VERSION 5.7 ;
BUSBITCHARS "[]" ;
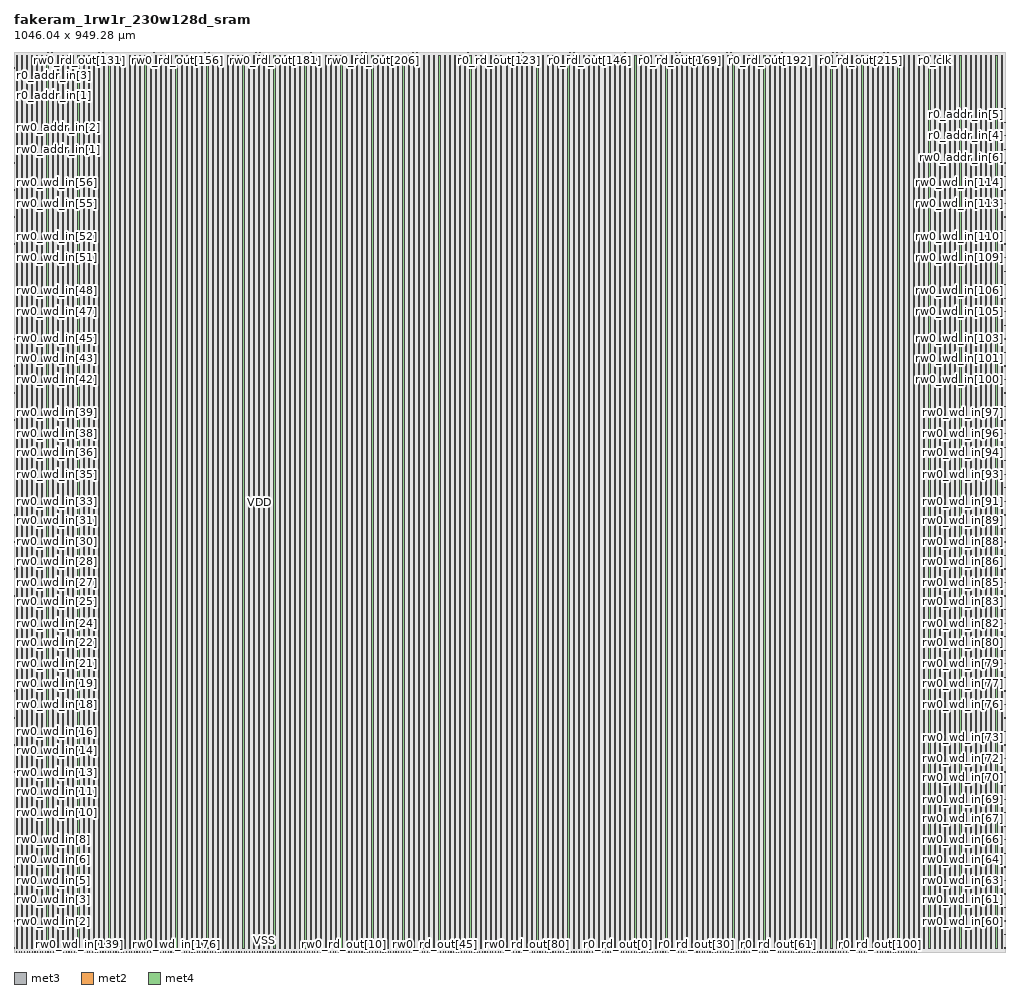
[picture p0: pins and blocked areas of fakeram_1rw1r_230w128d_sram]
MACRO fakeram_1rw1r_230w128d_sram
  FOREIGN fakeram_1rw1r_230w128d_sram 0 0 ;
  SYMMETRY X Y R90 ;
  SIZE 1046.040 BY 949.280 ;
  CLASS BLOCK ;
  PIN rw0_wd_in[0]
    DIRECTION INPUT ;
    USE SIGNAL ;
    SHAPE ABUTMENT ;
    PORT
      LAYER met3 ;
      RECT 0.000 3.930 0.900 4.230 ;
    END
  END rw0_wd_in[0]
  PIN rw0_wd_in[1]
    DIRECTION INPUT ;
    USE SIGNAL ;
    SHAPE ABUTMENT ;
    PORT
      LAYER met3 ;
      RECT 0.000 18.210 0.900 18.510 ;
    END
  END rw0_wd_in[1]
  PIN rw0_wd_in[2]
    DIRECTION INPUT ;
    USE SIGNAL ;
    SHAPE ABUTMENT ;
    PORT
      LAYER met3 ;
      RECT 0.000 32.490 0.900 32.790 ;
    END
  END rw0_wd_in[2]
  PIN rw0_wd_in[3]
    DIRECTION INPUT ;
    USE SIGNAL ;
    SHAPE ABUTMENT ;
    PORT
      LAYER met3 ;
      RECT 0.000 46.770 0.900 47.070 ;
    END
  END rw0_wd_in[3]
  PIN rw0_wd_in[4]
    DIRECTION INPUT ;
    USE SIGNAL ;
    SHAPE ABUTMENT ;
    PORT
      LAYER met3 ;
      RECT 0.000 61.050 0.900 61.350 ;
    END
  END rw0_wd_in[4]
  PIN rw0_wd_in[5]
    DIRECTION INPUT ;
    USE SIGNAL ;
    SHAPE ABUTMENT ;
    PORT
      LAYER met3 ;
      RECT 0.000 75.330 0.900 75.630 ;
    END
  END rw0_wd_in[5]
  PIN rw0_wd_in[6]
    DIRECTION INPUT ;
    USE SIGNAL ;
    SHAPE ABUTMENT ;
    PORT
      LAYER met3 ;
      RECT 0.000 89.610 0.900 89.910 ;
    END
  END rw0_wd_in[6]
  PIN rw0_wd_in[7]
    DIRECTION INPUT ;
    USE SIGNAL ;
    SHAPE ABUTMENT ;
    PORT
      LAYER met3 ;
      RECT 0.000 103.890 0.900 104.190 ;
    END
  END rw0_wd_in[7]
  PIN rw0_wd_in[8]
    DIRECTION INPUT ;
    USE SIGNAL ;
    SHAPE ABUTMENT ;
    PORT
      LAYER met3 ;
      RECT 0.000 118.170 0.900 118.470 ;
    END
  END rw0_wd_in[8]
  PIN rw0_wd_in[9]
    DIRECTION INPUT ;
    USE SIGNAL ;
    SHAPE ABUTMENT ;
    PORT
      LAYER met3 ;
      RECT 0.000 132.450 0.900 132.750 ;
    END
  END rw0_wd_in[9]
  PIN rw0_wd_in[10]
    DIRECTION INPUT ;
    USE SIGNAL ;
    SHAPE ABUTMENT ;
    PORT
      LAYER met3 ;
      RECT 0.000 146.730 0.900 147.030 ;
    END
  END rw0_wd_in[10]
  PIN rw0_wd_in[11]
    DIRECTION INPUT ;
    USE SIGNAL ;
    SHAPE ABUTMENT ;
    PORT
      LAYER met3 ;
      RECT 0.000 161.010 0.900 161.310 ;
    END
  END rw0_wd_in[11]
  PIN rw0_wd_in[12]
    DIRECTION INPUT ;
    USE SIGNAL ;
    SHAPE ABUTMENT ;
    PORT
      LAYER met3 ;
      RECT 0.000 175.290 0.900 175.590 ;
    END
  END rw0_wd_in[12]
  PIN rw0_wd_in[13]
    DIRECTION INPUT ;
    USE SIGNAL ;
    SHAPE ABUTMENT ;
    PORT
      LAYER met3 ;
      RECT 0.000 189.570 0.900 189.870 ;
    END
  END rw0_wd_in[13]
  PIN rw0_wd_in[14]
    DIRECTION INPUT ;
    USE SIGNAL ;
    SHAPE ABUTMENT ;
    PORT
      LAYER met3 ;
      RECT 0.000 203.850 0.900 204.150 ;
    END
  END rw0_wd_in[14]
  PIN rw0_wd_in[15]
    DIRECTION INPUT ;
    USE SIGNAL ;
    SHAPE ABUTMENT ;
    PORT
      LAYER met3 ;
      RECT 0.000 218.130 0.900 218.430 ;
    END
  END rw0_wd_in[15]
  PIN rw0_wd_in[16]
    DIRECTION INPUT ;
    USE SIGNAL ;
    SHAPE ABUTMENT ;
    PORT
      LAYER met3 ;
      RECT 0.000 232.410 0.900 232.710 ;
    END
  END rw0_wd_in[16]
  PIN rw0_wd_in[17]
    DIRECTION INPUT ;
    USE SIGNAL ;
    SHAPE ABUTMENT ;
    PORT
      LAYER met3 ;
      RECT 0.000 246.690 0.900 246.990 ;
    END
  END rw0_wd_in[17]
  PIN rw0_wd_in[18]
    DIRECTION INPUT ;
    USE SIGNAL ;
    SHAPE ABUTMENT ;
    PORT
      LAYER met3 ;
      RECT 0.000 260.970 0.900 261.270 ;
    END
  END rw0_wd_in[18]
  PIN rw0_wd_in[19]
    DIRECTION INPUT ;
    USE SIGNAL ;
    SHAPE ABUTMENT ;
    PORT
      LAYER met3 ;
      RECT 0.000 275.250 0.900 275.550 ;
    END
  END rw0_wd_in[19]
  PIN rw0_wd_in[20]
    DIRECTION INPUT ;
    USE SIGNAL ;
    SHAPE ABUTMENT ;
    PORT
      LAYER met3 ;
      RECT 0.000 289.530 0.900 289.830 ;
    END
  END rw0_wd_in[20]
  PIN rw0_wd_in[21]
    DIRECTION INPUT ;
    USE SIGNAL ;
    SHAPE ABUTMENT ;
    PORT
      LAYER met3 ;
      RECT 0.000 303.810 0.900 304.110 ;
    END
  END rw0_wd_in[21]
  PIN rw0_wd_in[22]
    DIRECTION INPUT ;
    USE SIGNAL ;
    SHAPE ABUTMENT ;
    PORT
      LAYER met3 ;
      RECT 0.000 318.090 0.900 318.390 ;
    END
  END rw0_wd_in[22]
  PIN rw0_wd_in[23]
    DIRECTION INPUT ;
    USE SIGNAL ;
    SHAPE ABUTMENT ;
    PORT
      LAYER met3 ;
      RECT 0.000 332.370 0.900 332.670 ;
    END
  END rw0_wd_in[23]
  PIN rw0_wd_in[24]
    DIRECTION INPUT ;
    USE SIGNAL ;
    SHAPE ABUTMENT ;
    PORT
      LAYER met3 ;
      RECT 0.000 346.650 0.900 346.950 ;
    END
  END rw0_wd_in[24]
  PIN rw0_wd_in[25]
    DIRECTION INPUT ;
    USE SIGNAL ;
    SHAPE ABUTMENT ;
    PORT
      LAYER met3 ;
      RECT 0.000 360.930 0.900 361.230 ;
    END
  END rw0_wd_in[25]
  PIN rw0_wd_in[26]
    DIRECTION INPUT ;
    USE SIGNAL ;
    SHAPE ABUTMENT ;
    PORT
      LAYER met3 ;
      RECT 0.000 375.210 0.900 375.510 ;
    END
  END rw0_wd_in[26]
  PIN rw0_wd_in[27]
    DIRECTION INPUT ;
    USE SIGNAL ;
    SHAPE ABUTMENT ;
    PORT
      LAYER met3 ;
      RECT 0.000 389.490 0.900 389.790 ;
    END
  END rw0_wd_in[27]
  PIN rw0_wd_in[28]
    DIRECTION INPUT ;
    USE SIGNAL ;
    SHAPE ABUTMENT ;
    PORT
      LAYER met3 ;
      RECT 0.000 403.770 0.900 404.070 ;
    END
  END rw0_wd_in[28]
  PIN rw0_wd_in[29]
    DIRECTION INPUT ;
    USE SIGNAL ;
    SHAPE ABUTMENT ;
    PORT
      LAYER met3 ;
      RECT 0.000 418.050 0.900 418.350 ;
    END
  END rw0_wd_in[29]
  PIN rw0_wd_in[30]
    DIRECTION INPUT ;
    USE SIGNAL ;
    SHAPE ABUTMENT ;
    PORT
      LAYER met3 ;
      RECT 0.000 432.330 0.900 432.630 ;
    END
  END rw0_wd_in[30]
  PIN rw0_wd_in[31]
    DIRECTION INPUT ;
    USE SIGNAL ;
    SHAPE ABUTMENT ;
    PORT
      LAYER met3 ;
      RECT 0.000 446.610 0.900 446.910 ;
    END
  END rw0_wd_in[31]
  PIN rw0_wd_in[32]
    DIRECTION INPUT ;
    USE SIGNAL ;
    SHAPE ABUTMENT ;
    PORT
      LAYER met3 ;
      RECT 0.000 460.890 0.900 461.190 ;
    END
  END rw0_wd_in[32]
  PIN rw0_wd_in[33]
    DIRECTION INPUT ;
    USE SIGNAL ;
    SHAPE ABUTMENT ;
    PORT
      LAYER met3 ;
      RECT 0.000 475.170 0.900 475.470 ;
    END
  END rw0_wd_in[33]
  PIN rw0_wd_in[34]
    DIRECTION INPUT ;
    USE SIGNAL ;
    SHAPE ABUTMENT ;
    PORT
      LAYER met3 ;
      RECT 0.000 489.450 0.900 489.750 ;
    END
  END rw0_wd_in[34]
  PIN rw0_wd_in[35]
    DIRECTION INPUT ;
    USE SIGNAL ;
    SHAPE ABUTMENT ;
    PORT
      LAYER met3 ;
      RECT 0.000 503.730 0.900 504.030 ;
    END
  END rw0_wd_in[35]
  PIN rw0_wd_in[36]
    DIRECTION INPUT ;
    USE SIGNAL ;
    SHAPE ABUTMENT ;
    PORT
      LAYER met3 ;
      RECT 0.000 518.010 0.900 518.310 ;
    END
  END rw0_wd_in[36]
  PIN rw0_wd_in[37]
    DIRECTION INPUT ;
    USE SIGNAL ;
    SHAPE ABUTMENT ;
    PORT
      LAYER met3 ;
      RECT 0.000 532.290 0.900 532.590 ;
    END
  END rw0_wd_in[37]
  PIN rw0_wd_in[38]
    DIRECTION INPUT ;
    USE SIGNAL ;
    SHAPE ABUTMENT ;
    PORT
      LAYER met3 ;
      RECT 0.000 546.570 0.900 546.870 ;
    END
  END rw0_wd_in[38]
  PIN rw0_wd_in[39]
    DIRECTION INPUT ;
    USE SIGNAL ;
    SHAPE ABUTMENT ;
    PORT
      LAYER met3 ;
      RECT 0.000 560.850 0.900 561.150 ;
    END
  END rw0_wd_in[39]
  PIN rw0_wd_in[40]
    DIRECTION INPUT ;
    USE SIGNAL ;
    SHAPE ABUTMENT ;
    PORT
      LAYER met3 ;
      RECT 0.000 575.130 0.900 575.430 ;
    END
  END rw0_wd_in[40]
  PIN rw0_wd_in[41]
    DIRECTION INPUT ;
    USE SIGNAL ;
    SHAPE ABUTMENT ;
    PORT
      LAYER met3 ;
      RECT 0.000 589.410 0.900 589.710 ;
    END
  END rw0_wd_in[41]
  PIN rw0_wd_in[42]
    DIRECTION INPUT ;
    USE SIGNAL ;
    SHAPE ABUTMENT ;
    PORT
      LAYER met3 ;
      RECT 0.000 603.690 0.900 603.990 ;
    END
  END rw0_wd_in[42]
  PIN rw0_wd_in[43]
    DIRECTION INPUT ;
    USE SIGNAL ;
    SHAPE ABUTMENT ;
    PORT
      LAYER met3 ;
      RECT 0.000 617.970 0.900 618.270 ;
    END
  END rw0_wd_in[43]
  PIN rw0_wd_in[44]
    DIRECTION INPUT ;
    USE SIGNAL ;
    SHAPE ABUTMENT ;
    PORT
      LAYER met3 ;
      RECT 0.000 632.250 0.900 632.550 ;
    END
  END rw0_wd_in[44]
  PIN rw0_wd_in[45]
    DIRECTION INPUT ;
    USE SIGNAL ;
    SHAPE ABUTMENT ;
    PORT
      LAYER met3 ;
      RECT 0.000 646.530 0.900 646.830 ;
    END
  END rw0_wd_in[45]
  PIN rw0_wd_in[46]
    DIRECTION INPUT ;
    USE SIGNAL ;
    SHAPE ABUTMENT ;
    PORT
      LAYER met3 ;
      RECT 0.000 660.810 0.900 661.110 ;
    END
  END rw0_wd_in[46]
  PIN rw0_wd_in[47]
    DIRECTION INPUT ;
    USE SIGNAL ;
    SHAPE ABUTMENT ;
    PORT
      LAYER met3 ;
      RECT 0.000 675.090 0.900 675.390 ;
    END
  END rw0_wd_in[47]
  PIN rw0_wd_in[48]
    DIRECTION INPUT ;
    USE SIGNAL ;
    SHAPE ABUTMENT ;
    PORT
      LAYER met3 ;
      RECT 0.000 689.370 0.900 689.670 ;
    END
  END rw0_wd_in[48]
  PIN rw0_wd_in[49]
    DIRECTION INPUT ;
    USE SIGNAL ;
    SHAPE ABUTMENT ;
    PORT
      LAYER met3 ;
      RECT 0.000 703.650 0.900 703.950 ;
    END
  END rw0_wd_in[49]
  PIN rw0_wd_in[50]
    DIRECTION INPUT ;
    USE SIGNAL ;
    SHAPE ABUTMENT ;
    PORT
      LAYER met3 ;
      RECT 0.000 717.930 0.900 718.230 ;
    END
  END rw0_wd_in[50]
  PIN rw0_wd_in[51]
    DIRECTION INPUT ;
    USE SIGNAL ;
    SHAPE ABUTMENT ;
    PORT
      LAYER met3 ;
      RECT 0.000 732.210 0.900 732.510 ;
    END
  END rw0_wd_in[51]
  PIN rw0_wd_in[52]
    DIRECTION INPUT ;
    USE SIGNAL ;
    SHAPE ABUTMENT ;
    PORT
      LAYER met3 ;
      RECT 0.000 746.490 0.900 746.790 ;
    END
  END rw0_wd_in[52]
  PIN rw0_wd_in[53]
    DIRECTION INPUT ;
    USE SIGNAL ;
    SHAPE ABUTMENT ;
    PORT
      LAYER met3 ;
      RECT 0.000 760.770 0.900 761.070 ;
    END
  END rw0_wd_in[53]
  PIN rw0_wd_in[54]
    DIRECTION INPUT ;
    USE SIGNAL ;
    SHAPE ABUTMENT ;
    PORT
      LAYER met3 ;
      RECT 0.000 775.050 0.900 775.350 ;
    END
  END rw0_wd_in[54]
  PIN rw0_wd_in[55]
    DIRECTION INPUT ;
    USE SIGNAL ;
    SHAPE ABUTMENT ;
    PORT
      LAYER met3 ;
      RECT 0.000 789.330 0.900 789.630 ;
    END
  END rw0_wd_in[55]
  PIN rw0_wd_in[56]
    DIRECTION INPUT ;
    USE SIGNAL ;
    SHAPE ABUTMENT ;
    PORT
      LAYER met3 ;
      RECT 0.000 803.610 0.900 803.910 ;
    END
  END rw0_wd_in[56]
  PIN rw0_wd_in[57]
    DIRECTION INPUT ;
    USE SIGNAL ;
    SHAPE ABUTMENT ;
    PORT
      LAYER met3 ;
      RECT 0.000 817.890 0.900 818.190 ;
    END
  END rw0_wd_in[57]
  PIN rw0_wd_in[58]
    DIRECTION INPUT ;
    USE SIGNAL ;
    SHAPE ABUTMENT ;
    PORT
      LAYER met3 ;
      RECT 1045.140 3.930 1046.040 4.230 ;
    END
  END rw0_wd_in[58]
  PIN rw0_wd_in[59]
    DIRECTION INPUT ;
    USE SIGNAL ;
    SHAPE ABUTMENT ;
    PORT
      LAYER met3 ;
      RECT 1045.140 18.210 1046.040 18.510 ;
    END
  END rw0_wd_in[59]
  PIN rw0_wd_in[60]
    DIRECTION INPUT ;
    USE SIGNAL ;
    SHAPE ABUTMENT ;
    PORT
      LAYER met3 ;
      RECT 1045.140 32.490 1046.040 32.790 ;
    END
  END rw0_wd_in[60]
  PIN rw0_wd_in[61]
    DIRECTION INPUT ;
    USE SIGNAL ;
    SHAPE ABUTMENT ;
    PORT
      LAYER met3 ;
      RECT 1045.140 46.770 1046.040 47.070 ;
    END
  END rw0_wd_in[61]
  PIN rw0_wd_in[62]
    DIRECTION INPUT ;
    USE SIGNAL ;
    SHAPE ABUTMENT ;
    PORT
      LAYER met3 ;
      RECT 1045.140 61.050 1046.040 61.350 ;
    END
  END rw0_wd_in[62]
  PIN rw0_wd_in[63]
    DIRECTION INPUT ;
    USE SIGNAL ;
    SHAPE ABUTMENT ;
    PORT
      LAYER met3 ;
      RECT 1045.140 75.330 1046.040 75.630 ;
    END
  END rw0_wd_in[63]
  PIN rw0_wd_in[64]
    DIRECTION INPUT ;
    USE SIGNAL ;
    SHAPE ABUTMENT ;
    PORT
      LAYER met3 ;
      RECT 1045.140 89.610 1046.040 89.910 ;
    END
  END rw0_wd_in[64]
  PIN rw0_wd_in[65]
    DIRECTION INPUT ;
    USE SIGNAL ;
    SHAPE ABUTMENT ;
    PORT
      LAYER met3 ;
      RECT 1045.140 103.890 1046.040 104.190 ;
    END
  END rw0_wd_in[65]
  PIN rw0_wd_in[66]
    DIRECTION INPUT ;
    USE SIGNAL ;
    SHAPE ABUTMENT ;
    PORT
      LAYER met3 ;
      RECT 1045.140 118.170 1046.040 118.470 ;
    END
  END rw0_wd_in[66]
  PIN rw0_wd_in[67]
    DIRECTION INPUT ;
    USE SIGNAL ;
    SHAPE ABUTMENT ;
    PORT
      LAYER met3 ;
      RECT 1045.140 132.450 1046.040 132.750 ;
    END
  END rw0_wd_in[67]
  PIN rw0_wd_in[68]
    DIRECTION INPUT ;
    USE SIGNAL ;
    SHAPE ABUTMENT ;
    PORT
      LAYER met3 ;
      RECT 1045.140 146.730 1046.040 147.030 ;
    END
  END rw0_wd_in[68]
  PIN rw0_wd_in[69]
    DIRECTION INPUT ;
    USE SIGNAL ;
    SHAPE ABUTMENT ;
    PORT
      LAYER met3 ;
      RECT 1045.140 161.010 1046.040 161.310 ;
    END
  END rw0_wd_in[69]
  PIN rw0_wd_in[70]
    DIRECTION INPUT ;
    USE SIGNAL ;
    SHAPE ABUTMENT ;
    PORT
      LAYER met3 ;
      RECT 1045.140 175.290 1046.040 175.590 ;
    END
  END rw0_wd_in[70]
  PIN rw0_wd_in[71]
    DIRECTION INPUT ;
    USE SIGNAL ;
    SHAPE ABUTMENT ;
    PORT
      LAYER met3 ;
      RECT 1045.140 189.570 1046.040 189.870 ;
    END
  END rw0_wd_in[71]
  PIN rw0_wd_in[72]
    DIRECTION INPUT ;
    USE SIGNAL ;
    SHAPE ABUTMENT ;
    PORT
      LAYER met3 ;
      RECT 1045.140 203.850 1046.040 204.150 ;
    END
  END rw0_wd_in[72]
  PIN rw0_wd_in[73]
    DIRECTION INPUT ;
    USE SIGNAL ;
    SHAPE ABUTMENT ;
    PORT
      LAYER met3 ;
      RECT 1045.140 218.130 1046.040 218.430 ;
    END
  END rw0_wd_in[73]
  PIN rw0_wd_in[74]
    DIRECTION INPUT ;
    USE SIGNAL ;
    SHAPE ABUTMENT ;
    PORT
      LAYER met3 ;
      RECT 1045.140 232.410 1046.040 232.710 ;
    END
  END rw0_wd_in[74]
  PIN rw0_wd_in[75]
    DIRECTION INPUT ;
    USE SIGNAL ;
    SHAPE ABUTMENT ;
    PORT
      LAYER met3 ;
      RECT 1045.140 246.690 1046.040 246.990 ;
    END
  END rw0_wd_in[75]
  PIN rw0_wd_in[76]
    DIRECTION INPUT ;
    USE SIGNAL ;
    SHAPE ABUTMENT ;
    PORT
      LAYER met3 ;
      RECT 1045.140 260.970 1046.040 261.270 ;
    END
  END rw0_wd_in[76]
  PIN rw0_wd_in[77]
    DIRECTION INPUT ;
    USE SIGNAL ;
    SHAPE ABUTMENT ;
    PORT
      LAYER met3 ;
      RECT 1045.140 275.250 1046.040 275.550 ;
    END
  END rw0_wd_in[77]
  PIN rw0_wd_in[78]
    DIRECTION INPUT ;
    USE SIGNAL ;
    SHAPE ABUTMENT ;
    PORT
      LAYER met3 ;
      RECT 1045.140 289.530 1046.040 289.830 ;
    END
  END rw0_wd_in[78]
  PIN rw0_wd_in[79]
    DIRECTION INPUT ;
    USE SIGNAL ;
    SHAPE ABUTMENT ;
    PORT
      LAYER met3 ;
      RECT 1045.140 303.810 1046.040 304.110 ;
    END
  END rw0_wd_in[79]
  PIN rw0_wd_in[80]
    DIRECTION INPUT ;
    USE SIGNAL ;
    SHAPE ABUTMENT ;
    PORT
      LAYER met3 ;
      RECT 1045.140 318.090 1046.040 318.390 ;
    END
  END rw0_wd_in[80]
  PIN rw0_wd_in[81]
    DIRECTION INPUT ;
    USE SIGNAL ;
    SHAPE ABUTMENT ;
    PORT
      LAYER met3 ;
      RECT 1045.140 332.370 1046.040 332.670 ;
    END
  END rw0_wd_in[81]
  PIN rw0_wd_in[82]
    DIRECTION INPUT ;
    USE SIGNAL ;
    SHAPE ABUTMENT ;
    PORT
      LAYER met3 ;
      RECT 1045.140 346.650 1046.040 346.950 ;
    END
  END rw0_wd_in[82]
  PIN rw0_wd_in[83]
    DIRECTION INPUT ;
    USE SIGNAL ;
    SHAPE ABUTMENT ;
    PORT
      LAYER met3 ;
      RECT 1045.140 360.930 1046.040 361.230 ;
    END
  END rw0_wd_in[83]
  PIN rw0_wd_in[84]
    DIRECTION INPUT ;
    USE SIGNAL ;
    SHAPE ABUTMENT ;
    PORT
      LAYER met3 ;
      RECT 1045.140 375.210 1046.040 375.510 ;
    END
  END rw0_wd_in[84]
  PIN rw0_wd_in[85]
    DIRECTION INPUT ;
    USE SIGNAL ;
    SHAPE ABUTMENT ;
    PORT
      LAYER met3 ;
      RECT 1045.140 389.490 1046.040 389.790 ;
    END
  END rw0_wd_in[85]
  PIN rw0_wd_in[86]
    DIRECTION INPUT ;
    USE SIGNAL ;
    SHAPE ABUTMENT ;
    PORT
      LAYER met3 ;
      RECT 1045.140 403.770 1046.040 404.070 ;
    END
  END rw0_wd_in[86]
  PIN rw0_wd_in[87]
    DIRECTION INPUT ;
    USE SIGNAL ;
    SHAPE ABUTMENT ;
    PORT
      LAYER met3 ;
      RECT 1045.140 418.050 1046.040 418.350 ;
    END
  END rw0_wd_in[87]
  PIN rw0_wd_in[88]
    DIRECTION INPUT ;
    USE SIGNAL ;
    SHAPE ABUTMENT ;
    PORT
      LAYER met3 ;
      RECT 1045.140 432.330 1046.040 432.630 ;
    END
  END rw0_wd_in[88]
  PIN rw0_wd_in[89]
    DIRECTION INPUT ;
    USE SIGNAL ;
    SHAPE ABUTMENT ;
    PORT
      LAYER met3 ;
      RECT 1045.140 446.610 1046.040 446.910 ;
    END
  END rw0_wd_in[89]
  PIN rw0_wd_in[90]
    DIRECTION INPUT ;
    USE SIGNAL ;
    SHAPE ABUTMENT ;
    PORT
      LAYER met3 ;
      RECT 1045.140 460.890 1046.040 461.190 ;
    END
  END rw0_wd_in[90]
  PIN rw0_wd_in[91]
    DIRECTION INPUT ;
    USE SIGNAL ;
    SHAPE ABUTMENT ;
    PORT
      LAYER met3 ;
      RECT 1045.140 475.170 1046.040 475.470 ;
    END
  END rw0_wd_in[91]
  PIN rw0_wd_in[92]
    DIRECTION INPUT ;
    USE SIGNAL ;
    SHAPE ABUTMENT ;
    PORT
      LAYER met3 ;
      RECT 1045.140 489.450 1046.040 489.750 ;
    END
  END rw0_wd_in[92]
  PIN rw0_wd_in[93]
    DIRECTION INPUT ;
    USE SIGNAL ;
    SHAPE ABUTMENT ;
    PORT
      LAYER met3 ;
      RECT 1045.140 503.730 1046.040 504.030 ;
    END
  END rw0_wd_in[93]
  PIN rw0_wd_in[94]
    DIRECTION INPUT ;
    USE SIGNAL ;
    SHAPE ABUTMENT ;
    PORT
      LAYER met3 ;
      RECT 1045.140 518.010 1046.040 518.310 ;
    END
  END rw0_wd_in[94]
  PIN rw0_wd_in[95]
    DIRECTION INPUT ;
    USE SIGNAL ;
    SHAPE ABUTMENT ;
    PORT
      LAYER met3 ;
      RECT 1045.140 532.290 1046.040 532.590 ;
    END
  END rw0_wd_in[95]
  PIN rw0_wd_in[96]
    DIRECTION INPUT ;
    USE SIGNAL ;
    SHAPE ABUTMENT ;
    PORT
      LAYER met3 ;
      RECT 1045.140 546.570 1046.040 546.870 ;
    END
  END rw0_wd_in[96]
  PIN rw0_wd_in[97]
    DIRECTION INPUT ;
    USE SIGNAL ;
    SHAPE ABUTMENT ;
    PORT
      LAYER met3 ;
      RECT 1045.140 560.850 1046.040 561.150 ;
    END
  END rw0_wd_in[97]
  PIN rw0_wd_in[98]
    DIRECTION INPUT ;
    USE SIGNAL ;
    SHAPE ABUTMENT ;
    PORT
      LAYER met3 ;
      RECT 1045.140 575.130 1046.040 575.430 ;
    END
  END rw0_wd_in[98]
  PIN rw0_wd_in[99]
    DIRECTION INPUT ;
    USE SIGNAL ;
    SHAPE ABUTMENT ;
    PORT
      LAYER met3 ;
      RECT 1045.140 589.410 1046.040 589.710 ;
    END
  END rw0_wd_in[99]
  PIN rw0_wd_in[100]
    DIRECTION INPUT ;
    USE SIGNAL ;
    SHAPE ABUTMENT ;
    PORT
      LAYER met3 ;
      RECT 1045.140 603.690 1046.040 603.990 ;
    END
  END rw0_wd_in[100]
  PIN rw0_wd_in[101]
    DIRECTION INPUT ;
    USE SIGNAL ;
    SHAPE ABUTMENT ;
    PORT
      LAYER met3 ;
      RECT 1045.140 617.970 1046.040 618.270 ;
    END
  END rw0_wd_in[101]
  PIN rw0_wd_in[102]
    DIRECTION INPUT ;
    USE SIGNAL ;
    SHAPE ABUTMENT ;
    PORT
      LAYER met3 ;
      RECT 1045.140 632.250 1046.040 632.550 ;
    END
  END rw0_wd_in[102]
  PIN rw0_wd_in[103]
    DIRECTION INPUT ;
    USE SIGNAL ;
    SHAPE ABUTMENT ;
    PORT
      LAYER met3 ;
      RECT 1045.140 646.530 1046.040 646.830 ;
    END
  END rw0_wd_in[103]
  PIN rw0_wd_in[104]
    DIRECTION INPUT ;
    USE SIGNAL ;
    SHAPE ABUTMENT ;
    PORT
      LAYER met3 ;
      RECT 1045.140 660.810 1046.040 661.110 ;
    END
  END rw0_wd_in[104]
  PIN rw0_wd_in[105]
    DIRECTION INPUT ;
    USE SIGNAL ;
    SHAPE ABUTMENT ;
    PORT
      LAYER met3 ;
      RECT 1045.140 675.090 1046.040 675.390 ;
    END
  END rw0_wd_in[105]
  PIN rw0_wd_in[106]
    DIRECTION INPUT ;
    USE SIGNAL ;
    SHAPE ABUTMENT ;
    PORT
      LAYER met3 ;
      RECT 1045.140 689.370 1046.040 689.670 ;
    END
  END rw0_wd_in[106]
  PIN rw0_wd_in[107]
    DIRECTION INPUT ;
    USE SIGNAL ;
    SHAPE ABUTMENT ;
    PORT
      LAYER met3 ;
      RECT 1045.140 703.650 1046.040 703.950 ;
    END
  END rw0_wd_in[107]
  PIN rw0_wd_in[108]
    DIRECTION INPUT ;
    USE SIGNAL ;
    SHAPE ABUTMENT ;
    PORT
      LAYER met3 ;
      RECT 1045.140 717.930 1046.040 718.230 ;
    END
  END rw0_wd_in[108]
  PIN rw0_wd_in[109]
    DIRECTION INPUT ;
    USE SIGNAL ;
    SHAPE ABUTMENT ;
    PORT
      LAYER met3 ;
      RECT 1045.140 732.210 1046.040 732.510 ;
    END
  END rw0_wd_in[109]
  PIN rw0_wd_in[110]
    DIRECTION INPUT ;
    USE SIGNAL ;
    SHAPE ABUTMENT ;
    PORT
      LAYER met3 ;
      RECT 1045.140 746.490 1046.040 746.790 ;
    END
  END rw0_wd_in[110]
  PIN rw0_wd_in[111]
    DIRECTION INPUT ;
    USE SIGNAL ;
    SHAPE ABUTMENT ;
    PORT
      LAYER met3 ;
      RECT 1045.140 760.770 1046.040 761.070 ;
    END
  END rw0_wd_in[111]
  PIN rw0_wd_in[112]
    DIRECTION INPUT ;
    USE SIGNAL ;
    SHAPE ABUTMENT ;
    PORT
      LAYER met3 ;
      RECT 1045.140 775.050 1046.040 775.350 ;
    END
  END rw0_wd_in[112]
  PIN rw0_wd_in[113]
    DIRECTION INPUT ;
    USE SIGNAL ;
    SHAPE ABUTMENT ;
    PORT
      LAYER met3 ;
      RECT 1045.140 789.330 1046.040 789.630 ;
    END
  END rw0_wd_in[113]
  PIN rw0_wd_in[114]
    DIRECTION INPUT ;
    USE SIGNAL ;
    SHAPE ABUTMENT ;
    PORT
      LAYER met3 ;
      RECT 1045.140 803.610 1046.040 803.910 ;
    END
  END rw0_wd_in[114]
  PIN rw0_wd_in[115]
    DIRECTION INPUT ;
    USE SIGNAL ;
    SHAPE ABUTMENT ;
    PORT
      LAYER met2 ;
      RECT 2.690 0.000 2.830 0.420 ;
    END
  END rw0_wd_in[115]
  PIN rw0_wd_in[116]
    DIRECTION INPUT ;
    USE SIGNAL ;
    SHAPE ABUTMENT ;
    PORT
      LAYER met2 ;
      RECT 5.450 0.000 5.590 0.420 ;
    END
  END rw0_wd_in[116]
  PIN rw0_wd_in[117]
    DIRECTION INPUT ;
    USE SIGNAL ;
    SHAPE ABUTMENT ;
    PORT
      LAYER met2 ;
      RECT 8.210 0.000 8.350 0.420 ;
    END
  END rw0_wd_in[117]
  PIN rw0_wd_in[118]
    DIRECTION INPUT ;
    USE SIGNAL ;
    SHAPE ABUTMENT ;
    PORT
      LAYER met2 ;
      RECT 10.970 0.000 11.110 0.420 ;
    END
  END rw0_wd_in[118]
  PIN rw0_wd_in[119]
    DIRECTION INPUT ;
    USE SIGNAL ;
    SHAPE ABUTMENT ;
    PORT
      LAYER met2 ;
      RECT 13.730 0.000 13.870 0.420 ;
    END
  END rw0_wd_in[119]
  PIN rw0_wd_in[120]
    DIRECTION INPUT ;
    USE SIGNAL ;
    SHAPE ABUTMENT ;
    PORT
      LAYER met2 ;
      RECT 16.490 0.000 16.630 0.420 ;
    END
  END rw0_wd_in[120]
  PIN rw0_wd_in[121]
    DIRECTION INPUT ;
    USE SIGNAL ;
    SHAPE ABUTMENT ;
    PORT
      LAYER met2 ;
      RECT 19.250 0.000 19.390 0.420 ;
    END
  END rw0_wd_in[121]
  PIN rw0_wd_in[122]
    DIRECTION INPUT ;
    USE SIGNAL ;
    SHAPE ABUTMENT ;
    PORT
      LAYER met2 ;
      RECT 22.010 0.000 22.150 0.420 ;
    END
  END rw0_wd_in[122]
  PIN rw0_wd_in[123]
    DIRECTION INPUT ;
    USE SIGNAL ;
    SHAPE ABUTMENT ;
    PORT
      LAYER met2 ;
      RECT 24.770 0.000 24.910 0.420 ;
    END
  END rw0_wd_in[123]
  PIN rw0_wd_in[124]
    DIRECTION INPUT ;
    USE SIGNAL ;
    SHAPE ABUTMENT ;
    PORT
      LAYER met2 ;
      RECT 27.530 0.000 27.670 0.420 ;
    END
  END rw0_wd_in[124]
  PIN rw0_wd_in[125]
    DIRECTION INPUT ;
    USE SIGNAL ;
    SHAPE ABUTMENT ;
    PORT
      LAYER met2 ;
      RECT 30.290 0.000 30.430 0.420 ;
    END
  END rw0_wd_in[125]
  PIN rw0_wd_in[126]
    DIRECTION INPUT ;
    USE SIGNAL ;
    SHAPE ABUTMENT ;
    PORT
      LAYER met2 ;
      RECT 33.050 0.000 33.190 0.420 ;
    END
  END rw0_wd_in[126]
  PIN rw0_wd_in[127]
    DIRECTION INPUT ;
    USE SIGNAL ;
    SHAPE ABUTMENT ;
    PORT
      LAYER met2 ;
      RECT 35.810 0.000 35.950 0.420 ;
    END
  END rw0_wd_in[127]
  PIN rw0_wd_in[128]
    DIRECTION INPUT ;
    USE SIGNAL ;
    SHAPE ABUTMENT ;
    PORT
      LAYER met2 ;
      RECT 38.570 0.000 38.710 0.420 ;
    END
  END rw0_wd_in[128]
  PIN rw0_wd_in[129]
    DIRECTION INPUT ;
    USE SIGNAL ;
    SHAPE ABUTMENT ;
    PORT
      LAYER met2 ;
      RECT 41.330 0.000 41.470 0.420 ;
    END
  END rw0_wd_in[129]
  PIN rw0_wd_in[130]
    DIRECTION INPUT ;
    USE SIGNAL ;
    SHAPE ABUTMENT ;
    PORT
      LAYER met2 ;
      RECT 44.090 0.000 44.230 0.420 ;
    END
  END rw0_wd_in[130]
  PIN rw0_wd_in[131]
    DIRECTION INPUT ;
    USE SIGNAL ;
    SHAPE ABUTMENT ;
    PORT
      LAYER met2 ;
      RECT 46.850 0.000 46.990 0.420 ;
    END
  END rw0_wd_in[131]
  PIN rw0_wd_in[132]
    DIRECTION INPUT ;
    USE SIGNAL ;
    SHAPE ABUTMENT ;
    PORT
      LAYER met2 ;
      RECT 49.610 0.000 49.750 0.420 ;
    END
  END rw0_wd_in[132]
  PIN rw0_wd_in[133]
    DIRECTION INPUT ;
    USE SIGNAL ;
    SHAPE ABUTMENT ;
    PORT
      LAYER met2 ;
      RECT 52.370 0.000 52.510 0.420 ;
    END
  END rw0_wd_in[133]
  PIN rw0_wd_in[134]
    DIRECTION INPUT ;
    USE SIGNAL ;
    SHAPE ABUTMENT ;
    PORT
      LAYER met2 ;
      RECT 55.130 0.000 55.270 0.420 ;
    END
  END rw0_wd_in[134]
  PIN rw0_wd_in[135]
    DIRECTION INPUT ;
    USE SIGNAL ;
    SHAPE ABUTMENT ;
    PORT
      LAYER met2 ;
      RECT 57.890 0.000 58.030 0.420 ;
    END
  END rw0_wd_in[135]
  PIN rw0_wd_in[136]
    DIRECTION INPUT ;
    USE SIGNAL ;
    SHAPE ABUTMENT ;
    PORT
      LAYER met2 ;
      RECT 60.650 0.000 60.790 0.420 ;
    END
  END rw0_wd_in[136]
  PIN rw0_wd_in[137]
    DIRECTION INPUT ;
    USE SIGNAL ;
    SHAPE ABUTMENT ;
    PORT
      LAYER met2 ;
      RECT 63.410 0.000 63.550 0.420 ;
    END
  END rw0_wd_in[137]
  PIN rw0_wd_in[138]
    DIRECTION INPUT ;
    USE SIGNAL ;
    SHAPE ABUTMENT ;
    PORT
      LAYER met2 ;
      RECT 66.170 0.000 66.310 0.420 ;
    END
  END rw0_wd_in[138]
  PIN rw0_wd_in[139]
    DIRECTION INPUT ;
    USE SIGNAL ;
    SHAPE ABUTMENT ;
    PORT
      LAYER met2 ;
      RECT 68.930 0.000 69.070 0.420 ;
    END
  END rw0_wd_in[139]
  PIN rw0_wd_in[140]
    DIRECTION INPUT ;
    USE SIGNAL ;
    SHAPE ABUTMENT ;
    PORT
      LAYER met2 ;
      RECT 71.690 0.000 71.830 0.420 ;
    END
  END rw0_wd_in[140]
  PIN rw0_wd_in[141]
    DIRECTION INPUT ;
    USE SIGNAL ;
    SHAPE ABUTMENT ;
    PORT
      LAYER met2 ;
      RECT 74.450 0.000 74.590 0.420 ;
    END
  END rw0_wd_in[141]
  PIN rw0_wd_in[142]
    DIRECTION INPUT ;
    USE SIGNAL ;
    SHAPE ABUTMENT ;
    PORT
      LAYER met2 ;
      RECT 77.210 0.000 77.350 0.420 ;
    END
  END rw0_wd_in[142]
  PIN rw0_wd_in[143]
    DIRECTION INPUT ;
    USE SIGNAL ;
    SHAPE ABUTMENT ;
    PORT
      LAYER met2 ;
      RECT 79.970 0.000 80.110 0.420 ;
    END
  END rw0_wd_in[143]
  PIN rw0_wd_in[144]
    DIRECTION INPUT ;
    USE SIGNAL ;
    SHAPE ABUTMENT ;
    PORT
      LAYER met2 ;
      RECT 82.730 0.000 82.870 0.420 ;
    END
  END rw0_wd_in[144]
  PIN rw0_wd_in[145]
    DIRECTION INPUT ;
    USE SIGNAL ;
    SHAPE ABUTMENT ;
    PORT
      LAYER met2 ;
      RECT 85.490 0.000 85.630 0.420 ;
    END
  END rw0_wd_in[145]
  PIN rw0_wd_in[146]
    DIRECTION INPUT ;
    USE SIGNAL ;
    SHAPE ABUTMENT ;
    PORT
      LAYER met2 ;
      RECT 88.250 0.000 88.390 0.420 ;
    END
  END rw0_wd_in[146]
  PIN rw0_wd_in[147]
    DIRECTION INPUT ;
    USE SIGNAL ;
    SHAPE ABUTMENT ;
    PORT
      LAYER met2 ;
      RECT 91.010 0.000 91.150 0.420 ;
    END
  END rw0_wd_in[147]
  PIN rw0_wd_in[148]
    DIRECTION INPUT ;
    USE SIGNAL ;
    SHAPE ABUTMENT ;
    PORT
      LAYER met2 ;
      RECT 93.770 0.000 93.910 0.420 ;
    END
  END rw0_wd_in[148]
  PIN rw0_wd_in[149]
    DIRECTION INPUT ;
    USE SIGNAL ;
    SHAPE ABUTMENT ;
    PORT
      LAYER met2 ;
      RECT 96.530 0.000 96.670 0.420 ;
    END
  END rw0_wd_in[149]
  PIN rw0_wd_in[150]
    DIRECTION INPUT ;
    USE SIGNAL ;
    SHAPE ABUTMENT ;
    PORT
      LAYER met2 ;
      RECT 99.290 0.000 99.430 0.420 ;
    END
  END rw0_wd_in[150]
  PIN rw0_wd_in[151]
    DIRECTION INPUT ;
    USE SIGNAL ;
    SHAPE ABUTMENT ;
    PORT
      LAYER met2 ;
      RECT 102.050 0.000 102.190 0.420 ;
    END
  END rw0_wd_in[151]
  PIN rw0_wd_in[152]
    DIRECTION INPUT ;
    USE SIGNAL ;
    SHAPE ABUTMENT ;
    PORT
      LAYER met2 ;
      RECT 104.810 0.000 104.950 0.420 ;
    END
  END rw0_wd_in[152]
  PIN rw0_wd_in[153]
    DIRECTION INPUT ;
    USE SIGNAL ;
    SHAPE ABUTMENT ;
    PORT
      LAYER met2 ;
      RECT 107.570 0.000 107.710 0.420 ;
    END
  END rw0_wd_in[153]
  PIN rw0_wd_in[154]
    DIRECTION INPUT ;
    USE SIGNAL ;
    SHAPE ABUTMENT ;
    PORT
      LAYER met2 ;
      RECT 110.330 0.000 110.470 0.420 ;
    END
  END rw0_wd_in[154]
  PIN rw0_wd_in[155]
    DIRECTION INPUT ;
    USE SIGNAL ;
    SHAPE ABUTMENT ;
    PORT
      LAYER met2 ;
      RECT 113.090 0.000 113.230 0.420 ;
    END
  END rw0_wd_in[155]
  PIN rw0_wd_in[156]
    DIRECTION INPUT ;
    USE SIGNAL ;
    SHAPE ABUTMENT ;
    PORT
      LAYER met2 ;
      RECT 115.850 0.000 115.990 0.420 ;
    END
  END rw0_wd_in[156]
  PIN rw0_wd_in[157]
    DIRECTION INPUT ;
    USE SIGNAL ;
    SHAPE ABUTMENT ;
    PORT
      LAYER met2 ;
      RECT 118.610 0.000 118.750 0.420 ;
    END
  END rw0_wd_in[157]
  PIN rw0_wd_in[158]
    DIRECTION INPUT ;
    USE SIGNAL ;
    SHAPE ABUTMENT ;
    PORT
      LAYER met2 ;
      RECT 121.370 0.000 121.510 0.420 ;
    END
  END rw0_wd_in[158]
  PIN rw0_wd_in[159]
    DIRECTION INPUT ;
    USE SIGNAL ;
    SHAPE ABUTMENT ;
    PORT
      LAYER met2 ;
      RECT 124.130 0.000 124.270 0.420 ;
    END
  END rw0_wd_in[159]
  PIN rw0_wd_in[160]
    DIRECTION INPUT ;
    USE SIGNAL ;
    SHAPE ABUTMENT ;
    PORT
      LAYER met2 ;
      RECT 126.890 0.000 127.030 0.420 ;
    END
  END rw0_wd_in[160]
  PIN rw0_wd_in[161]
    DIRECTION INPUT ;
    USE SIGNAL ;
    SHAPE ABUTMENT ;
    PORT
      LAYER met2 ;
      RECT 129.650 0.000 129.790 0.420 ;
    END
  END rw0_wd_in[161]
  PIN rw0_wd_in[162]
    DIRECTION INPUT ;
    USE SIGNAL ;
    SHAPE ABUTMENT ;
    PORT
      LAYER met2 ;
      RECT 132.410 0.000 132.550 0.420 ;
    END
  END rw0_wd_in[162]
  PIN rw0_wd_in[163]
    DIRECTION INPUT ;
    USE SIGNAL ;
    SHAPE ABUTMENT ;
    PORT
      LAYER met2 ;
      RECT 135.170 0.000 135.310 0.420 ;
    END
  END rw0_wd_in[163]
  PIN rw0_wd_in[164]
    DIRECTION INPUT ;
    USE SIGNAL ;
    SHAPE ABUTMENT ;
    PORT
      LAYER met2 ;
      RECT 137.930 0.000 138.070 0.420 ;
    END
  END rw0_wd_in[164]
  PIN rw0_wd_in[165]
    DIRECTION INPUT ;
    USE SIGNAL ;
    SHAPE ABUTMENT ;
    PORT
      LAYER met2 ;
      RECT 140.690 0.000 140.830 0.420 ;
    END
  END rw0_wd_in[165]
  PIN rw0_wd_in[166]
    DIRECTION INPUT ;
    USE SIGNAL ;
    SHAPE ABUTMENT ;
    PORT
      LAYER met2 ;
      RECT 143.450 0.000 143.590 0.420 ;
    END
  END rw0_wd_in[166]
  PIN rw0_wd_in[167]
    DIRECTION INPUT ;
    USE SIGNAL ;
    SHAPE ABUTMENT ;
    PORT
      LAYER met2 ;
      RECT 146.210 0.000 146.350 0.420 ;
    END
  END rw0_wd_in[167]
  PIN rw0_wd_in[168]
    DIRECTION INPUT ;
    USE SIGNAL ;
    SHAPE ABUTMENT ;
    PORT
      LAYER met2 ;
      RECT 148.970 0.000 149.110 0.420 ;
    END
  END rw0_wd_in[168]
  PIN rw0_wd_in[169]
    DIRECTION INPUT ;
    USE SIGNAL ;
    SHAPE ABUTMENT ;
    PORT
      LAYER met2 ;
      RECT 151.730 0.000 151.870 0.420 ;
    END
  END rw0_wd_in[169]
  PIN rw0_wd_in[170]
    DIRECTION INPUT ;
    USE SIGNAL ;
    SHAPE ABUTMENT ;
    PORT
      LAYER met2 ;
      RECT 154.490 0.000 154.630 0.420 ;
    END
  END rw0_wd_in[170]
  PIN rw0_wd_in[171]
    DIRECTION INPUT ;
    USE SIGNAL ;
    SHAPE ABUTMENT ;
    PORT
      LAYER met2 ;
      RECT 157.250 0.000 157.390 0.420 ;
    END
  END rw0_wd_in[171]
  PIN rw0_wd_in[172]
    DIRECTION INPUT ;
    USE SIGNAL ;
    SHAPE ABUTMENT ;
    PORT
      LAYER met2 ;
      RECT 160.010 0.000 160.150 0.420 ;
    END
  END rw0_wd_in[172]
  PIN rw0_wd_in[173]
    DIRECTION INPUT ;
    USE SIGNAL ;
    SHAPE ABUTMENT ;
    PORT
      LAYER met2 ;
      RECT 162.770 0.000 162.910 0.420 ;
    END
  END rw0_wd_in[173]
  PIN rw0_wd_in[174]
    DIRECTION INPUT ;
    USE SIGNAL ;
    SHAPE ABUTMENT ;
    PORT
      LAYER met2 ;
      RECT 165.530 0.000 165.670 0.420 ;
    END
  END rw0_wd_in[174]
  PIN rw0_wd_in[175]
    DIRECTION INPUT ;
    USE SIGNAL ;
    SHAPE ABUTMENT ;
    PORT
      LAYER met2 ;
      RECT 168.290 0.000 168.430 0.420 ;
    END
  END rw0_wd_in[175]
  PIN rw0_wd_in[176]
    DIRECTION INPUT ;
    USE SIGNAL ;
    SHAPE ABUTMENT ;
    PORT
      LAYER met2 ;
      RECT 171.050 0.000 171.190 0.420 ;
    END
  END rw0_wd_in[176]
  PIN rw0_wd_in[177]
    DIRECTION INPUT ;
    USE SIGNAL ;
    SHAPE ABUTMENT ;
    PORT
      LAYER met2 ;
      RECT 173.810 0.000 173.950 0.420 ;
    END
  END rw0_wd_in[177]
  PIN rw0_wd_in[178]
    DIRECTION INPUT ;
    USE SIGNAL ;
    SHAPE ABUTMENT ;
    PORT
      LAYER met2 ;
      RECT 176.570 0.000 176.710 0.420 ;
    END
  END rw0_wd_in[178]
  PIN rw0_wd_in[179]
    DIRECTION INPUT ;
    USE SIGNAL ;
    SHAPE ABUTMENT ;
    PORT
      LAYER met2 ;
      RECT 179.330 0.000 179.470 0.420 ;
    END
  END rw0_wd_in[179]
  PIN rw0_wd_in[180]
    DIRECTION INPUT ;
    USE SIGNAL ;
    SHAPE ABUTMENT ;
    PORT
      LAYER met2 ;
      RECT 182.090 0.000 182.230 0.420 ;
    END
  END rw0_wd_in[180]
  PIN rw0_wd_in[181]
    DIRECTION INPUT ;
    USE SIGNAL ;
    SHAPE ABUTMENT ;
    PORT
      LAYER met2 ;
      RECT 184.850 0.000 184.990 0.420 ;
    END
  END rw0_wd_in[181]
  PIN rw0_wd_in[182]
    DIRECTION INPUT ;
    USE SIGNAL ;
    SHAPE ABUTMENT ;
    PORT
      LAYER met2 ;
      RECT 187.610 0.000 187.750 0.420 ;
    END
  END rw0_wd_in[182]
  PIN rw0_wd_in[183]
    DIRECTION INPUT ;
    USE SIGNAL ;
    SHAPE ABUTMENT ;
    PORT
      LAYER met2 ;
      RECT 190.370 0.000 190.510 0.420 ;
    END
  END rw0_wd_in[183]
  PIN rw0_wd_in[184]
    DIRECTION INPUT ;
    USE SIGNAL ;
    SHAPE ABUTMENT ;
    PORT
      LAYER met2 ;
      RECT 193.130 0.000 193.270 0.420 ;
    END
  END rw0_wd_in[184]
  PIN rw0_wd_in[185]
    DIRECTION INPUT ;
    USE SIGNAL ;
    SHAPE ABUTMENT ;
    PORT
      LAYER met2 ;
      RECT 195.890 0.000 196.030 0.420 ;
    END
  END rw0_wd_in[185]
  PIN rw0_wd_in[186]
    DIRECTION INPUT ;
    USE SIGNAL ;
    SHAPE ABUTMENT ;
    PORT
      LAYER met2 ;
      RECT 198.650 0.000 198.790 0.420 ;
    END
  END rw0_wd_in[186]
  PIN rw0_wd_in[187]
    DIRECTION INPUT ;
    USE SIGNAL ;
    SHAPE ABUTMENT ;
    PORT
      LAYER met2 ;
      RECT 201.410 0.000 201.550 0.420 ;
    END
  END rw0_wd_in[187]
  PIN rw0_wd_in[188]
    DIRECTION INPUT ;
    USE SIGNAL ;
    SHAPE ABUTMENT ;
    PORT
      LAYER met2 ;
      RECT 204.170 0.000 204.310 0.420 ;
    END
  END rw0_wd_in[188]
  PIN rw0_wd_in[189]
    DIRECTION INPUT ;
    USE SIGNAL ;
    SHAPE ABUTMENT ;
    PORT
      LAYER met2 ;
      RECT 206.930 0.000 207.070 0.420 ;
    END
  END rw0_wd_in[189]
  PIN rw0_wd_in[190]
    DIRECTION INPUT ;
    USE SIGNAL ;
    SHAPE ABUTMENT ;
    PORT
      LAYER met2 ;
      RECT 209.690 0.000 209.830 0.420 ;
    END
  END rw0_wd_in[190]
  PIN rw0_wd_in[191]
    DIRECTION INPUT ;
    USE SIGNAL ;
    SHAPE ABUTMENT ;
    PORT
      LAYER met2 ;
      RECT 212.450 0.000 212.590 0.420 ;
    END
  END rw0_wd_in[191]
  PIN rw0_wd_in[192]
    DIRECTION INPUT ;
    USE SIGNAL ;
    SHAPE ABUTMENT ;
    PORT
      LAYER met2 ;
      RECT 215.210 0.000 215.350 0.420 ;
    END
  END rw0_wd_in[192]
  PIN rw0_wd_in[193]
    DIRECTION INPUT ;
    USE SIGNAL ;
    SHAPE ABUTMENT ;
    PORT
      LAYER met2 ;
      RECT 217.970 0.000 218.110 0.420 ;
    END
  END rw0_wd_in[193]
  PIN rw0_wd_in[194]
    DIRECTION INPUT ;
    USE SIGNAL ;
    SHAPE ABUTMENT ;
    PORT
      LAYER met2 ;
      RECT 220.730 0.000 220.870 0.420 ;
    END
  END rw0_wd_in[194]
  PIN rw0_wd_in[195]
    DIRECTION INPUT ;
    USE SIGNAL ;
    SHAPE ABUTMENT ;
    PORT
      LAYER met2 ;
      RECT 223.490 0.000 223.630 0.420 ;
    END
  END rw0_wd_in[195]
  PIN rw0_wd_in[196]
    DIRECTION INPUT ;
    USE SIGNAL ;
    SHAPE ABUTMENT ;
    PORT
      LAYER met2 ;
      RECT 226.250 0.000 226.390 0.420 ;
    END
  END rw0_wd_in[196]
  PIN rw0_wd_in[197]
    DIRECTION INPUT ;
    USE SIGNAL ;
    SHAPE ABUTMENT ;
    PORT
      LAYER met2 ;
      RECT 229.010 0.000 229.150 0.420 ;
    END
  END rw0_wd_in[197]
  PIN rw0_wd_in[198]
    DIRECTION INPUT ;
    USE SIGNAL ;
    SHAPE ABUTMENT ;
    PORT
      LAYER met2 ;
      RECT 231.770 0.000 231.910 0.420 ;
    END
  END rw0_wd_in[198]
  PIN rw0_wd_in[199]
    DIRECTION INPUT ;
    USE SIGNAL ;
    SHAPE ABUTMENT ;
    PORT
      LAYER met2 ;
      RECT 234.530 0.000 234.670 0.420 ;
    END
  END rw0_wd_in[199]
  PIN rw0_wd_in[200]
    DIRECTION INPUT ;
    USE SIGNAL ;
    SHAPE ABUTMENT ;
    PORT
      LAYER met2 ;
      RECT 237.290 0.000 237.430 0.420 ;
    END
  END rw0_wd_in[200]
  PIN rw0_wd_in[201]
    DIRECTION INPUT ;
    USE SIGNAL ;
    SHAPE ABUTMENT ;
    PORT
      LAYER met2 ;
      RECT 240.050 0.000 240.190 0.420 ;
    END
  END rw0_wd_in[201]
  PIN rw0_wd_in[202]
    DIRECTION INPUT ;
    USE SIGNAL ;
    SHAPE ABUTMENT ;
    PORT
      LAYER met2 ;
      RECT 242.810 0.000 242.950 0.420 ;
    END
  END rw0_wd_in[202]
  PIN rw0_wd_in[203]
    DIRECTION INPUT ;
    USE SIGNAL ;
    SHAPE ABUTMENT ;
    PORT
      LAYER met2 ;
      RECT 245.570 0.000 245.710 0.420 ;
    END
  END rw0_wd_in[203]
  PIN rw0_wd_in[204]
    DIRECTION INPUT ;
    USE SIGNAL ;
    SHAPE ABUTMENT ;
    PORT
      LAYER met2 ;
      RECT 248.330 0.000 248.470 0.420 ;
    END
  END rw0_wd_in[204]
  PIN rw0_wd_in[205]
    DIRECTION INPUT ;
    USE SIGNAL ;
    SHAPE ABUTMENT ;
    PORT
      LAYER met2 ;
      RECT 251.090 0.000 251.230 0.420 ;
    END
  END rw0_wd_in[205]
  PIN rw0_wd_in[206]
    DIRECTION INPUT ;
    USE SIGNAL ;
    SHAPE ABUTMENT ;
    PORT
      LAYER met2 ;
      RECT 253.850 0.000 253.990 0.420 ;
    END
  END rw0_wd_in[206]
  PIN rw0_wd_in[207]
    DIRECTION INPUT ;
    USE SIGNAL ;
    SHAPE ABUTMENT ;
    PORT
      LAYER met2 ;
      RECT 256.610 0.000 256.750 0.420 ;
    END
  END rw0_wd_in[207]
  PIN rw0_wd_in[208]
    DIRECTION INPUT ;
    USE SIGNAL ;
    SHAPE ABUTMENT ;
    PORT
      LAYER met2 ;
      RECT 259.370 0.000 259.510 0.420 ;
    END
  END rw0_wd_in[208]
  PIN rw0_wd_in[209]
    DIRECTION INPUT ;
    USE SIGNAL ;
    SHAPE ABUTMENT ;
    PORT
      LAYER met2 ;
      RECT 262.130 0.000 262.270 0.420 ;
    END
  END rw0_wd_in[209]
  PIN rw0_wd_in[210]
    DIRECTION INPUT ;
    USE SIGNAL ;
    SHAPE ABUTMENT ;
    PORT
      LAYER met2 ;
      RECT 264.890 0.000 265.030 0.420 ;
    END
  END rw0_wd_in[210]
  PIN rw0_wd_in[211]
    DIRECTION INPUT ;
    USE SIGNAL ;
    SHAPE ABUTMENT ;
    PORT
      LAYER met2 ;
      RECT 267.650 0.000 267.790 0.420 ;
    END
  END rw0_wd_in[211]
  PIN rw0_wd_in[212]
    DIRECTION INPUT ;
    USE SIGNAL ;
    SHAPE ABUTMENT ;
    PORT
      LAYER met2 ;
      RECT 270.410 0.000 270.550 0.420 ;
    END
  END rw0_wd_in[212]
  PIN rw0_wd_in[213]
    DIRECTION INPUT ;
    USE SIGNAL ;
    SHAPE ABUTMENT ;
    PORT
      LAYER met2 ;
      RECT 273.170 0.000 273.310 0.420 ;
    END
  END rw0_wd_in[213]
  PIN rw0_wd_in[214]
    DIRECTION INPUT ;
    USE SIGNAL ;
    SHAPE ABUTMENT ;
    PORT
      LAYER met2 ;
      RECT 275.930 0.000 276.070 0.420 ;
    END
  END rw0_wd_in[214]
  PIN rw0_wd_in[215]
    DIRECTION INPUT ;
    USE SIGNAL ;
    SHAPE ABUTMENT ;
    PORT
      LAYER met2 ;
      RECT 278.690 0.000 278.830 0.420 ;
    END
  END rw0_wd_in[215]
  PIN rw0_wd_in[216]
    DIRECTION INPUT ;
    USE SIGNAL ;
    SHAPE ABUTMENT ;
    PORT
      LAYER met2 ;
      RECT 281.450 0.000 281.590 0.420 ;
    END
  END rw0_wd_in[216]
  PIN rw0_wd_in[217]
    DIRECTION INPUT ;
    USE SIGNAL ;
    SHAPE ABUTMENT ;
    PORT
      LAYER met2 ;
      RECT 284.210 0.000 284.350 0.420 ;
    END
  END rw0_wd_in[217]
  PIN rw0_wd_in[218]
    DIRECTION INPUT ;
    USE SIGNAL ;
    SHAPE ABUTMENT ;
    PORT
      LAYER met2 ;
      RECT 286.970 0.000 287.110 0.420 ;
    END
  END rw0_wd_in[218]
  PIN rw0_wd_in[219]
    DIRECTION INPUT ;
    USE SIGNAL ;
    SHAPE ABUTMENT ;
    PORT
      LAYER met2 ;
      RECT 289.730 0.000 289.870 0.420 ;
    END
  END rw0_wd_in[219]
  PIN rw0_wd_in[220]
    DIRECTION INPUT ;
    USE SIGNAL ;
    SHAPE ABUTMENT ;
    PORT
      LAYER met2 ;
      RECT 292.490 0.000 292.630 0.420 ;
    END
  END rw0_wd_in[220]
  PIN rw0_wd_in[221]
    DIRECTION INPUT ;
    USE SIGNAL ;
    SHAPE ABUTMENT ;
    PORT
      LAYER met2 ;
      RECT 295.250 0.000 295.390 0.420 ;
    END
  END rw0_wd_in[221]
  PIN rw0_wd_in[222]
    DIRECTION INPUT ;
    USE SIGNAL ;
    SHAPE ABUTMENT ;
    PORT
      LAYER met2 ;
      RECT 298.010 0.000 298.150 0.420 ;
    END
  END rw0_wd_in[222]
  PIN rw0_wd_in[223]
    DIRECTION INPUT ;
    USE SIGNAL ;
    SHAPE ABUTMENT ;
    PORT
      LAYER met2 ;
      RECT 300.770 0.000 300.910 0.420 ;
    END
  END rw0_wd_in[223]
  PIN rw0_wd_in[224]
    DIRECTION INPUT ;
    USE SIGNAL ;
    SHAPE ABUTMENT ;
    PORT
      LAYER met2 ;
      RECT 303.530 0.000 303.670 0.420 ;
    END
  END rw0_wd_in[224]
  PIN rw0_wd_in[225]
    DIRECTION INPUT ;
    USE SIGNAL ;
    SHAPE ABUTMENT ;
    PORT
      LAYER met2 ;
      RECT 306.290 0.000 306.430 0.420 ;
    END
  END rw0_wd_in[225]
  PIN rw0_wd_in[226]
    DIRECTION INPUT ;
    USE SIGNAL ;
    SHAPE ABUTMENT ;
    PORT
      LAYER met2 ;
      RECT 309.050 0.000 309.190 0.420 ;
    END
  END rw0_wd_in[226]
  PIN rw0_wd_in[227]
    DIRECTION INPUT ;
    USE SIGNAL ;
    SHAPE ABUTMENT ;
    PORT
      LAYER met2 ;
      RECT 311.810 0.000 311.950 0.420 ;
    END
  END rw0_wd_in[227]
  PIN rw0_wd_in[228]
    DIRECTION INPUT ;
    USE SIGNAL ;
    SHAPE ABUTMENT ;
    PORT
      LAYER met2 ;
      RECT 314.570 0.000 314.710 0.420 ;
    END
  END rw0_wd_in[228]
  PIN rw0_wd_in[229]
    DIRECTION INPUT ;
    USE SIGNAL ;
    SHAPE ABUTMENT ;
    PORT
      LAYER met2 ;
      RECT 317.330 0.000 317.470 0.420 ;
    END
  END rw0_wd_in[229]
  PIN rw0_rd_out[0]
    DIRECTION OUTPUT ;
    USE SIGNAL ;
    SHAPE ABUTMENT ;
    PORT
      LAYER met2 ;
      RECT 320.090 0.000 320.230 0.420 ;
    END
  END rw0_rd_out[0]
  PIN rw0_rd_out[1]
    DIRECTION OUTPUT ;
    USE SIGNAL ;
    SHAPE ABUTMENT ;
    PORT
      LAYER met2 ;
      RECT 322.850 0.000 322.990 0.420 ;
    END
  END rw0_rd_out[1]
  PIN rw0_rd_out[2]
    DIRECTION OUTPUT ;
    USE SIGNAL ;
    SHAPE ABUTMENT ;
    PORT
      LAYER met2 ;
      RECT 325.610 0.000 325.750 0.420 ;
    END
  END rw0_rd_out[2]
  PIN rw0_rd_out[3]
    DIRECTION OUTPUT ;
    USE SIGNAL ;
    SHAPE ABUTMENT ;
    PORT
      LAYER met2 ;
      RECT 328.370 0.000 328.510 0.420 ;
    END
  END rw0_rd_out[3]
  PIN rw0_rd_out[4]
    DIRECTION OUTPUT ;
    USE SIGNAL ;
    SHAPE ABUTMENT ;
    PORT
      LAYER met2 ;
      RECT 331.130 0.000 331.270 0.420 ;
    END
  END rw0_rd_out[4]
  PIN rw0_rd_out[5]
    DIRECTION OUTPUT ;
    USE SIGNAL ;
    SHAPE ABUTMENT ;
    PORT
      LAYER met2 ;
      RECT 333.890 0.000 334.030 0.420 ;
    END
  END rw0_rd_out[5]
  PIN rw0_rd_out[6]
    DIRECTION OUTPUT ;
    USE SIGNAL ;
    SHAPE ABUTMENT ;
    PORT
      LAYER met2 ;
      RECT 336.650 0.000 336.790 0.420 ;
    END
  END rw0_rd_out[6]
  PIN rw0_rd_out[7]
    DIRECTION OUTPUT ;
    USE SIGNAL ;
    SHAPE ABUTMENT ;
    PORT
      LAYER met2 ;
      RECT 339.410 0.000 339.550 0.420 ;
    END
  END rw0_rd_out[7]
  PIN rw0_rd_out[8]
    DIRECTION OUTPUT ;
    USE SIGNAL ;
    SHAPE ABUTMENT ;
    PORT
      LAYER met2 ;
      RECT 342.170 0.000 342.310 0.420 ;
    END
  END rw0_rd_out[8]
  PIN rw0_rd_out[9]
    DIRECTION OUTPUT ;
    USE SIGNAL ;
    SHAPE ABUTMENT ;
    PORT
      LAYER met2 ;
      RECT 344.930 0.000 345.070 0.420 ;
    END
  END rw0_rd_out[9]
  PIN rw0_rd_out[10]
    DIRECTION OUTPUT ;
    USE SIGNAL ;
    SHAPE ABUTMENT ;
    PORT
      LAYER met2 ;
      RECT 347.690 0.000 347.830 0.420 ;
    END
  END rw0_rd_out[10]
  PIN rw0_rd_out[11]
    DIRECTION OUTPUT ;
    USE SIGNAL ;
    SHAPE ABUTMENT ;
    PORT
      LAYER met2 ;
      RECT 350.450 0.000 350.590 0.420 ;
    END
  END rw0_rd_out[11]
  PIN rw0_rd_out[12]
    DIRECTION OUTPUT ;
    USE SIGNAL ;
    SHAPE ABUTMENT ;
    PORT
      LAYER met2 ;
      RECT 353.210 0.000 353.350 0.420 ;
    END
  END rw0_rd_out[12]
  PIN rw0_rd_out[13]
    DIRECTION OUTPUT ;
    USE SIGNAL ;
    SHAPE ABUTMENT ;
    PORT
      LAYER met2 ;
      RECT 355.970 0.000 356.110 0.420 ;
    END
  END rw0_rd_out[13]
  PIN rw0_rd_out[14]
    DIRECTION OUTPUT ;
    USE SIGNAL ;
    SHAPE ABUTMENT ;
    PORT
      LAYER met2 ;
      RECT 358.730 0.000 358.870 0.420 ;
    END
  END rw0_rd_out[14]
  PIN rw0_rd_out[15]
    DIRECTION OUTPUT ;
    USE SIGNAL ;
    SHAPE ABUTMENT ;
    PORT
      LAYER met2 ;
      RECT 361.490 0.000 361.630 0.420 ;
    END
  END rw0_rd_out[15]
  PIN rw0_rd_out[16]
    DIRECTION OUTPUT ;
    USE SIGNAL ;
    SHAPE ABUTMENT ;
    PORT
      LAYER met2 ;
      RECT 364.250 0.000 364.390 0.420 ;
    END
  END rw0_rd_out[16]
  PIN rw0_rd_out[17]
    DIRECTION OUTPUT ;
    USE SIGNAL ;
    SHAPE ABUTMENT ;
    PORT
      LAYER met2 ;
      RECT 367.010 0.000 367.150 0.420 ;
    END
  END rw0_rd_out[17]
  PIN rw0_rd_out[18]
    DIRECTION OUTPUT ;
    USE SIGNAL ;
    SHAPE ABUTMENT ;
    PORT
      LAYER met2 ;
      RECT 369.770 0.000 369.910 0.420 ;
    END
  END rw0_rd_out[18]
  PIN rw0_rd_out[19]
    DIRECTION OUTPUT ;
    USE SIGNAL ;
    SHAPE ABUTMENT ;
    PORT
      LAYER met2 ;
      RECT 372.530 0.000 372.670 0.420 ;
    END
  END rw0_rd_out[19]
  PIN rw0_rd_out[20]
    DIRECTION OUTPUT ;
    USE SIGNAL ;
    SHAPE ABUTMENT ;
    PORT
      LAYER met2 ;
      RECT 375.290 0.000 375.430 0.420 ;
    END
  END rw0_rd_out[20]
  PIN rw0_rd_out[21]
    DIRECTION OUTPUT ;
    USE SIGNAL ;
    SHAPE ABUTMENT ;
    PORT
      LAYER met2 ;
      RECT 378.050 0.000 378.190 0.420 ;
    END
  END rw0_rd_out[21]
  PIN rw0_rd_out[22]
    DIRECTION OUTPUT ;
    USE SIGNAL ;
    SHAPE ABUTMENT ;
    PORT
      LAYER met2 ;
      RECT 380.810 0.000 380.950 0.420 ;
    END
  END rw0_rd_out[22]
  PIN rw0_rd_out[23]
    DIRECTION OUTPUT ;
    USE SIGNAL ;
    SHAPE ABUTMENT ;
    PORT
      LAYER met2 ;
      RECT 383.570 0.000 383.710 0.420 ;
    END
  END rw0_rd_out[23]
  PIN rw0_rd_out[24]
    DIRECTION OUTPUT ;
    USE SIGNAL ;
    SHAPE ABUTMENT ;
    PORT
      LAYER met2 ;
      RECT 386.330 0.000 386.470 0.420 ;
    END
  END rw0_rd_out[24]
  PIN rw0_rd_out[25]
    DIRECTION OUTPUT ;
    USE SIGNAL ;
    SHAPE ABUTMENT ;
    PORT
      LAYER met2 ;
      RECT 389.090 0.000 389.230 0.420 ;
    END
  END rw0_rd_out[25]
  PIN rw0_rd_out[26]
    DIRECTION OUTPUT ;
    USE SIGNAL ;
    SHAPE ABUTMENT ;
    PORT
      LAYER met2 ;
      RECT 391.850 0.000 391.990 0.420 ;
    END
  END rw0_rd_out[26]
  PIN rw0_rd_out[27]
    DIRECTION OUTPUT ;
    USE SIGNAL ;
    SHAPE ABUTMENT ;
    PORT
      LAYER met2 ;
      RECT 394.610 0.000 394.750 0.420 ;
    END
  END rw0_rd_out[27]
  PIN rw0_rd_out[28]
    DIRECTION OUTPUT ;
    USE SIGNAL ;
    SHAPE ABUTMENT ;
    PORT
      LAYER met2 ;
      RECT 397.370 0.000 397.510 0.420 ;
    END
  END rw0_rd_out[28]
  PIN rw0_rd_out[29]
    DIRECTION OUTPUT ;
    USE SIGNAL ;
    SHAPE ABUTMENT ;
    PORT
      LAYER met2 ;
      RECT 400.130 0.000 400.270 0.420 ;
    END
  END rw0_rd_out[29]
  PIN rw0_rd_out[30]
    DIRECTION OUTPUT ;
    USE SIGNAL ;
    SHAPE ABUTMENT ;
    PORT
      LAYER met2 ;
      RECT 402.890 0.000 403.030 0.420 ;
    END
  END rw0_rd_out[30]
  PIN rw0_rd_out[31]
    DIRECTION OUTPUT ;
    USE SIGNAL ;
    SHAPE ABUTMENT ;
    PORT
      LAYER met2 ;
      RECT 405.650 0.000 405.790 0.420 ;
    END
  END rw0_rd_out[31]
  PIN rw0_rd_out[32]
    DIRECTION OUTPUT ;
    USE SIGNAL ;
    SHAPE ABUTMENT ;
    PORT
      LAYER met2 ;
      RECT 408.410 0.000 408.550 0.420 ;
    END
  END rw0_rd_out[32]
  PIN rw0_rd_out[33]
    DIRECTION OUTPUT ;
    USE SIGNAL ;
    SHAPE ABUTMENT ;
    PORT
      LAYER met2 ;
      RECT 411.170 0.000 411.310 0.420 ;
    END
  END rw0_rd_out[33]
  PIN rw0_rd_out[34]
    DIRECTION OUTPUT ;
    USE SIGNAL ;
    SHAPE ABUTMENT ;
    PORT
      LAYER met2 ;
      RECT 413.930 0.000 414.070 0.420 ;
    END
  END rw0_rd_out[34]
  PIN rw0_rd_out[35]
    DIRECTION OUTPUT ;
    USE SIGNAL ;
    SHAPE ABUTMENT ;
    PORT
      LAYER met2 ;
      RECT 416.690 0.000 416.830 0.420 ;
    END
  END rw0_rd_out[35]
  PIN rw0_rd_out[36]
    DIRECTION OUTPUT ;
    USE SIGNAL ;
    SHAPE ABUTMENT ;
    PORT
      LAYER met2 ;
      RECT 419.450 0.000 419.590 0.420 ;
    END
  END rw0_rd_out[36]
  PIN rw0_rd_out[37]
    DIRECTION OUTPUT ;
    USE SIGNAL ;
    SHAPE ABUTMENT ;
    PORT
      LAYER met2 ;
      RECT 422.210 0.000 422.350 0.420 ;
    END
  END rw0_rd_out[37]
  PIN rw0_rd_out[38]
    DIRECTION OUTPUT ;
    USE SIGNAL ;
    SHAPE ABUTMENT ;
    PORT
      LAYER met2 ;
      RECT 424.970 0.000 425.110 0.420 ;
    END
  END rw0_rd_out[38]
  PIN rw0_rd_out[39]
    DIRECTION OUTPUT ;
    USE SIGNAL ;
    SHAPE ABUTMENT ;
    PORT
      LAYER met2 ;
      RECT 427.730 0.000 427.870 0.420 ;
    END
  END rw0_rd_out[39]
  PIN rw0_rd_out[40]
    DIRECTION OUTPUT ;
    USE SIGNAL ;
    SHAPE ABUTMENT ;
    PORT
      LAYER met2 ;
      RECT 430.490 0.000 430.630 0.420 ;
    END
  END rw0_rd_out[40]
  PIN rw0_rd_out[41]
    DIRECTION OUTPUT ;
    USE SIGNAL ;
    SHAPE ABUTMENT ;
    PORT
      LAYER met2 ;
      RECT 433.250 0.000 433.390 0.420 ;
    END
  END rw0_rd_out[41]
  PIN rw0_rd_out[42]
    DIRECTION OUTPUT ;
    USE SIGNAL ;
    SHAPE ABUTMENT ;
    PORT
      LAYER met2 ;
      RECT 436.010 0.000 436.150 0.420 ;
    END
  END rw0_rd_out[42]
  PIN rw0_rd_out[43]
    DIRECTION OUTPUT ;
    USE SIGNAL ;
    SHAPE ABUTMENT ;
    PORT
      LAYER met2 ;
      RECT 438.770 0.000 438.910 0.420 ;
    END
  END rw0_rd_out[43]
  PIN rw0_rd_out[44]
    DIRECTION OUTPUT ;
    USE SIGNAL ;
    SHAPE ABUTMENT ;
    PORT
      LAYER met2 ;
      RECT 441.530 0.000 441.670 0.420 ;
    END
  END rw0_rd_out[44]
  PIN rw0_rd_out[45]
    DIRECTION OUTPUT ;
    USE SIGNAL ;
    SHAPE ABUTMENT ;
    PORT
      LAYER met2 ;
      RECT 444.290 0.000 444.430 0.420 ;
    END
  END rw0_rd_out[45]
  PIN rw0_rd_out[46]
    DIRECTION OUTPUT ;
    USE SIGNAL ;
    SHAPE ABUTMENT ;
    PORT
      LAYER met2 ;
      RECT 447.050 0.000 447.190 0.420 ;
    END
  END rw0_rd_out[46]
  PIN rw0_rd_out[47]
    DIRECTION OUTPUT ;
    USE SIGNAL ;
    SHAPE ABUTMENT ;
    PORT
      LAYER met2 ;
      RECT 449.810 0.000 449.950 0.420 ;
    END
  END rw0_rd_out[47]
  PIN rw0_rd_out[48]
    DIRECTION OUTPUT ;
    USE SIGNAL ;
    SHAPE ABUTMENT ;
    PORT
      LAYER met2 ;
      RECT 452.570 0.000 452.710 0.420 ;
    END
  END rw0_rd_out[48]
  PIN rw0_rd_out[49]
    DIRECTION OUTPUT ;
    USE SIGNAL ;
    SHAPE ABUTMENT ;
    PORT
      LAYER met2 ;
      RECT 455.330 0.000 455.470 0.420 ;
    END
  END rw0_rd_out[49]
  PIN rw0_rd_out[50]
    DIRECTION OUTPUT ;
    USE SIGNAL ;
    SHAPE ABUTMENT ;
    PORT
      LAYER met2 ;
      RECT 458.090 0.000 458.230 0.420 ;
    END
  END rw0_rd_out[50]
  PIN rw0_rd_out[51]
    DIRECTION OUTPUT ;
    USE SIGNAL ;
    SHAPE ABUTMENT ;
    PORT
      LAYER met2 ;
      RECT 460.850 0.000 460.990 0.420 ;
    END
  END rw0_rd_out[51]
  PIN rw0_rd_out[52]
    DIRECTION OUTPUT ;
    USE SIGNAL ;
    SHAPE ABUTMENT ;
    PORT
      LAYER met2 ;
      RECT 463.610 0.000 463.750 0.420 ;
    END
  END rw0_rd_out[52]
  PIN rw0_rd_out[53]
    DIRECTION OUTPUT ;
    USE SIGNAL ;
    SHAPE ABUTMENT ;
    PORT
      LAYER met2 ;
      RECT 466.370 0.000 466.510 0.420 ;
    END
  END rw0_rd_out[53]
  PIN rw0_rd_out[54]
    DIRECTION OUTPUT ;
    USE SIGNAL ;
    SHAPE ABUTMENT ;
    PORT
      LAYER met2 ;
      RECT 469.130 0.000 469.270 0.420 ;
    END
  END rw0_rd_out[54]
  PIN rw0_rd_out[55]
    DIRECTION OUTPUT ;
    USE SIGNAL ;
    SHAPE ABUTMENT ;
    PORT
      LAYER met2 ;
      RECT 471.890 0.000 472.030 0.420 ;
    END
  END rw0_rd_out[55]
  PIN rw0_rd_out[56]
    DIRECTION OUTPUT ;
    USE SIGNAL ;
    SHAPE ABUTMENT ;
    PORT
      LAYER met2 ;
      RECT 474.650 0.000 474.790 0.420 ;
    END
  END rw0_rd_out[56]
  PIN rw0_rd_out[57]
    DIRECTION OUTPUT ;
    USE SIGNAL ;
    SHAPE ABUTMENT ;
    PORT
      LAYER met2 ;
      RECT 477.410 0.000 477.550 0.420 ;
    END
  END rw0_rd_out[57]
  PIN rw0_rd_out[58]
    DIRECTION OUTPUT ;
    USE SIGNAL ;
    SHAPE ABUTMENT ;
    PORT
      LAYER met2 ;
      RECT 480.170 0.000 480.310 0.420 ;
    END
  END rw0_rd_out[58]
  PIN rw0_rd_out[59]
    DIRECTION OUTPUT ;
    USE SIGNAL ;
    SHAPE ABUTMENT ;
    PORT
      LAYER met2 ;
      RECT 482.930 0.000 483.070 0.420 ;
    END
  END rw0_rd_out[59]
  PIN rw0_rd_out[60]
    DIRECTION OUTPUT ;
    USE SIGNAL ;
    SHAPE ABUTMENT ;
    PORT
      LAYER met2 ;
      RECT 485.690 0.000 485.830 0.420 ;
    END
  END rw0_rd_out[60]
  PIN rw0_rd_out[61]
    DIRECTION OUTPUT ;
    USE SIGNAL ;
    SHAPE ABUTMENT ;
    PORT
      LAYER met2 ;
      RECT 488.450 0.000 488.590 0.420 ;
    END
  END rw0_rd_out[61]
  PIN rw0_rd_out[62]
    DIRECTION OUTPUT ;
    USE SIGNAL ;
    SHAPE ABUTMENT ;
    PORT
      LAYER met2 ;
      RECT 491.210 0.000 491.350 0.420 ;
    END
  END rw0_rd_out[62]
  PIN rw0_rd_out[63]
    DIRECTION OUTPUT ;
    USE SIGNAL ;
    SHAPE ABUTMENT ;
    PORT
      LAYER met2 ;
      RECT 493.970 0.000 494.110 0.420 ;
    END
  END rw0_rd_out[63]
  PIN rw0_rd_out[64]
    DIRECTION OUTPUT ;
    USE SIGNAL ;
    SHAPE ABUTMENT ;
    PORT
      LAYER met2 ;
      RECT 496.730 0.000 496.870 0.420 ;
    END
  END rw0_rd_out[64]
  PIN rw0_rd_out[65]
    DIRECTION OUTPUT ;
    USE SIGNAL ;
    SHAPE ABUTMENT ;
    PORT
      LAYER met2 ;
      RECT 499.490 0.000 499.630 0.420 ;
    END
  END rw0_rd_out[65]
  PIN rw0_rd_out[66]
    DIRECTION OUTPUT ;
    USE SIGNAL ;
    SHAPE ABUTMENT ;
    PORT
      LAYER met2 ;
      RECT 502.250 0.000 502.390 0.420 ;
    END
  END rw0_rd_out[66]
  PIN rw0_rd_out[67]
    DIRECTION OUTPUT ;
    USE SIGNAL ;
    SHAPE ABUTMENT ;
    PORT
      LAYER met2 ;
      RECT 505.010 0.000 505.150 0.420 ;
    END
  END rw0_rd_out[67]
  PIN rw0_rd_out[68]
    DIRECTION OUTPUT ;
    USE SIGNAL ;
    SHAPE ABUTMENT ;
    PORT
      LAYER met2 ;
      RECT 507.770 0.000 507.910 0.420 ;
    END
  END rw0_rd_out[68]
  PIN rw0_rd_out[69]
    DIRECTION OUTPUT ;
    USE SIGNAL ;
    SHAPE ABUTMENT ;
    PORT
      LAYER met2 ;
      RECT 510.530 0.000 510.670 0.420 ;
    END
  END rw0_rd_out[69]
  PIN rw0_rd_out[70]
    DIRECTION OUTPUT ;
    USE SIGNAL ;
    SHAPE ABUTMENT ;
    PORT
      LAYER met2 ;
      RECT 513.290 0.000 513.430 0.420 ;
    END
  END rw0_rd_out[70]
  PIN rw0_rd_out[71]
    DIRECTION OUTPUT ;
    USE SIGNAL ;
    SHAPE ABUTMENT ;
    PORT
      LAYER met2 ;
      RECT 516.050 0.000 516.190 0.420 ;
    END
  END rw0_rd_out[71]
  PIN rw0_rd_out[72]
    DIRECTION OUTPUT ;
    USE SIGNAL ;
    SHAPE ABUTMENT ;
    PORT
      LAYER met2 ;
      RECT 518.810 0.000 518.950 0.420 ;
    END
  END rw0_rd_out[72]
  PIN rw0_rd_out[73]
    DIRECTION OUTPUT ;
    USE SIGNAL ;
    SHAPE ABUTMENT ;
    PORT
      LAYER met2 ;
      RECT 521.570 0.000 521.710 0.420 ;
    END
  END rw0_rd_out[73]
  PIN rw0_rd_out[74]
    DIRECTION OUTPUT ;
    USE SIGNAL ;
    SHAPE ABUTMENT ;
    PORT
      LAYER met2 ;
      RECT 524.330 0.000 524.470 0.420 ;
    END
  END rw0_rd_out[74]
  PIN rw0_rd_out[75]
    DIRECTION OUTPUT ;
    USE SIGNAL ;
    SHAPE ABUTMENT ;
    PORT
      LAYER met2 ;
      RECT 527.090 0.000 527.230 0.420 ;
    END
  END rw0_rd_out[75]
  PIN rw0_rd_out[76]
    DIRECTION OUTPUT ;
    USE SIGNAL ;
    SHAPE ABUTMENT ;
    PORT
      LAYER met2 ;
      RECT 529.850 0.000 529.990 0.420 ;
    END
  END rw0_rd_out[76]
  PIN rw0_rd_out[77]
    DIRECTION OUTPUT ;
    USE SIGNAL ;
    SHAPE ABUTMENT ;
    PORT
      LAYER met2 ;
      RECT 532.610 0.000 532.750 0.420 ;
    END
  END rw0_rd_out[77]
  PIN rw0_rd_out[78]
    DIRECTION OUTPUT ;
    USE SIGNAL ;
    SHAPE ABUTMENT ;
    PORT
      LAYER met2 ;
      RECT 535.370 0.000 535.510 0.420 ;
    END
  END rw0_rd_out[78]
  PIN rw0_rd_out[79]
    DIRECTION OUTPUT ;
    USE SIGNAL ;
    SHAPE ABUTMENT ;
    PORT
      LAYER met2 ;
      RECT 538.130 0.000 538.270 0.420 ;
    END
  END rw0_rd_out[79]
  PIN rw0_rd_out[80]
    DIRECTION OUTPUT ;
    USE SIGNAL ;
    SHAPE ABUTMENT ;
    PORT
      LAYER met2 ;
      RECT 540.890 0.000 541.030 0.420 ;
    END
  END rw0_rd_out[80]
  PIN rw0_rd_out[81]
    DIRECTION OUTPUT ;
    USE SIGNAL ;
    SHAPE ABUTMENT ;
    PORT
      LAYER met2 ;
      RECT 543.650 0.000 543.790 0.420 ;
    END
  END rw0_rd_out[81]
  PIN rw0_rd_out[82]
    DIRECTION OUTPUT ;
    USE SIGNAL ;
    SHAPE ABUTMENT ;
    PORT
      LAYER met2 ;
      RECT 546.410 0.000 546.550 0.420 ;
    END
  END rw0_rd_out[82]
  PIN rw0_rd_out[83]
    DIRECTION OUTPUT ;
    USE SIGNAL ;
    SHAPE ABUTMENT ;
    PORT
      LAYER met2 ;
      RECT 549.170 0.000 549.310 0.420 ;
    END
  END rw0_rd_out[83]
  PIN rw0_rd_out[84]
    DIRECTION OUTPUT ;
    USE SIGNAL ;
    SHAPE ABUTMENT ;
    PORT
      LAYER met2 ;
      RECT 551.930 0.000 552.070 0.420 ;
    END
  END rw0_rd_out[84]
  PIN rw0_rd_out[85]
    DIRECTION OUTPUT ;
    USE SIGNAL ;
    SHAPE ABUTMENT ;
    PORT
      LAYER met2 ;
      RECT 554.690 0.000 554.830 0.420 ;
    END
  END rw0_rd_out[85]
  PIN rw0_rd_out[86]
    DIRECTION OUTPUT ;
    USE SIGNAL ;
    SHAPE ABUTMENT ;
    PORT
      LAYER met2 ;
      RECT 557.450 0.000 557.590 0.420 ;
    END
  END rw0_rd_out[86]
  PIN rw0_rd_out[87]
    DIRECTION OUTPUT ;
    USE SIGNAL ;
    SHAPE ABUTMENT ;
    PORT
      LAYER met2 ;
      RECT 560.210 0.000 560.350 0.420 ;
    END
  END rw0_rd_out[87]
  PIN rw0_rd_out[88]
    DIRECTION OUTPUT ;
    USE SIGNAL ;
    SHAPE ABUTMENT ;
    PORT
      LAYER met2 ;
      RECT 562.970 0.000 563.110 0.420 ;
    END
  END rw0_rd_out[88]
  PIN rw0_rd_out[89]
    DIRECTION OUTPUT ;
    USE SIGNAL ;
    SHAPE ABUTMENT ;
    PORT
      LAYER met2 ;
      RECT 565.730 0.000 565.870 0.420 ;
    END
  END rw0_rd_out[89]
  PIN rw0_rd_out[90]
    DIRECTION OUTPUT ;
    USE SIGNAL ;
    SHAPE ABUTMENT ;
    PORT
      LAYER met2 ;
      RECT 568.490 0.000 568.630 0.420 ;
    END
  END rw0_rd_out[90]
  PIN rw0_rd_out[91]
    DIRECTION OUTPUT ;
    USE SIGNAL ;
    SHAPE ABUTMENT ;
    PORT
      LAYER met2 ;
      RECT 571.250 0.000 571.390 0.420 ;
    END
  END rw0_rd_out[91]
  PIN rw0_rd_out[92]
    DIRECTION OUTPUT ;
    USE SIGNAL ;
    SHAPE ABUTMENT ;
    PORT
      LAYER met2 ;
      RECT 574.010 0.000 574.150 0.420 ;
    END
  END rw0_rd_out[92]
  PIN rw0_rd_out[93]
    DIRECTION OUTPUT ;
    USE SIGNAL ;
    SHAPE ABUTMENT ;
    PORT
      LAYER met2 ;
      RECT 576.770 0.000 576.910 0.420 ;
    END
  END rw0_rd_out[93]
  PIN rw0_rd_out[94]
    DIRECTION OUTPUT ;
    USE SIGNAL ;
    SHAPE ABUTMENT ;
    PORT
      LAYER met2 ;
      RECT 579.530 0.000 579.670 0.420 ;
    END
  END rw0_rd_out[94]
  PIN rw0_rd_out[95]
    DIRECTION OUTPUT ;
    USE SIGNAL ;
    SHAPE ABUTMENT ;
    PORT
      LAYER met2 ;
      RECT 582.290 0.000 582.430 0.420 ;
    END
  END rw0_rd_out[95]
  PIN rw0_rd_out[96]
    DIRECTION OUTPUT ;
    USE SIGNAL ;
    SHAPE ABUTMENT ;
    PORT
      LAYER met2 ;
      RECT 585.050 0.000 585.190 0.420 ;
    END
  END rw0_rd_out[96]
  PIN rw0_rd_out[97]
    DIRECTION OUTPUT ;
    USE SIGNAL ;
    SHAPE ABUTMENT ;
    PORT
      LAYER met2 ;
      RECT 587.810 0.000 587.950 0.420 ;
    END
  END rw0_rd_out[97]
  PIN rw0_rd_out[98]
    DIRECTION OUTPUT ;
    USE SIGNAL ;
    SHAPE ABUTMENT ;
    PORT
      LAYER met2 ;
      RECT 590.570 0.000 590.710 0.420 ;
    END
  END rw0_rd_out[98]
  PIN rw0_rd_out[99]
    DIRECTION OUTPUT ;
    USE SIGNAL ;
    SHAPE ABUTMENT ;
    PORT
      LAYER met2 ;
      RECT 593.330 0.000 593.470 0.420 ;
    END
  END rw0_rd_out[99]
  PIN rw0_rd_out[100]
    DIRECTION OUTPUT ;
    USE SIGNAL ;
    SHAPE ABUTMENT ;
    PORT
      LAYER met2 ;
      RECT 596.090 0.000 596.230 0.420 ;
    END
  END rw0_rd_out[100]
  PIN rw0_rd_out[101]
    DIRECTION OUTPUT ;
    USE SIGNAL ;
    SHAPE ABUTMENT ;
    PORT
      LAYER met2 ;
      RECT 598.850 0.000 598.990 0.420 ;
    END
  END rw0_rd_out[101]
  PIN rw0_rd_out[102]
    DIRECTION OUTPUT ;
    USE SIGNAL ;
    SHAPE ABUTMENT ;
    PORT
      LAYER met2 ;
      RECT 601.610 0.000 601.750 0.420 ;
    END
  END rw0_rd_out[102]
  PIN rw0_rd_out[103]
    DIRECTION OUTPUT ;
    USE SIGNAL ;
    SHAPE ABUTMENT ;
    PORT
      LAYER met2 ;
      RECT 604.370 0.000 604.510 0.420 ;
    END
  END rw0_rd_out[103]
  PIN rw0_rd_out[104]
    DIRECTION OUTPUT ;
    USE SIGNAL ;
    SHAPE ABUTMENT ;
    PORT
      LAYER met2 ;
      RECT 607.130 0.000 607.270 0.420 ;
    END
  END rw0_rd_out[104]
  PIN rw0_rd_out[105]
    DIRECTION OUTPUT ;
    USE SIGNAL ;
    SHAPE ABUTMENT ;
    PORT
      LAYER met2 ;
      RECT 609.890 0.000 610.030 0.420 ;
    END
  END rw0_rd_out[105]
  PIN rw0_rd_out[106]
    DIRECTION OUTPUT ;
    USE SIGNAL ;
    SHAPE ABUTMENT ;
    PORT
      LAYER met2 ;
      RECT 612.650 0.000 612.790 0.420 ;
    END
  END rw0_rd_out[106]
  PIN rw0_rd_out[107]
    DIRECTION OUTPUT ;
    USE SIGNAL ;
    SHAPE ABUTMENT ;
    PORT
      LAYER met2 ;
      RECT 615.410 0.000 615.550 0.420 ;
    END
  END rw0_rd_out[107]
  PIN rw0_rd_out[108]
    DIRECTION OUTPUT ;
    USE SIGNAL ;
    SHAPE ABUTMENT ;
    PORT
      LAYER met2 ;
      RECT 618.170 0.000 618.310 0.420 ;
    END
  END rw0_rd_out[108]
  PIN rw0_rd_out[109]
    DIRECTION OUTPUT ;
    USE SIGNAL ;
    SHAPE ABUTMENT ;
    PORT
      LAYER met2 ;
      RECT 620.930 0.000 621.070 0.420 ;
    END
  END rw0_rd_out[109]
  PIN rw0_rd_out[110]
    DIRECTION OUTPUT ;
    USE SIGNAL ;
    SHAPE ABUTMENT ;
    PORT
      LAYER met2 ;
      RECT 623.690 0.000 623.830 0.420 ;
    END
  END rw0_rd_out[110]
  PIN rw0_rd_out[111]
    DIRECTION OUTPUT ;
    USE SIGNAL ;
    SHAPE ABUTMENT ;
    PORT
      LAYER met2 ;
      RECT 626.450 0.000 626.590 0.420 ;
    END
  END rw0_rd_out[111]
  PIN rw0_rd_out[112]
    DIRECTION OUTPUT ;
    USE SIGNAL ;
    SHAPE ABUTMENT ;
    PORT
      LAYER met2 ;
      RECT 629.210 0.000 629.350 0.420 ;
    END
  END rw0_rd_out[112]
  PIN rw0_rd_out[113]
    DIRECTION OUTPUT ;
    USE SIGNAL ;
    SHAPE ABUTMENT ;
    PORT
      LAYER met2 ;
      RECT 631.970 0.000 632.110 0.420 ;
    END
  END rw0_rd_out[113]
  PIN rw0_rd_out[114]
    DIRECTION OUTPUT ;
    USE SIGNAL ;
    SHAPE ABUTMENT ;
    PORT
      LAYER met2 ;
      RECT 634.730 0.000 634.870 0.420 ;
    END
  END rw0_rd_out[114]
  PIN rw0_rd_out[115]
    DIRECTION OUTPUT ;
    USE SIGNAL ;
    SHAPE ABUTMENT ;
    PORT
      LAYER met2 ;
      RECT 2.690 948.860 2.830 949.280 ;
    END
  END rw0_rd_out[115]
  PIN rw0_rd_out[116]
    DIRECTION OUTPUT ;
    USE SIGNAL ;
    SHAPE ABUTMENT ;
    PORT
      LAYER met2 ;
      RECT 6.830 948.860 6.970 949.280 ;
    END
  END rw0_rd_out[116]
  PIN rw0_rd_out[117]
    DIRECTION OUTPUT ;
    USE SIGNAL ;
    SHAPE ABUTMENT ;
    PORT
      LAYER met2 ;
      RECT 10.970 948.860 11.110 949.280 ;
    END
  END rw0_rd_out[117]
  PIN rw0_rd_out[118]
    DIRECTION OUTPUT ;
    USE SIGNAL ;
    SHAPE ABUTMENT ;
    PORT
      LAYER met2 ;
      RECT 15.110 948.860 15.250 949.280 ;
    END
  END rw0_rd_out[118]
  PIN rw0_rd_out[119]
    DIRECTION OUTPUT ;
    USE SIGNAL ;
    SHAPE ABUTMENT ;
    PORT
      LAYER met2 ;
      RECT 19.250 948.860 19.390 949.280 ;
    END
  END rw0_rd_out[119]
  PIN rw0_rd_out[120]
    DIRECTION OUTPUT ;
    USE SIGNAL ;
    SHAPE ABUTMENT ;
    PORT
      LAYER met2 ;
      RECT 23.390 948.860 23.530 949.280 ;
    END
  END rw0_rd_out[120]
  PIN rw0_rd_out[121]
    DIRECTION OUTPUT ;
    USE SIGNAL ;
    SHAPE ABUTMENT ;
    PORT
      LAYER met2 ;
      RECT 27.530 948.860 27.670 949.280 ;
    END
  END rw0_rd_out[121]
  PIN rw0_rd_out[122]
    DIRECTION OUTPUT ;
    USE SIGNAL ;
    SHAPE ABUTMENT ;
    PORT
      LAYER met2 ;
      RECT 31.670 948.860 31.810 949.280 ;
    END
  END rw0_rd_out[122]
  PIN rw0_rd_out[123]
    DIRECTION OUTPUT ;
    USE SIGNAL ;
    SHAPE ABUTMENT ;
    PORT
      LAYER met2 ;
      RECT 35.810 948.860 35.950 949.280 ;
    END
  END rw0_rd_out[123]
  PIN rw0_rd_out[124]
    DIRECTION OUTPUT ;
    USE SIGNAL ;
    SHAPE ABUTMENT ;
    PORT
      LAYER met2 ;
      RECT 39.950 948.860 40.090 949.280 ;
    END
  END rw0_rd_out[124]
  PIN rw0_rd_out[125]
    DIRECTION OUTPUT ;
    USE SIGNAL ;
    SHAPE ABUTMENT ;
    PORT
      LAYER met2 ;
      RECT 44.090 948.860 44.230 949.280 ;
    END
  END rw0_rd_out[125]
  PIN rw0_rd_out[126]
    DIRECTION OUTPUT ;
    USE SIGNAL ;
    SHAPE ABUTMENT ;
    PORT
      LAYER met2 ;
      RECT 48.230 948.860 48.370 949.280 ;
    END
  END rw0_rd_out[126]
  PIN rw0_rd_out[127]
    DIRECTION OUTPUT ;
    USE SIGNAL ;
    SHAPE ABUTMENT ;
    PORT
      LAYER met2 ;
      RECT 52.370 948.860 52.510 949.280 ;
    END
  END rw0_rd_out[127]
  PIN rw0_rd_out[128]
    DIRECTION OUTPUT ;
    USE SIGNAL ;
    SHAPE ABUTMENT ;
    PORT
      LAYER met2 ;
      RECT 56.510 948.860 56.650 949.280 ;
    END
  END rw0_rd_out[128]
  PIN rw0_rd_out[129]
    DIRECTION OUTPUT ;
    USE SIGNAL ;
    SHAPE ABUTMENT ;
    PORT
      LAYER met2 ;
      RECT 60.650 948.860 60.790 949.280 ;
    END
  END rw0_rd_out[129]
  PIN rw0_rd_out[130]
    DIRECTION OUTPUT ;
    USE SIGNAL ;
    SHAPE ABUTMENT ;
    PORT
      LAYER met2 ;
      RECT 64.790 948.860 64.930 949.280 ;
    END
  END rw0_rd_out[130]
  PIN rw0_rd_out[131]
    DIRECTION OUTPUT ;
    USE SIGNAL ;
    SHAPE ABUTMENT ;
    PORT
      LAYER met2 ;
      RECT 68.930 948.860 69.070 949.280 ;
    END
  END rw0_rd_out[131]
  PIN rw0_rd_out[132]
    DIRECTION OUTPUT ;
    USE SIGNAL ;
    SHAPE ABUTMENT ;
    PORT
      LAYER met2 ;
      RECT 73.070 948.860 73.210 949.280 ;
    END
  END rw0_rd_out[132]
  PIN rw0_rd_out[133]
    DIRECTION OUTPUT ;
    USE SIGNAL ;
    SHAPE ABUTMENT ;
    PORT
      LAYER met2 ;
      RECT 77.210 948.860 77.350 949.280 ;
    END
  END rw0_rd_out[133]
  PIN rw0_rd_out[134]
    DIRECTION OUTPUT ;
    USE SIGNAL ;
    SHAPE ABUTMENT ;
    PORT
      LAYER met2 ;
      RECT 81.350 948.860 81.490 949.280 ;
    END
  END rw0_rd_out[134]
  PIN rw0_rd_out[135]
    DIRECTION OUTPUT ;
    USE SIGNAL ;
    SHAPE ABUTMENT ;
    PORT
      LAYER met2 ;
      RECT 85.490 948.860 85.630 949.280 ;
    END
  END rw0_rd_out[135]
  PIN rw0_rd_out[136]
    DIRECTION OUTPUT ;
    USE SIGNAL ;
    SHAPE ABUTMENT ;
    PORT
      LAYER met2 ;
      RECT 89.630 948.860 89.770 949.280 ;
    END
  END rw0_rd_out[136]
  PIN rw0_rd_out[137]
    DIRECTION OUTPUT ;
    USE SIGNAL ;
    SHAPE ABUTMENT ;
    PORT
      LAYER met2 ;
      RECT 93.770 948.860 93.910 949.280 ;
    END
  END rw0_rd_out[137]
  PIN rw0_rd_out[138]
    DIRECTION OUTPUT ;
    USE SIGNAL ;
    SHAPE ABUTMENT ;
    PORT
      LAYER met2 ;
      RECT 97.910 948.860 98.050 949.280 ;
    END
  END rw0_rd_out[138]
  PIN rw0_rd_out[139]
    DIRECTION OUTPUT ;
    USE SIGNAL ;
    SHAPE ABUTMENT ;
    PORT
      LAYER met2 ;
      RECT 102.050 948.860 102.190 949.280 ;
    END
  END rw0_rd_out[139]
  PIN rw0_rd_out[140]
    DIRECTION OUTPUT ;
    USE SIGNAL ;
    SHAPE ABUTMENT ;
    PORT
      LAYER met2 ;
      RECT 106.190 948.860 106.330 949.280 ;
    END
  END rw0_rd_out[140]
  PIN rw0_rd_out[141]
    DIRECTION OUTPUT ;
    USE SIGNAL ;
    SHAPE ABUTMENT ;
    PORT
      LAYER met2 ;
      RECT 110.330 948.860 110.470 949.280 ;
    END
  END rw0_rd_out[141]
  PIN rw0_rd_out[142]
    DIRECTION OUTPUT ;
    USE SIGNAL ;
    SHAPE ABUTMENT ;
    PORT
      LAYER met2 ;
      RECT 114.470 948.860 114.610 949.280 ;
    END
  END rw0_rd_out[142]
  PIN rw0_rd_out[143]
    DIRECTION OUTPUT ;
    USE SIGNAL ;
    SHAPE ABUTMENT ;
    PORT
      LAYER met2 ;
      RECT 118.610 948.860 118.750 949.280 ;
    END
  END rw0_rd_out[143]
  PIN rw0_rd_out[144]
    DIRECTION OUTPUT ;
    USE SIGNAL ;
    SHAPE ABUTMENT ;
    PORT
      LAYER met2 ;
      RECT 122.750 948.860 122.890 949.280 ;
    END
  END rw0_rd_out[144]
  PIN rw0_rd_out[145]
    DIRECTION OUTPUT ;
    USE SIGNAL ;
    SHAPE ABUTMENT ;
    PORT
      LAYER met2 ;
      RECT 126.890 948.860 127.030 949.280 ;
    END
  END rw0_rd_out[145]
  PIN rw0_rd_out[146]
    DIRECTION OUTPUT ;
    USE SIGNAL ;
    SHAPE ABUTMENT ;
    PORT
      LAYER met2 ;
      RECT 131.030 948.860 131.170 949.280 ;
    END
  END rw0_rd_out[146]
  PIN rw0_rd_out[147]
    DIRECTION OUTPUT ;
    USE SIGNAL ;
    SHAPE ABUTMENT ;
    PORT
      LAYER met2 ;
      RECT 135.170 948.860 135.310 949.280 ;
    END
  END rw0_rd_out[147]
  PIN rw0_rd_out[148]
    DIRECTION OUTPUT ;
    USE SIGNAL ;
    SHAPE ABUTMENT ;
    PORT
      LAYER met2 ;
      RECT 139.310 948.860 139.450 949.280 ;
    END
  END rw0_rd_out[148]
  PIN rw0_rd_out[149]
    DIRECTION OUTPUT ;
    USE SIGNAL ;
    SHAPE ABUTMENT ;
    PORT
      LAYER met2 ;
      RECT 143.450 948.860 143.590 949.280 ;
    END
  END rw0_rd_out[149]
  PIN rw0_rd_out[150]
    DIRECTION OUTPUT ;
    USE SIGNAL ;
    SHAPE ABUTMENT ;
    PORT
      LAYER met2 ;
      RECT 147.590 948.860 147.730 949.280 ;
    END
  END rw0_rd_out[150]
  PIN rw0_rd_out[151]
    DIRECTION OUTPUT ;
    USE SIGNAL ;
    SHAPE ABUTMENT ;
    PORT
      LAYER met2 ;
      RECT 151.730 948.860 151.870 949.280 ;
    END
  END rw0_rd_out[151]
  PIN rw0_rd_out[152]
    DIRECTION OUTPUT ;
    USE SIGNAL ;
    SHAPE ABUTMENT ;
    PORT
      LAYER met2 ;
      RECT 155.870 948.860 156.010 949.280 ;
    END
  END rw0_rd_out[152]
  PIN rw0_rd_out[153]
    DIRECTION OUTPUT ;
    USE SIGNAL ;
    SHAPE ABUTMENT ;
    PORT
      LAYER met2 ;
      RECT 160.010 948.860 160.150 949.280 ;
    END
  END rw0_rd_out[153]
  PIN rw0_rd_out[154]
    DIRECTION OUTPUT ;
    USE SIGNAL ;
    SHAPE ABUTMENT ;
    PORT
      LAYER met2 ;
      RECT 164.150 948.860 164.290 949.280 ;
    END
  END rw0_rd_out[154]
  PIN rw0_rd_out[155]
    DIRECTION OUTPUT ;
    USE SIGNAL ;
    SHAPE ABUTMENT ;
    PORT
      LAYER met2 ;
      RECT 168.290 948.860 168.430 949.280 ;
    END
  END rw0_rd_out[155]
  PIN rw0_rd_out[156]
    DIRECTION OUTPUT ;
    USE SIGNAL ;
    SHAPE ABUTMENT ;
    PORT
      LAYER met2 ;
      RECT 172.430 948.860 172.570 949.280 ;
    END
  END rw0_rd_out[156]
  PIN rw0_rd_out[157]
    DIRECTION OUTPUT ;
    USE SIGNAL ;
    SHAPE ABUTMENT ;
    PORT
      LAYER met2 ;
      RECT 176.570 948.860 176.710 949.280 ;
    END
  END rw0_rd_out[157]
  PIN rw0_rd_out[158]
    DIRECTION OUTPUT ;
    USE SIGNAL ;
    SHAPE ABUTMENT ;
    PORT
      LAYER met2 ;
      RECT 180.710 948.860 180.850 949.280 ;
    END
  END rw0_rd_out[158]
  PIN rw0_rd_out[159]
    DIRECTION OUTPUT ;
    USE SIGNAL ;
    SHAPE ABUTMENT ;
    PORT
      LAYER met2 ;
      RECT 184.850 948.860 184.990 949.280 ;
    END
  END rw0_rd_out[159]
  PIN rw0_rd_out[160]
    DIRECTION OUTPUT ;
    USE SIGNAL ;
    SHAPE ABUTMENT ;
    PORT
      LAYER met2 ;
      RECT 188.990 948.860 189.130 949.280 ;
    END
  END rw0_rd_out[160]
  PIN rw0_rd_out[161]
    DIRECTION OUTPUT ;
    USE SIGNAL ;
    SHAPE ABUTMENT ;
    PORT
      LAYER met2 ;
      RECT 193.130 948.860 193.270 949.280 ;
    END
  END rw0_rd_out[161]
  PIN rw0_rd_out[162]
    DIRECTION OUTPUT ;
    USE SIGNAL ;
    SHAPE ABUTMENT ;
    PORT
      LAYER met2 ;
      RECT 197.270 948.860 197.410 949.280 ;
    END
  END rw0_rd_out[162]
  PIN rw0_rd_out[163]
    DIRECTION OUTPUT ;
    USE SIGNAL ;
    SHAPE ABUTMENT ;
    PORT
      LAYER met2 ;
      RECT 201.410 948.860 201.550 949.280 ;
    END
  END rw0_rd_out[163]
  PIN rw0_rd_out[164]
    DIRECTION OUTPUT ;
    USE SIGNAL ;
    SHAPE ABUTMENT ;
    PORT
      LAYER met2 ;
      RECT 205.550 948.860 205.690 949.280 ;
    END
  END rw0_rd_out[164]
  PIN rw0_rd_out[165]
    DIRECTION OUTPUT ;
    USE SIGNAL ;
    SHAPE ABUTMENT ;
    PORT
      LAYER met2 ;
      RECT 209.690 948.860 209.830 949.280 ;
    END
  END rw0_rd_out[165]
  PIN rw0_rd_out[166]
    DIRECTION OUTPUT ;
    USE SIGNAL ;
    SHAPE ABUTMENT ;
    PORT
      LAYER met2 ;
      RECT 213.830 948.860 213.970 949.280 ;
    END
  END rw0_rd_out[166]
  PIN rw0_rd_out[167]
    DIRECTION OUTPUT ;
    USE SIGNAL ;
    SHAPE ABUTMENT ;
    PORT
      LAYER met2 ;
      RECT 217.970 948.860 218.110 949.280 ;
    END
  END rw0_rd_out[167]
  PIN rw0_rd_out[168]
    DIRECTION OUTPUT ;
    USE SIGNAL ;
    SHAPE ABUTMENT ;
    PORT
      LAYER met2 ;
      RECT 222.110 948.860 222.250 949.280 ;
    END
  END rw0_rd_out[168]
  PIN rw0_rd_out[169]
    DIRECTION OUTPUT ;
    USE SIGNAL ;
    SHAPE ABUTMENT ;
    PORT
      LAYER met2 ;
      RECT 226.250 948.860 226.390 949.280 ;
    END
  END rw0_rd_out[169]
  PIN rw0_rd_out[170]
    DIRECTION OUTPUT ;
    USE SIGNAL ;
    SHAPE ABUTMENT ;
    PORT
      LAYER met2 ;
      RECT 230.390 948.860 230.530 949.280 ;
    END
  END rw0_rd_out[170]
  PIN rw0_rd_out[171]
    DIRECTION OUTPUT ;
    USE SIGNAL ;
    SHAPE ABUTMENT ;
    PORT
      LAYER met2 ;
      RECT 234.530 948.860 234.670 949.280 ;
    END
  END rw0_rd_out[171]
  PIN rw0_rd_out[172]
    DIRECTION OUTPUT ;
    USE SIGNAL ;
    SHAPE ABUTMENT ;
    PORT
      LAYER met2 ;
      RECT 238.670 948.860 238.810 949.280 ;
    END
  END rw0_rd_out[172]
  PIN rw0_rd_out[173]
    DIRECTION OUTPUT ;
    USE SIGNAL ;
    SHAPE ABUTMENT ;
    PORT
      LAYER met2 ;
      RECT 242.810 948.860 242.950 949.280 ;
    END
  END rw0_rd_out[173]
  PIN rw0_rd_out[174]
    DIRECTION OUTPUT ;
    USE SIGNAL ;
    SHAPE ABUTMENT ;
    PORT
      LAYER met2 ;
      RECT 246.950 948.860 247.090 949.280 ;
    END
  END rw0_rd_out[174]
  PIN rw0_rd_out[175]
    DIRECTION OUTPUT ;
    USE SIGNAL ;
    SHAPE ABUTMENT ;
    PORT
      LAYER met2 ;
      RECT 251.090 948.860 251.230 949.280 ;
    END
  END rw0_rd_out[175]
  PIN rw0_rd_out[176]
    DIRECTION OUTPUT ;
    USE SIGNAL ;
    SHAPE ABUTMENT ;
    PORT
      LAYER met2 ;
      RECT 255.230 948.860 255.370 949.280 ;
    END
  END rw0_rd_out[176]
  PIN rw0_rd_out[177]
    DIRECTION OUTPUT ;
    USE SIGNAL ;
    SHAPE ABUTMENT ;
    PORT
      LAYER met2 ;
      RECT 259.370 948.860 259.510 949.280 ;
    END
  END rw0_rd_out[177]
  PIN rw0_rd_out[178]
    DIRECTION OUTPUT ;
    USE SIGNAL ;
    SHAPE ABUTMENT ;
    PORT
      LAYER met2 ;
      RECT 263.510 948.860 263.650 949.280 ;
    END
  END rw0_rd_out[178]
  PIN rw0_rd_out[179]
    DIRECTION OUTPUT ;
    USE SIGNAL ;
    SHAPE ABUTMENT ;
    PORT
      LAYER met2 ;
      RECT 267.650 948.860 267.790 949.280 ;
    END
  END rw0_rd_out[179]
  PIN rw0_rd_out[180]
    DIRECTION OUTPUT ;
    USE SIGNAL ;
    SHAPE ABUTMENT ;
    PORT
      LAYER met2 ;
      RECT 271.790 948.860 271.930 949.280 ;
    END
  END rw0_rd_out[180]
  PIN rw0_rd_out[181]
    DIRECTION OUTPUT ;
    USE SIGNAL ;
    SHAPE ABUTMENT ;
    PORT
      LAYER met2 ;
      RECT 275.930 948.860 276.070 949.280 ;
    END
  END rw0_rd_out[181]
  PIN rw0_rd_out[182]
    DIRECTION OUTPUT ;
    USE SIGNAL ;
    SHAPE ABUTMENT ;
    PORT
      LAYER met2 ;
      RECT 280.070 948.860 280.210 949.280 ;
    END
  END rw0_rd_out[182]
  PIN rw0_rd_out[183]
    DIRECTION OUTPUT ;
    USE SIGNAL ;
    SHAPE ABUTMENT ;
    PORT
      LAYER met2 ;
      RECT 284.210 948.860 284.350 949.280 ;
    END
  END rw0_rd_out[183]
  PIN rw0_rd_out[184]
    DIRECTION OUTPUT ;
    USE SIGNAL ;
    SHAPE ABUTMENT ;
    PORT
      LAYER met2 ;
      RECT 288.350 948.860 288.490 949.280 ;
    END
  END rw0_rd_out[184]
  PIN rw0_rd_out[185]
    DIRECTION OUTPUT ;
    USE SIGNAL ;
    SHAPE ABUTMENT ;
    PORT
      LAYER met2 ;
      RECT 292.490 948.860 292.630 949.280 ;
    END
  END rw0_rd_out[185]
  PIN rw0_rd_out[186]
    DIRECTION OUTPUT ;
    USE SIGNAL ;
    SHAPE ABUTMENT ;
    PORT
      LAYER met2 ;
      RECT 296.630 948.860 296.770 949.280 ;
    END
  END rw0_rd_out[186]
  PIN rw0_rd_out[187]
    DIRECTION OUTPUT ;
    USE SIGNAL ;
    SHAPE ABUTMENT ;
    PORT
      LAYER met2 ;
      RECT 300.770 948.860 300.910 949.280 ;
    END
  END rw0_rd_out[187]
  PIN rw0_rd_out[188]
    DIRECTION OUTPUT ;
    USE SIGNAL ;
    SHAPE ABUTMENT ;
    PORT
      LAYER met2 ;
      RECT 304.910 948.860 305.050 949.280 ;
    END
  END rw0_rd_out[188]
  PIN rw0_rd_out[189]
    DIRECTION OUTPUT ;
    USE SIGNAL ;
    SHAPE ABUTMENT ;
    PORT
      LAYER met2 ;
      RECT 309.050 948.860 309.190 949.280 ;
    END
  END rw0_rd_out[189]
  PIN rw0_rd_out[190]
    DIRECTION OUTPUT ;
    USE SIGNAL ;
    SHAPE ABUTMENT ;
    PORT
      LAYER met2 ;
      RECT 313.190 948.860 313.330 949.280 ;
    END
  END rw0_rd_out[190]
  PIN rw0_rd_out[191]
    DIRECTION OUTPUT ;
    USE SIGNAL ;
    SHAPE ABUTMENT ;
    PORT
      LAYER met2 ;
      RECT 317.330 948.860 317.470 949.280 ;
    END
  END rw0_rd_out[191]
  PIN rw0_rd_out[192]
    DIRECTION OUTPUT ;
    USE SIGNAL ;
    SHAPE ABUTMENT ;
    PORT
      LAYER met2 ;
      RECT 321.470 948.860 321.610 949.280 ;
    END
  END rw0_rd_out[192]
  PIN rw0_rd_out[193]
    DIRECTION OUTPUT ;
    USE SIGNAL ;
    SHAPE ABUTMENT ;
    PORT
      LAYER met2 ;
      RECT 325.610 948.860 325.750 949.280 ;
    END
  END rw0_rd_out[193]
  PIN rw0_rd_out[194]
    DIRECTION OUTPUT ;
    USE SIGNAL ;
    SHAPE ABUTMENT ;
    PORT
      LAYER met2 ;
      RECT 329.750 948.860 329.890 949.280 ;
    END
  END rw0_rd_out[194]
  PIN rw0_rd_out[195]
    DIRECTION OUTPUT ;
    USE SIGNAL ;
    SHAPE ABUTMENT ;
    PORT
      LAYER met2 ;
      RECT 333.890 948.860 334.030 949.280 ;
    END
  END rw0_rd_out[195]
  PIN rw0_rd_out[196]
    DIRECTION OUTPUT ;
    USE SIGNAL ;
    SHAPE ABUTMENT ;
    PORT
      LAYER met2 ;
      RECT 338.030 948.860 338.170 949.280 ;
    END
  END rw0_rd_out[196]
  PIN rw0_rd_out[197]
    DIRECTION OUTPUT ;
    USE SIGNAL ;
    SHAPE ABUTMENT ;
    PORT
      LAYER met2 ;
      RECT 342.170 948.860 342.310 949.280 ;
    END
  END rw0_rd_out[197]
  PIN rw0_rd_out[198]
    DIRECTION OUTPUT ;
    USE SIGNAL ;
    SHAPE ABUTMENT ;
    PORT
      LAYER met2 ;
      RECT 346.310 948.860 346.450 949.280 ;
    END
  END rw0_rd_out[198]
  PIN rw0_rd_out[199]
    DIRECTION OUTPUT ;
    USE SIGNAL ;
    SHAPE ABUTMENT ;
    PORT
      LAYER met2 ;
      RECT 350.450 948.860 350.590 949.280 ;
    END
  END rw0_rd_out[199]
  PIN rw0_rd_out[200]
    DIRECTION OUTPUT ;
    USE SIGNAL ;
    SHAPE ABUTMENT ;
    PORT
      LAYER met2 ;
      RECT 354.590 948.860 354.730 949.280 ;
    END
  END rw0_rd_out[200]
  PIN rw0_rd_out[201]
    DIRECTION OUTPUT ;
    USE SIGNAL ;
    SHAPE ABUTMENT ;
    PORT
      LAYER met2 ;
      RECT 358.730 948.860 358.870 949.280 ;
    END
  END rw0_rd_out[201]
  PIN rw0_rd_out[202]
    DIRECTION OUTPUT ;
    USE SIGNAL ;
    SHAPE ABUTMENT ;
    PORT
      LAYER met2 ;
      RECT 362.870 948.860 363.010 949.280 ;
    END
  END rw0_rd_out[202]
  PIN rw0_rd_out[203]
    DIRECTION OUTPUT ;
    USE SIGNAL ;
    SHAPE ABUTMENT ;
    PORT
      LAYER met2 ;
      RECT 367.010 948.860 367.150 949.280 ;
    END
  END rw0_rd_out[203]
  PIN rw0_rd_out[204]
    DIRECTION OUTPUT ;
    USE SIGNAL ;
    SHAPE ABUTMENT ;
    PORT
      LAYER met2 ;
      RECT 371.150 948.860 371.290 949.280 ;
    END
  END rw0_rd_out[204]
  PIN rw0_rd_out[205]
    DIRECTION OUTPUT ;
    USE SIGNAL ;
    SHAPE ABUTMENT ;
    PORT
      LAYER met2 ;
      RECT 375.290 948.860 375.430 949.280 ;
    END
  END rw0_rd_out[205]
  PIN rw0_rd_out[206]
    DIRECTION OUTPUT ;
    USE SIGNAL ;
    SHAPE ABUTMENT ;
    PORT
      LAYER met2 ;
      RECT 379.430 948.860 379.570 949.280 ;
    END
  END rw0_rd_out[206]
  PIN rw0_rd_out[207]
    DIRECTION OUTPUT ;
    USE SIGNAL ;
    SHAPE ABUTMENT ;
    PORT
      LAYER met2 ;
      RECT 383.570 948.860 383.710 949.280 ;
    END
  END rw0_rd_out[207]
  PIN rw0_rd_out[208]
    DIRECTION OUTPUT ;
    USE SIGNAL ;
    SHAPE ABUTMENT ;
    PORT
      LAYER met2 ;
      RECT 387.710 948.860 387.850 949.280 ;
    END
  END rw0_rd_out[208]
  PIN rw0_rd_out[209]
    DIRECTION OUTPUT ;
    USE SIGNAL ;
    SHAPE ABUTMENT ;
    PORT
      LAYER met2 ;
      RECT 391.850 948.860 391.990 949.280 ;
    END
  END rw0_rd_out[209]
  PIN rw0_rd_out[210]
    DIRECTION OUTPUT ;
    USE SIGNAL ;
    SHAPE ABUTMENT ;
    PORT
      LAYER met2 ;
      RECT 395.990 948.860 396.130 949.280 ;
    END
  END rw0_rd_out[210]
  PIN rw0_rd_out[211]
    DIRECTION OUTPUT ;
    USE SIGNAL ;
    SHAPE ABUTMENT ;
    PORT
      LAYER met2 ;
      RECT 400.130 948.860 400.270 949.280 ;
    END
  END rw0_rd_out[211]
  PIN rw0_rd_out[212]
    DIRECTION OUTPUT ;
    USE SIGNAL ;
    SHAPE ABUTMENT ;
    PORT
      LAYER met2 ;
      RECT 404.270 948.860 404.410 949.280 ;
    END
  END rw0_rd_out[212]
  PIN rw0_rd_out[213]
    DIRECTION OUTPUT ;
    USE SIGNAL ;
    SHAPE ABUTMENT ;
    PORT
      LAYER met2 ;
      RECT 408.410 948.860 408.550 949.280 ;
    END
  END rw0_rd_out[213]
  PIN rw0_rd_out[214]
    DIRECTION OUTPUT ;
    USE SIGNAL ;
    SHAPE ABUTMENT ;
    PORT
      LAYER met2 ;
      RECT 412.550 948.860 412.690 949.280 ;
    END
  END rw0_rd_out[214]
  PIN rw0_rd_out[215]
    DIRECTION OUTPUT ;
    USE SIGNAL ;
    SHAPE ABUTMENT ;
    PORT
      LAYER met2 ;
      RECT 416.690 948.860 416.830 949.280 ;
    END
  END rw0_rd_out[215]
  PIN rw0_rd_out[216]
    DIRECTION OUTPUT ;
    USE SIGNAL ;
    SHAPE ABUTMENT ;
    PORT
      LAYER met2 ;
      RECT 420.830 948.860 420.970 949.280 ;
    END
  END rw0_rd_out[216]
  PIN rw0_rd_out[217]
    DIRECTION OUTPUT ;
    USE SIGNAL ;
    SHAPE ABUTMENT ;
    PORT
      LAYER met2 ;
      RECT 424.970 948.860 425.110 949.280 ;
    END
  END rw0_rd_out[217]
  PIN rw0_rd_out[218]
    DIRECTION OUTPUT ;
    USE SIGNAL ;
    SHAPE ABUTMENT ;
    PORT
      LAYER met2 ;
      RECT 429.110 948.860 429.250 949.280 ;
    END
  END rw0_rd_out[218]
  PIN rw0_rd_out[219]
    DIRECTION OUTPUT ;
    USE SIGNAL ;
    SHAPE ABUTMENT ;
    PORT
      LAYER met2 ;
      RECT 433.250 948.860 433.390 949.280 ;
    END
  END rw0_rd_out[219]
  PIN rw0_rd_out[220]
    DIRECTION OUTPUT ;
    USE SIGNAL ;
    SHAPE ABUTMENT ;
    PORT
      LAYER met2 ;
      RECT 437.390 948.860 437.530 949.280 ;
    END
  END rw0_rd_out[220]
  PIN rw0_rd_out[221]
    DIRECTION OUTPUT ;
    USE SIGNAL ;
    SHAPE ABUTMENT ;
    PORT
      LAYER met2 ;
      RECT 441.530 948.860 441.670 949.280 ;
    END
  END rw0_rd_out[221]
  PIN rw0_rd_out[222]
    DIRECTION OUTPUT ;
    USE SIGNAL ;
    SHAPE ABUTMENT ;
    PORT
      LAYER met2 ;
      RECT 445.670 948.860 445.810 949.280 ;
    END
  END rw0_rd_out[222]
  PIN rw0_rd_out[223]
    DIRECTION OUTPUT ;
    USE SIGNAL ;
    SHAPE ABUTMENT ;
    PORT
      LAYER met2 ;
      RECT 449.810 948.860 449.950 949.280 ;
    END
  END rw0_rd_out[223]
  PIN rw0_rd_out[224]
    DIRECTION OUTPUT ;
    USE SIGNAL ;
    SHAPE ABUTMENT ;
    PORT
      LAYER met2 ;
      RECT 453.950 948.860 454.090 949.280 ;
    END
  END rw0_rd_out[224]
  PIN rw0_rd_out[225]
    DIRECTION OUTPUT ;
    USE SIGNAL ;
    SHAPE ABUTMENT ;
    PORT
      LAYER met2 ;
      RECT 458.090 948.860 458.230 949.280 ;
    END
  END rw0_rd_out[225]
  PIN rw0_rd_out[226]
    DIRECTION OUTPUT ;
    USE SIGNAL ;
    SHAPE ABUTMENT ;
    PORT
      LAYER met2 ;
      RECT 462.230 948.860 462.370 949.280 ;
    END
  END rw0_rd_out[226]
  PIN rw0_rd_out[227]
    DIRECTION OUTPUT ;
    USE SIGNAL ;
    SHAPE ABUTMENT ;
    PORT
      LAYER met2 ;
      RECT 466.370 948.860 466.510 949.280 ;
    END
  END rw0_rd_out[227]
  PIN rw0_rd_out[228]
    DIRECTION OUTPUT ;
    USE SIGNAL ;
    SHAPE ABUTMENT ;
    PORT
      LAYER met2 ;
      RECT 470.510 948.860 470.650 949.280 ;
    END
  END rw0_rd_out[228]
  PIN rw0_rd_out[229]
    DIRECTION OUTPUT ;
    USE SIGNAL ;
    SHAPE ABUTMENT ;
    PORT
      LAYER met2 ;
      RECT 474.650 948.860 474.790 949.280 ;
    END
  END rw0_rd_out[229]
  PIN r0_rd_out[0]
    DIRECTION OUTPUT ;
    USE SIGNAL ;
    SHAPE ABUTMENT ;
    PORT
      LAYER met2 ;
      RECT 637.490 0.000 637.630 0.420 ;
    END
  END r0_rd_out[0]
  PIN r0_rd_out[1]
    DIRECTION OUTPUT ;
    USE SIGNAL ;
    SHAPE ABUTMENT ;
    PORT
      LAYER met2 ;
      RECT 640.250 0.000 640.390 0.420 ;
    END
  END r0_rd_out[1]
  PIN r0_rd_out[2]
    DIRECTION OUTPUT ;
    USE SIGNAL ;
    SHAPE ABUTMENT ;
    PORT
      LAYER met2 ;
      RECT 643.010 0.000 643.150 0.420 ;
    END
  END r0_rd_out[2]
  PIN r0_rd_out[3]
    DIRECTION OUTPUT ;
    USE SIGNAL ;
    SHAPE ABUTMENT ;
    PORT
      LAYER met2 ;
      RECT 645.770 0.000 645.910 0.420 ;
    END
  END r0_rd_out[3]
  PIN r0_rd_out[4]
    DIRECTION OUTPUT ;
    USE SIGNAL ;
    SHAPE ABUTMENT ;
    PORT
      LAYER met2 ;
      RECT 648.530 0.000 648.670 0.420 ;
    END
  END r0_rd_out[4]
  PIN r0_rd_out[5]
    DIRECTION OUTPUT ;
    USE SIGNAL ;
    SHAPE ABUTMENT ;
    PORT
      LAYER met2 ;
      RECT 651.290 0.000 651.430 0.420 ;
    END
  END r0_rd_out[5]
  PIN r0_rd_out[6]
    DIRECTION OUTPUT ;
    USE SIGNAL ;
    SHAPE ABUTMENT ;
    PORT
      LAYER met2 ;
      RECT 654.050 0.000 654.190 0.420 ;
    END
  END r0_rd_out[6]
  PIN r0_rd_out[7]
    DIRECTION OUTPUT ;
    USE SIGNAL ;
    SHAPE ABUTMENT ;
    PORT
      LAYER met2 ;
      RECT 656.810 0.000 656.950 0.420 ;
    END
  END r0_rd_out[7]
  PIN r0_rd_out[8]
    DIRECTION OUTPUT ;
    USE SIGNAL ;
    SHAPE ABUTMENT ;
    PORT
      LAYER met2 ;
      RECT 659.570 0.000 659.710 0.420 ;
    END
  END r0_rd_out[8]
  PIN r0_rd_out[9]
    DIRECTION OUTPUT ;
    USE SIGNAL ;
    SHAPE ABUTMENT ;
    PORT
      LAYER met2 ;
      RECT 662.330 0.000 662.470 0.420 ;
    END
  END r0_rd_out[9]
  PIN r0_rd_out[10]
    DIRECTION OUTPUT ;
    USE SIGNAL ;
    SHAPE ABUTMENT ;
    PORT
      LAYER met2 ;
      RECT 665.090 0.000 665.230 0.420 ;
    END
  END r0_rd_out[10]
  PIN r0_rd_out[11]
    DIRECTION OUTPUT ;
    USE SIGNAL ;
    SHAPE ABUTMENT ;
    PORT
      LAYER met2 ;
      RECT 667.850 0.000 667.990 0.420 ;
    END
  END r0_rd_out[11]
  PIN r0_rd_out[12]
    DIRECTION OUTPUT ;
    USE SIGNAL ;
    SHAPE ABUTMENT ;
    PORT
      LAYER met2 ;
      RECT 670.610 0.000 670.750 0.420 ;
    END
  END r0_rd_out[12]
  PIN r0_rd_out[13]
    DIRECTION OUTPUT ;
    USE SIGNAL ;
    SHAPE ABUTMENT ;
    PORT
      LAYER met2 ;
      RECT 673.370 0.000 673.510 0.420 ;
    END
  END r0_rd_out[13]
  PIN r0_rd_out[14]
    DIRECTION OUTPUT ;
    USE SIGNAL ;
    SHAPE ABUTMENT ;
    PORT
      LAYER met2 ;
      RECT 676.130 0.000 676.270 0.420 ;
    END
  END r0_rd_out[14]
  PIN r0_rd_out[15]
    DIRECTION OUTPUT ;
    USE SIGNAL ;
    SHAPE ABUTMENT ;
    PORT
      LAYER met2 ;
      RECT 678.890 0.000 679.030 0.420 ;
    END
  END r0_rd_out[15]
  PIN r0_rd_out[16]
    DIRECTION OUTPUT ;
    USE SIGNAL ;
    SHAPE ABUTMENT ;
    PORT
      LAYER met2 ;
      RECT 681.650 0.000 681.790 0.420 ;
    END
  END r0_rd_out[16]
  PIN r0_rd_out[17]
    DIRECTION OUTPUT ;
    USE SIGNAL ;
    SHAPE ABUTMENT ;
    PORT
      LAYER met2 ;
      RECT 684.410 0.000 684.550 0.420 ;
    END
  END r0_rd_out[17]
  PIN r0_rd_out[18]
    DIRECTION OUTPUT ;
    USE SIGNAL ;
    SHAPE ABUTMENT ;
    PORT
      LAYER met2 ;
      RECT 687.170 0.000 687.310 0.420 ;
    END
  END r0_rd_out[18]
  PIN r0_rd_out[19]
    DIRECTION OUTPUT ;
    USE SIGNAL ;
    SHAPE ABUTMENT ;
    PORT
      LAYER met2 ;
      RECT 689.930 0.000 690.070 0.420 ;
    END
  END r0_rd_out[19]
  PIN r0_rd_out[20]
    DIRECTION OUTPUT ;
    USE SIGNAL ;
    SHAPE ABUTMENT ;
    PORT
      LAYER met2 ;
      RECT 692.690 0.000 692.830 0.420 ;
    END
  END r0_rd_out[20]
  PIN r0_rd_out[21]
    DIRECTION OUTPUT ;
    USE SIGNAL ;
    SHAPE ABUTMENT ;
    PORT
      LAYER met2 ;
      RECT 695.450 0.000 695.590 0.420 ;
    END
  END r0_rd_out[21]
  PIN r0_rd_out[22]
    DIRECTION OUTPUT ;
    USE SIGNAL ;
    SHAPE ABUTMENT ;
    PORT
      LAYER met2 ;
      RECT 698.210 0.000 698.350 0.420 ;
    END
  END r0_rd_out[22]
  PIN r0_rd_out[23]
    DIRECTION OUTPUT ;
    USE SIGNAL ;
    SHAPE ABUTMENT ;
    PORT
      LAYER met2 ;
      RECT 700.970 0.000 701.110 0.420 ;
    END
  END r0_rd_out[23]
  PIN r0_rd_out[24]
    DIRECTION OUTPUT ;
    USE SIGNAL ;
    SHAPE ABUTMENT ;
    PORT
      LAYER met2 ;
      RECT 703.730 0.000 703.870 0.420 ;
    END
  END r0_rd_out[24]
  PIN r0_rd_out[25]
    DIRECTION OUTPUT ;
    USE SIGNAL ;
    SHAPE ABUTMENT ;
    PORT
      LAYER met2 ;
      RECT 706.490 0.000 706.630 0.420 ;
    END
  END r0_rd_out[25]
  PIN r0_rd_out[26]
    DIRECTION OUTPUT ;
    USE SIGNAL ;
    SHAPE ABUTMENT ;
    PORT
      LAYER met2 ;
      RECT 709.250 0.000 709.390 0.420 ;
    END
  END r0_rd_out[26]
  PIN r0_rd_out[27]
    DIRECTION OUTPUT ;
    USE SIGNAL ;
    SHAPE ABUTMENT ;
    PORT
      LAYER met2 ;
      RECT 712.010 0.000 712.150 0.420 ;
    END
  END r0_rd_out[27]
  PIN r0_rd_out[28]
    DIRECTION OUTPUT ;
    USE SIGNAL ;
    SHAPE ABUTMENT ;
    PORT
      LAYER met2 ;
      RECT 714.770 0.000 714.910 0.420 ;
    END
  END r0_rd_out[28]
  PIN r0_rd_out[29]
    DIRECTION OUTPUT ;
    USE SIGNAL ;
    SHAPE ABUTMENT ;
    PORT
      LAYER met2 ;
      RECT 717.530 0.000 717.670 0.420 ;
    END
  END r0_rd_out[29]
  PIN r0_rd_out[30]
    DIRECTION OUTPUT ;
    USE SIGNAL ;
    SHAPE ABUTMENT ;
    PORT
      LAYER met2 ;
      RECT 720.290 0.000 720.430 0.420 ;
    END
  END r0_rd_out[30]
  PIN r0_rd_out[31]
    DIRECTION OUTPUT ;
    USE SIGNAL ;
    SHAPE ABUTMENT ;
    PORT
      LAYER met2 ;
      RECT 723.050 0.000 723.190 0.420 ;
    END
  END r0_rd_out[31]
  PIN r0_rd_out[32]
    DIRECTION OUTPUT ;
    USE SIGNAL ;
    SHAPE ABUTMENT ;
    PORT
      LAYER met2 ;
      RECT 725.810 0.000 725.950 0.420 ;
    END
  END r0_rd_out[32]
  PIN r0_rd_out[33]
    DIRECTION OUTPUT ;
    USE SIGNAL ;
    SHAPE ABUTMENT ;
    PORT
      LAYER met2 ;
      RECT 728.570 0.000 728.710 0.420 ;
    END
  END r0_rd_out[33]
  PIN r0_rd_out[34]
    DIRECTION OUTPUT ;
    USE SIGNAL ;
    SHAPE ABUTMENT ;
    PORT
      LAYER met2 ;
      RECT 731.330 0.000 731.470 0.420 ;
    END
  END r0_rd_out[34]
  PIN r0_rd_out[35]
    DIRECTION OUTPUT ;
    USE SIGNAL ;
    SHAPE ABUTMENT ;
    PORT
      LAYER met2 ;
      RECT 734.090 0.000 734.230 0.420 ;
    END
  END r0_rd_out[35]
  PIN r0_rd_out[36]
    DIRECTION OUTPUT ;
    USE SIGNAL ;
    SHAPE ABUTMENT ;
    PORT
      LAYER met2 ;
      RECT 736.850 0.000 736.990 0.420 ;
    END
  END r0_rd_out[36]
  PIN r0_rd_out[37]
    DIRECTION OUTPUT ;
    USE SIGNAL ;
    SHAPE ABUTMENT ;
    PORT
      LAYER met2 ;
      RECT 739.610 0.000 739.750 0.420 ;
    END
  END r0_rd_out[37]
  PIN r0_rd_out[38]
    DIRECTION OUTPUT ;
    USE SIGNAL ;
    SHAPE ABUTMENT ;
    PORT
      LAYER met2 ;
      RECT 742.370 0.000 742.510 0.420 ;
    END
  END r0_rd_out[38]
  PIN r0_rd_out[39]
    DIRECTION OUTPUT ;
    USE SIGNAL ;
    SHAPE ABUTMENT ;
    PORT
      LAYER met2 ;
      RECT 745.130 0.000 745.270 0.420 ;
    END
  END r0_rd_out[39]
  PIN r0_rd_out[40]
    DIRECTION OUTPUT ;
    USE SIGNAL ;
    SHAPE ABUTMENT ;
    PORT
      LAYER met2 ;
      RECT 747.890 0.000 748.030 0.420 ;
    END
  END r0_rd_out[40]
  PIN r0_rd_out[41]
    DIRECTION OUTPUT ;
    USE SIGNAL ;
    SHAPE ABUTMENT ;
    PORT
      LAYER met2 ;
      RECT 750.650 0.000 750.790 0.420 ;
    END
  END r0_rd_out[41]
  PIN r0_rd_out[42]
    DIRECTION OUTPUT ;
    USE SIGNAL ;
    SHAPE ABUTMENT ;
    PORT
      LAYER met2 ;
      RECT 753.410 0.000 753.550 0.420 ;
    END
  END r0_rd_out[42]
  PIN r0_rd_out[43]
    DIRECTION OUTPUT ;
    USE SIGNAL ;
    SHAPE ABUTMENT ;
    PORT
      LAYER met2 ;
      RECT 756.170 0.000 756.310 0.420 ;
    END
  END r0_rd_out[43]
  PIN r0_rd_out[44]
    DIRECTION OUTPUT ;
    USE SIGNAL ;
    SHAPE ABUTMENT ;
    PORT
      LAYER met2 ;
      RECT 758.930 0.000 759.070 0.420 ;
    END
  END r0_rd_out[44]
  PIN r0_rd_out[45]
    DIRECTION OUTPUT ;
    USE SIGNAL ;
    SHAPE ABUTMENT ;
    PORT
      LAYER met2 ;
      RECT 761.690 0.000 761.830 0.420 ;
    END
  END r0_rd_out[45]
  PIN r0_rd_out[46]
    DIRECTION OUTPUT ;
    USE SIGNAL ;
    SHAPE ABUTMENT ;
    PORT
      LAYER met2 ;
      RECT 764.450 0.000 764.590 0.420 ;
    END
  END r0_rd_out[46]
  PIN r0_rd_out[47]
    DIRECTION OUTPUT ;
    USE SIGNAL ;
    SHAPE ABUTMENT ;
    PORT
      LAYER met2 ;
      RECT 767.210 0.000 767.350 0.420 ;
    END
  END r0_rd_out[47]
  PIN r0_rd_out[48]
    DIRECTION OUTPUT ;
    USE SIGNAL ;
    SHAPE ABUTMENT ;
    PORT
      LAYER met2 ;
      RECT 769.970 0.000 770.110 0.420 ;
    END
  END r0_rd_out[48]
  PIN r0_rd_out[49]
    DIRECTION OUTPUT ;
    USE SIGNAL ;
    SHAPE ABUTMENT ;
    PORT
      LAYER met2 ;
      RECT 772.730 0.000 772.870 0.420 ;
    END
  END r0_rd_out[49]
  PIN r0_rd_out[50]
    DIRECTION OUTPUT ;
    USE SIGNAL ;
    SHAPE ABUTMENT ;
    PORT
      LAYER met2 ;
      RECT 775.490 0.000 775.630 0.420 ;
    END
  END r0_rd_out[50]
  PIN r0_rd_out[51]
    DIRECTION OUTPUT ;
    USE SIGNAL ;
    SHAPE ABUTMENT ;
    PORT
      LAYER met2 ;
      RECT 778.250 0.000 778.390 0.420 ;
    END
  END r0_rd_out[51]
  PIN r0_rd_out[52]
    DIRECTION OUTPUT ;
    USE SIGNAL ;
    SHAPE ABUTMENT ;
    PORT
      LAYER met2 ;
      RECT 781.010 0.000 781.150 0.420 ;
    END
  END r0_rd_out[52]
  PIN r0_rd_out[53]
    DIRECTION OUTPUT ;
    USE SIGNAL ;
    SHAPE ABUTMENT ;
    PORT
      LAYER met2 ;
      RECT 783.770 0.000 783.910 0.420 ;
    END
  END r0_rd_out[53]
  PIN r0_rd_out[54]
    DIRECTION OUTPUT ;
    USE SIGNAL ;
    SHAPE ABUTMENT ;
    PORT
      LAYER met2 ;
      RECT 786.530 0.000 786.670 0.420 ;
    END
  END r0_rd_out[54]
  PIN r0_rd_out[55]
    DIRECTION OUTPUT ;
    USE SIGNAL ;
    SHAPE ABUTMENT ;
    PORT
      LAYER met2 ;
      RECT 789.290 0.000 789.430 0.420 ;
    END
  END r0_rd_out[55]
  PIN r0_rd_out[56]
    DIRECTION OUTPUT ;
    USE SIGNAL ;
    SHAPE ABUTMENT ;
    PORT
      LAYER met2 ;
      RECT 792.050 0.000 792.190 0.420 ;
    END
  END r0_rd_out[56]
  PIN r0_rd_out[57]
    DIRECTION OUTPUT ;
    USE SIGNAL ;
    SHAPE ABUTMENT ;
    PORT
      LAYER met2 ;
      RECT 794.810 0.000 794.950 0.420 ;
    END
  END r0_rd_out[57]
  PIN r0_rd_out[58]
    DIRECTION OUTPUT ;
    USE SIGNAL ;
    SHAPE ABUTMENT ;
    PORT
      LAYER met2 ;
      RECT 797.570 0.000 797.710 0.420 ;
    END
  END r0_rd_out[58]
  PIN r0_rd_out[59]
    DIRECTION OUTPUT ;
    USE SIGNAL ;
    SHAPE ABUTMENT ;
    PORT
      LAYER met2 ;
      RECT 800.330 0.000 800.470 0.420 ;
    END
  END r0_rd_out[59]
  PIN r0_rd_out[60]
    DIRECTION OUTPUT ;
    USE SIGNAL ;
    SHAPE ABUTMENT ;
    PORT
      LAYER met2 ;
      RECT 803.090 0.000 803.230 0.420 ;
    END
  END r0_rd_out[60]
  PIN r0_rd_out[61]
    DIRECTION OUTPUT ;
    USE SIGNAL ;
    SHAPE ABUTMENT ;
    PORT
      LAYER met2 ;
      RECT 805.850 0.000 805.990 0.420 ;
    END
  END r0_rd_out[61]
  PIN r0_rd_out[62]
    DIRECTION OUTPUT ;
    USE SIGNAL ;
    SHAPE ABUTMENT ;
    PORT
      LAYER met2 ;
      RECT 808.610 0.000 808.750 0.420 ;
    END
  END r0_rd_out[62]
  PIN r0_rd_out[63]
    DIRECTION OUTPUT ;
    USE SIGNAL ;
    SHAPE ABUTMENT ;
    PORT
      LAYER met2 ;
      RECT 811.370 0.000 811.510 0.420 ;
    END
  END r0_rd_out[63]
  PIN r0_rd_out[64]
    DIRECTION OUTPUT ;
    USE SIGNAL ;
    SHAPE ABUTMENT ;
    PORT
      LAYER met2 ;
      RECT 814.130 0.000 814.270 0.420 ;
    END
  END r0_rd_out[64]
  PIN r0_rd_out[65]
    DIRECTION OUTPUT ;
    USE SIGNAL ;
    SHAPE ABUTMENT ;
    PORT
      LAYER met2 ;
      RECT 816.890 0.000 817.030 0.420 ;
    END
  END r0_rd_out[65]
  PIN r0_rd_out[66]
    DIRECTION OUTPUT ;
    USE SIGNAL ;
    SHAPE ABUTMENT ;
    PORT
      LAYER met2 ;
      RECT 819.650 0.000 819.790 0.420 ;
    END
  END r0_rd_out[66]
  PIN r0_rd_out[67]
    DIRECTION OUTPUT ;
    USE SIGNAL ;
    SHAPE ABUTMENT ;
    PORT
      LAYER met2 ;
      RECT 822.410 0.000 822.550 0.420 ;
    END
  END r0_rd_out[67]
  PIN r0_rd_out[68]
    DIRECTION OUTPUT ;
    USE SIGNAL ;
    SHAPE ABUTMENT ;
    PORT
      LAYER met2 ;
      RECT 825.170 0.000 825.310 0.420 ;
    END
  END r0_rd_out[68]
  PIN r0_rd_out[69]
    DIRECTION OUTPUT ;
    USE SIGNAL ;
    SHAPE ABUTMENT ;
    PORT
      LAYER met2 ;
      RECT 827.930 0.000 828.070 0.420 ;
    END
  END r0_rd_out[69]
  PIN r0_rd_out[70]
    DIRECTION OUTPUT ;
    USE SIGNAL ;
    SHAPE ABUTMENT ;
    PORT
      LAYER met2 ;
      RECT 830.690 0.000 830.830 0.420 ;
    END
  END r0_rd_out[70]
  PIN r0_rd_out[71]
    DIRECTION OUTPUT ;
    USE SIGNAL ;
    SHAPE ABUTMENT ;
    PORT
      LAYER met2 ;
      RECT 833.450 0.000 833.590 0.420 ;
    END
  END r0_rd_out[71]
  PIN r0_rd_out[72]
    DIRECTION OUTPUT ;
    USE SIGNAL ;
    SHAPE ABUTMENT ;
    PORT
      LAYER met2 ;
      RECT 836.210 0.000 836.350 0.420 ;
    END
  END r0_rd_out[72]
  PIN r0_rd_out[73]
    DIRECTION OUTPUT ;
    USE SIGNAL ;
    SHAPE ABUTMENT ;
    PORT
      LAYER met2 ;
      RECT 838.970 0.000 839.110 0.420 ;
    END
  END r0_rd_out[73]
  PIN r0_rd_out[74]
    DIRECTION OUTPUT ;
    USE SIGNAL ;
    SHAPE ABUTMENT ;
    PORT
      LAYER met2 ;
      RECT 841.730 0.000 841.870 0.420 ;
    END
  END r0_rd_out[74]
  PIN r0_rd_out[75]
    DIRECTION OUTPUT ;
    USE SIGNAL ;
    SHAPE ABUTMENT ;
    PORT
      LAYER met2 ;
      RECT 844.490 0.000 844.630 0.420 ;
    END
  END r0_rd_out[75]
  PIN r0_rd_out[76]
    DIRECTION OUTPUT ;
    USE SIGNAL ;
    SHAPE ABUTMENT ;
    PORT
      LAYER met2 ;
      RECT 847.250 0.000 847.390 0.420 ;
    END
  END r0_rd_out[76]
  PIN r0_rd_out[77]
    DIRECTION OUTPUT ;
    USE SIGNAL ;
    SHAPE ABUTMENT ;
    PORT
      LAYER met2 ;
      RECT 850.010 0.000 850.150 0.420 ;
    END
  END r0_rd_out[77]
  PIN r0_rd_out[78]
    DIRECTION OUTPUT ;
    USE SIGNAL ;
    SHAPE ABUTMENT ;
    PORT
      LAYER met2 ;
      RECT 852.770 0.000 852.910 0.420 ;
    END
  END r0_rd_out[78]
  PIN r0_rd_out[79]
    DIRECTION OUTPUT ;
    USE SIGNAL ;
    SHAPE ABUTMENT ;
    PORT
      LAYER met2 ;
      RECT 855.530 0.000 855.670 0.420 ;
    END
  END r0_rd_out[79]
  PIN r0_rd_out[80]
    DIRECTION OUTPUT ;
    USE SIGNAL ;
    SHAPE ABUTMENT ;
    PORT
      LAYER met2 ;
      RECT 858.290 0.000 858.430 0.420 ;
    END
  END r0_rd_out[80]
  PIN r0_rd_out[81]
    DIRECTION OUTPUT ;
    USE SIGNAL ;
    SHAPE ABUTMENT ;
    PORT
      LAYER met2 ;
      RECT 861.050 0.000 861.190 0.420 ;
    END
  END r0_rd_out[81]
  PIN r0_rd_out[82]
    DIRECTION OUTPUT ;
    USE SIGNAL ;
    SHAPE ABUTMENT ;
    PORT
      LAYER met2 ;
      RECT 863.810 0.000 863.950 0.420 ;
    END
  END r0_rd_out[82]
  PIN r0_rd_out[83]
    DIRECTION OUTPUT ;
    USE SIGNAL ;
    SHAPE ABUTMENT ;
    PORT
      LAYER met2 ;
      RECT 866.570 0.000 866.710 0.420 ;
    END
  END r0_rd_out[83]
  PIN r0_rd_out[84]
    DIRECTION OUTPUT ;
    USE SIGNAL ;
    SHAPE ABUTMENT ;
    PORT
      LAYER met2 ;
      RECT 869.330 0.000 869.470 0.420 ;
    END
  END r0_rd_out[84]
  PIN r0_rd_out[85]
    DIRECTION OUTPUT ;
    USE SIGNAL ;
    SHAPE ABUTMENT ;
    PORT
      LAYER met2 ;
      RECT 872.090 0.000 872.230 0.420 ;
    END
  END r0_rd_out[85]
  PIN r0_rd_out[86]
    DIRECTION OUTPUT ;
    USE SIGNAL ;
    SHAPE ABUTMENT ;
    PORT
      LAYER met2 ;
      RECT 874.850 0.000 874.990 0.420 ;
    END
  END r0_rd_out[86]
  PIN r0_rd_out[87]
    DIRECTION OUTPUT ;
    USE SIGNAL ;
    SHAPE ABUTMENT ;
    PORT
      LAYER met2 ;
      RECT 877.610 0.000 877.750 0.420 ;
    END
  END r0_rd_out[87]
  PIN r0_rd_out[88]
    DIRECTION OUTPUT ;
    USE SIGNAL ;
    SHAPE ABUTMENT ;
    PORT
      LAYER met2 ;
      RECT 880.370 0.000 880.510 0.420 ;
    END
  END r0_rd_out[88]
  PIN r0_rd_out[89]
    DIRECTION OUTPUT ;
    USE SIGNAL ;
    SHAPE ABUTMENT ;
    PORT
      LAYER met2 ;
      RECT 883.130 0.000 883.270 0.420 ;
    END
  END r0_rd_out[89]
  PIN r0_rd_out[90]
    DIRECTION OUTPUT ;
    USE SIGNAL ;
    SHAPE ABUTMENT ;
    PORT
      LAYER met2 ;
      RECT 885.890 0.000 886.030 0.420 ;
    END
  END r0_rd_out[90]
  PIN r0_rd_out[91]
    DIRECTION OUTPUT ;
    USE SIGNAL ;
    SHAPE ABUTMENT ;
    PORT
      LAYER met2 ;
      RECT 888.650 0.000 888.790 0.420 ;
    END
  END r0_rd_out[91]
  PIN r0_rd_out[92]
    DIRECTION OUTPUT ;
    USE SIGNAL ;
    SHAPE ABUTMENT ;
    PORT
      LAYER met2 ;
      RECT 891.410 0.000 891.550 0.420 ;
    END
  END r0_rd_out[92]
  PIN r0_rd_out[93]
    DIRECTION OUTPUT ;
    USE SIGNAL ;
    SHAPE ABUTMENT ;
    PORT
      LAYER met2 ;
      RECT 894.170 0.000 894.310 0.420 ;
    END
  END r0_rd_out[93]
  PIN r0_rd_out[94]
    DIRECTION OUTPUT ;
    USE SIGNAL ;
    SHAPE ABUTMENT ;
    PORT
      LAYER met2 ;
      RECT 896.930 0.000 897.070 0.420 ;
    END
  END r0_rd_out[94]
  PIN r0_rd_out[95]
    DIRECTION OUTPUT ;
    USE SIGNAL ;
    SHAPE ABUTMENT ;
    PORT
      LAYER met2 ;
      RECT 899.690 0.000 899.830 0.420 ;
    END
  END r0_rd_out[95]
  PIN r0_rd_out[96]
    DIRECTION OUTPUT ;
    USE SIGNAL ;
    SHAPE ABUTMENT ;
    PORT
      LAYER met2 ;
      RECT 902.450 0.000 902.590 0.420 ;
    END
  END r0_rd_out[96]
  PIN r0_rd_out[97]
    DIRECTION OUTPUT ;
    USE SIGNAL ;
    SHAPE ABUTMENT ;
    PORT
      LAYER met2 ;
      RECT 905.210 0.000 905.350 0.420 ;
    END
  END r0_rd_out[97]
  PIN r0_rd_out[98]
    DIRECTION OUTPUT ;
    USE SIGNAL ;
    SHAPE ABUTMENT ;
    PORT
      LAYER met2 ;
      RECT 907.970 0.000 908.110 0.420 ;
    END
  END r0_rd_out[98]
  PIN r0_rd_out[99]
    DIRECTION OUTPUT ;
    USE SIGNAL ;
    SHAPE ABUTMENT ;
    PORT
      LAYER met2 ;
      RECT 910.730 0.000 910.870 0.420 ;
    END
  END r0_rd_out[99]
  PIN r0_rd_out[100]
    DIRECTION OUTPUT ;
    USE SIGNAL ;
    SHAPE ABUTMENT ;
    PORT
      LAYER met2 ;
      RECT 913.490 0.000 913.630 0.420 ;
    END
  END r0_rd_out[100]
  PIN r0_rd_out[101]
    DIRECTION OUTPUT ;
    USE SIGNAL ;
    SHAPE ABUTMENT ;
    PORT
      LAYER met2 ;
      RECT 916.250 0.000 916.390 0.420 ;
    END
  END r0_rd_out[101]
  PIN r0_rd_out[102]
    DIRECTION OUTPUT ;
    USE SIGNAL ;
    SHAPE ABUTMENT ;
    PORT
      LAYER met2 ;
      RECT 919.010 0.000 919.150 0.420 ;
    END
  END r0_rd_out[102]
  PIN r0_rd_out[103]
    DIRECTION OUTPUT ;
    USE SIGNAL ;
    SHAPE ABUTMENT ;
    PORT
      LAYER met2 ;
      RECT 921.770 0.000 921.910 0.420 ;
    END
  END r0_rd_out[103]
  PIN r0_rd_out[104]
    DIRECTION OUTPUT ;
    USE SIGNAL ;
    SHAPE ABUTMENT ;
    PORT
      LAYER met2 ;
      RECT 924.530 0.000 924.670 0.420 ;
    END
  END r0_rd_out[104]
  PIN r0_rd_out[105]
    DIRECTION OUTPUT ;
    USE SIGNAL ;
    SHAPE ABUTMENT ;
    PORT
      LAYER met2 ;
      RECT 927.290 0.000 927.430 0.420 ;
    END
  END r0_rd_out[105]
  PIN r0_rd_out[106]
    DIRECTION OUTPUT ;
    USE SIGNAL ;
    SHAPE ABUTMENT ;
    PORT
      LAYER met2 ;
      RECT 930.050 0.000 930.190 0.420 ;
    END
  END r0_rd_out[106]
  PIN r0_rd_out[107]
    DIRECTION OUTPUT ;
    USE SIGNAL ;
    SHAPE ABUTMENT ;
    PORT
      LAYER met2 ;
      RECT 932.810 0.000 932.950 0.420 ;
    END
  END r0_rd_out[107]
  PIN r0_rd_out[108]
    DIRECTION OUTPUT ;
    USE SIGNAL ;
    SHAPE ABUTMENT ;
    PORT
      LAYER met2 ;
      RECT 935.570 0.000 935.710 0.420 ;
    END
  END r0_rd_out[108]
  PIN r0_rd_out[109]
    DIRECTION OUTPUT ;
    USE SIGNAL ;
    SHAPE ABUTMENT ;
    PORT
      LAYER met2 ;
      RECT 938.330 0.000 938.470 0.420 ;
    END
  END r0_rd_out[109]
  PIN r0_rd_out[110]
    DIRECTION OUTPUT ;
    USE SIGNAL ;
    SHAPE ABUTMENT ;
    PORT
      LAYER met2 ;
      RECT 941.090 0.000 941.230 0.420 ;
    END
  END r0_rd_out[110]
  PIN r0_rd_out[111]
    DIRECTION OUTPUT ;
    USE SIGNAL ;
    SHAPE ABUTMENT ;
    PORT
      LAYER met2 ;
      RECT 943.850 0.000 943.990 0.420 ;
    END
  END r0_rd_out[111]
  PIN r0_rd_out[112]
    DIRECTION OUTPUT ;
    USE SIGNAL ;
    SHAPE ABUTMENT ;
    PORT
      LAYER met2 ;
      RECT 946.610 0.000 946.750 0.420 ;
    END
  END r0_rd_out[112]
  PIN r0_rd_out[113]
    DIRECTION OUTPUT ;
    USE SIGNAL ;
    SHAPE ABUTMENT ;
    PORT
      LAYER met2 ;
      RECT 949.370 0.000 949.510 0.420 ;
    END
  END r0_rd_out[113]
  PIN r0_rd_out[114]
    DIRECTION OUTPUT ;
    USE SIGNAL ;
    SHAPE ABUTMENT ;
    PORT
      LAYER met2 ;
      RECT 952.130 0.000 952.270 0.420 ;
    END
  END r0_rd_out[114]
  PIN r0_rd_out[115]
    DIRECTION OUTPUT ;
    USE SIGNAL ;
    SHAPE ABUTMENT ;
    PORT
      LAYER met2 ;
      RECT 478.790 948.860 478.930 949.280 ;
    END
  END r0_rd_out[115]
  PIN r0_rd_out[116]
    DIRECTION OUTPUT ;
    USE SIGNAL ;
    SHAPE ABUTMENT ;
    PORT
      LAYER met2 ;
      RECT 482.930 948.860 483.070 949.280 ;
    END
  END r0_rd_out[116]
  PIN r0_rd_out[117]
    DIRECTION OUTPUT ;
    USE SIGNAL ;
    SHAPE ABUTMENT ;
    PORT
      LAYER met2 ;
      RECT 487.070 948.860 487.210 949.280 ;
    END
  END r0_rd_out[117]
  PIN r0_rd_out[118]
    DIRECTION OUTPUT ;
    USE SIGNAL ;
    SHAPE ABUTMENT ;
    PORT
      LAYER met2 ;
      RECT 491.210 948.860 491.350 949.280 ;
    END
  END r0_rd_out[118]
  PIN r0_rd_out[119]
    DIRECTION OUTPUT ;
    USE SIGNAL ;
    SHAPE ABUTMENT ;
    PORT
      LAYER met2 ;
      RECT 495.350 948.860 495.490 949.280 ;
    END
  END r0_rd_out[119]
  PIN r0_rd_out[120]
    DIRECTION OUTPUT ;
    USE SIGNAL ;
    SHAPE ABUTMENT ;
    PORT
      LAYER met2 ;
      RECT 499.490 948.860 499.630 949.280 ;
    END
  END r0_rd_out[120]
  PIN r0_rd_out[121]
    DIRECTION OUTPUT ;
    USE SIGNAL ;
    SHAPE ABUTMENT ;
    PORT
      LAYER met2 ;
      RECT 503.630 948.860 503.770 949.280 ;
    END
  END r0_rd_out[121]
  PIN r0_rd_out[122]
    DIRECTION OUTPUT ;
    USE SIGNAL ;
    SHAPE ABUTMENT ;
    PORT
      LAYER met2 ;
      RECT 507.770 948.860 507.910 949.280 ;
    END
  END r0_rd_out[122]
  PIN r0_rd_out[123]
    DIRECTION OUTPUT ;
    USE SIGNAL ;
    SHAPE ABUTMENT ;
    PORT
      LAYER met2 ;
      RECT 511.910 948.860 512.050 949.280 ;
    END
  END r0_rd_out[123]
  PIN r0_rd_out[124]
    DIRECTION OUTPUT ;
    USE SIGNAL ;
    SHAPE ABUTMENT ;
    PORT
      LAYER met2 ;
      RECT 516.050 948.860 516.190 949.280 ;
    END
  END r0_rd_out[124]
  PIN r0_rd_out[125]
    DIRECTION OUTPUT ;
    USE SIGNAL ;
    SHAPE ABUTMENT ;
    PORT
      LAYER met2 ;
      RECT 520.190 948.860 520.330 949.280 ;
    END
  END r0_rd_out[125]
  PIN r0_rd_out[126]
    DIRECTION OUTPUT ;
    USE SIGNAL ;
    SHAPE ABUTMENT ;
    PORT
      LAYER met2 ;
      RECT 524.330 948.860 524.470 949.280 ;
    END
  END r0_rd_out[126]
  PIN r0_rd_out[127]
    DIRECTION OUTPUT ;
    USE SIGNAL ;
    SHAPE ABUTMENT ;
    PORT
      LAYER met2 ;
      RECT 528.470 948.860 528.610 949.280 ;
    END
  END r0_rd_out[127]
  PIN r0_rd_out[128]
    DIRECTION OUTPUT ;
    USE SIGNAL ;
    SHAPE ABUTMENT ;
    PORT
      LAYER met2 ;
      RECT 532.610 948.860 532.750 949.280 ;
    END
  END r0_rd_out[128]
  PIN r0_rd_out[129]
    DIRECTION OUTPUT ;
    USE SIGNAL ;
    SHAPE ABUTMENT ;
    PORT
      LAYER met2 ;
      RECT 536.750 948.860 536.890 949.280 ;
    END
  END r0_rd_out[129]
  PIN r0_rd_out[130]
    DIRECTION OUTPUT ;
    USE SIGNAL ;
    SHAPE ABUTMENT ;
    PORT
      LAYER met2 ;
      RECT 540.890 948.860 541.030 949.280 ;
    END
  END r0_rd_out[130]
  PIN r0_rd_out[131]
    DIRECTION OUTPUT ;
    USE SIGNAL ;
    SHAPE ABUTMENT ;
    PORT
      LAYER met2 ;
      RECT 545.030 948.860 545.170 949.280 ;
    END
  END r0_rd_out[131]
  PIN r0_rd_out[132]
    DIRECTION OUTPUT ;
    USE SIGNAL ;
    SHAPE ABUTMENT ;
    PORT
      LAYER met2 ;
      RECT 549.170 948.860 549.310 949.280 ;
    END
  END r0_rd_out[132]
  PIN r0_rd_out[133]
    DIRECTION OUTPUT ;
    USE SIGNAL ;
    SHAPE ABUTMENT ;
    PORT
      LAYER met2 ;
      RECT 553.310 948.860 553.450 949.280 ;
    END
  END r0_rd_out[133]
  PIN r0_rd_out[134]
    DIRECTION OUTPUT ;
    USE SIGNAL ;
    SHAPE ABUTMENT ;
    PORT
      LAYER met2 ;
      RECT 557.450 948.860 557.590 949.280 ;
    END
  END r0_rd_out[134]
  PIN r0_rd_out[135]
    DIRECTION OUTPUT ;
    USE SIGNAL ;
    SHAPE ABUTMENT ;
    PORT
      LAYER met2 ;
      RECT 561.590 948.860 561.730 949.280 ;
    END
  END r0_rd_out[135]
  PIN r0_rd_out[136]
    DIRECTION OUTPUT ;
    USE SIGNAL ;
    SHAPE ABUTMENT ;
    PORT
      LAYER met2 ;
      RECT 565.730 948.860 565.870 949.280 ;
    END
  END r0_rd_out[136]
  PIN r0_rd_out[137]
    DIRECTION OUTPUT ;
    USE SIGNAL ;
    SHAPE ABUTMENT ;
    PORT
      LAYER met2 ;
      RECT 569.870 948.860 570.010 949.280 ;
    END
  END r0_rd_out[137]
  PIN r0_rd_out[138]
    DIRECTION OUTPUT ;
    USE SIGNAL ;
    SHAPE ABUTMENT ;
    PORT
      LAYER met2 ;
      RECT 574.010 948.860 574.150 949.280 ;
    END
  END r0_rd_out[138]
  PIN r0_rd_out[139]
    DIRECTION OUTPUT ;
    USE SIGNAL ;
    SHAPE ABUTMENT ;
    PORT
      LAYER met2 ;
      RECT 578.150 948.860 578.290 949.280 ;
    END
  END r0_rd_out[139]
  PIN r0_rd_out[140]
    DIRECTION OUTPUT ;
    USE SIGNAL ;
    SHAPE ABUTMENT ;
    PORT
      LAYER met2 ;
      RECT 582.290 948.860 582.430 949.280 ;
    END
  END r0_rd_out[140]
  PIN r0_rd_out[141]
    DIRECTION OUTPUT ;
    USE SIGNAL ;
    SHAPE ABUTMENT ;
    PORT
      LAYER met2 ;
      RECT 586.430 948.860 586.570 949.280 ;
    END
  END r0_rd_out[141]
  PIN r0_rd_out[142]
    DIRECTION OUTPUT ;
    USE SIGNAL ;
    SHAPE ABUTMENT ;
    PORT
      LAYER met2 ;
      RECT 590.570 948.860 590.710 949.280 ;
    END
  END r0_rd_out[142]
  PIN r0_rd_out[143]
    DIRECTION OUTPUT ;
    USE SIGNAL ;
    SHAPE ABUTMENT ;
    PORT
      LAYER met2 ;
      RECT 594.710 948.860 594.850 949.280 ;
    END
  END r0_rd_out[143]
  PIN r0_rd_out[144]
    DIRECTION OUTPUT ;
    USE SIGNAL ;
    SHAPE ABUTMENT ;
    PORT
      LAYER met2 ;
      RECT 598.850 948.860 598.990 949.280 ;
    END
  END r0_rd_out[144]
  PIN r0_rd_out[145]
    DIRECTION OUTPUT ;
    USE SIGNAL ;
    SHAPE ABUTMENT ;
    PORT
      LAYER met2 ;
      RECT 602.990 948.860 603.130 949.280 ;
    END
  END r0_rd_out[145]
  PIN r0_rd_out[146]
    DIRECTION OUTPUT ;
    USE SIGNAL ;
    SHAPE ABUTMENT ;
    PORT
      LAYER met2 ;
      RECT 607.130 948.860 607.270 949.280 ;
    END
  END r0_rd_out[146]
  PIN r0_rd_out[147]
    DIRECTION OUTPUT ;
    USE SIGNAL ;
    SHAPE ABUTMENT ;
    PORT
      LAYER met2 ;
      RECT 611.270 948.860 611.410 949.280 ;
    END
  END r0_rd_out[147]
  PIN r0_rd_out[148]
    DIRECTION OUTPUT ;
    USE SIGNAL ;
    SHAPE ABUTMENT ;
    PORT
      LAYER met2 ;
      RECT 615.410 948.860 615.550 949.280 ;
    END
  END r0_rd_out[148]
  PIN r0_rd_out[149]
    DIRECTION OUTPUT ;
    USE SIGNAL ;
    SHAPE ABUTMENT ;
    PORT
      LAYER met2 ;
      RECT 619.550 948.860 619.690 949.280 ;
    END
  END r0_rd_out[149]
  PIN r0_rd_out[150]
    DIRECTION OUTPUT ;
    USE SIGNAL ;
    SHAPE ABUTMENT ;
    PORT
      LAYER met2 ;
      RECT 623.690 948.860 623.830 949.280 ;
    END
  END r0_rd_out[150]
  PIN r0_rd_out[151]
    DIRECTION OUTPUT ;
    USE SIGNAL ;
    SHAPE ABUTMENT ;
    PORT
      LAYER met2 ;
      RECT 627.830 948.860 627.970 949.280 ;
    END
  END r0_rd_out[151]
  PIN r0_rd_out[152]
    DIRECTION OUTPUT ;
    USE SIGNAL ;
    SHAPE ABUTMENT ;
    PORT
      LAYER met2 ;
      RECT 631.970 948.860 632.110 949.280 ;
    END
  END r0_rd_out[152]
  PIN r0_rd_out[153]
    DIRECTION OUTPUT ;
    USE SIGNAL ;
    SHAPE ABUTMENT ;
    PORT
      LAYER met2 ;
      RECT 636.110 948.860 636.250 949.280 ;
    END
  END r0_rd_out[153]
  PIN r0_rd_out[154]
    DIRECTION OUTPUT ;
    USE SIGNAL ;
    SHAPE ABUTMENT ;
    PORT
      LAYER met2 ;
      RECT 640.250 948.860 640.390 949.280 ;
    END
  END r0_rd_out[154]
  PIN r0_rd_out[155]
    DIRECTION OUTPUT ;
    USE SIGNAL ;
    SHAPE ABUTMENT ;
    PORT
      LAYER met2 ;
      RECT 644.390 948.860 644.530 949.280 ;
    END
  END r0_rd_out[155]
  PIN r0_rd_out[156]
    DIRECTION OUTPUT ;
    USE SIGNAL ;
    SHAPE ABUTMENT ;
    PORT
      LAYER met2 ;
      RECT 648.530 948.860 648.670 949.280 ;
    END
  END r0_rd_out[156]
  PIN r0_rd_out[157]
    DIRECTION OUTPUT ;
    USE SIGNAL ;
    SHAPE ABUTMENT ;
    PORT
      LAYER met2 ;
      RECT 652.670 948.860 652.810 949.280 ;
    END
  END r0_rd_out[157]
  PIN r0_rd_out[158]
    DIRECTION OUTPUT ;
    USE SIGNAL ;
    SHAPE ABUTMENT ;
    PORT
      LAYER met2 ;
      RECT 656.810 948.860 656.950 949.280 ;
    END
  END r0_rd_out[158]
  PIN r0_rd_out[159]
    DIRECTION OUTPUT ;
    USE SIGNAL ;
    SHAPE ABUTMENT ;
    PORT
      LAYER met2 ;
      RECT 660.950 948.860 661.090 949.280 ;
    END
  END r0_rd_out[159]
  PIN r0_rd_out[160]
    DIRECTION OUTPUT ;
    USE SIGNAL ;
    SHAPE ABUTMENT ;
    PORT
      LAYER met2 ;
      RECT 665.090 948.860 665.230 949.280 ;
    END
  END r0_rd_out[160]
  PIN r0_rd_out[161]
    DIRECTION OUTPUT ;
    USE SIGNAL ;
    SHAPE ABUTMENT ;
    PORT
      LAYER met2 ;
      RECT 669.230 948.860 669.370 949.280 ;
    END
  END r0_rd_out[161]
  PIN r0_rd_out[162]
    DIRECTION OUTPUT ;
    USE SIGNAL ;
    SHAPE ABUTMENT ;
    PORT
      LAYER met2 ;
      RECT 673.370 948.860 673.510 949.280 ;
    END
  END r0_rd_out[162]
  PIN r0_rd_out[163]
    DIRECTION OUTPUT ;
    USE SIGNAL ;
    SHAPE ABUTMENT ;
    PORT
      LAYER met2 ;
      RECT 677.510 948.860 677.650 949.280 ;
    END
  END r0_rd_out[163]
  PIN r0_rd_out[164]
    DIRECTION OUTPUT ;
    USE SIGNAL ;
    SHAPE ABUTMENT ;
    PORT
      LAYER met2 ;
      RECT 681.650 948.860 681.790 949.280 ;
    END
  END r0_rd_out[164]
  PIN r0_rd_out[165]
    DIRECTION OUTPUT ;
    USE SIGNAL ;
    SHAPE ABUTMENT ;
    PORT
      LAYER met2 ;
      RECT 685.790 948.860 685.930 949.280 ;
    END
  END r0_rd_out[165]
  PIN r0_rd_out[166]
    DIRECTION OUTPUT ;
    USE SIGNAL ;
    SHAPE ABUTMENT ;
    PORT
      LAYER met2 ;
      RECT 689.930 948.860 690.070 949.280 ;
    END
  END r0_rd_out[166]
  PIN r0_rd_out[167]
    DIRECTION OUTPUT ;
    USE SIGNAL ;
    SHAPE ABUTMENT ;
    PORT
      LAYER met2 ;
      RECT 694.070 948.860 694.210 949.280 ;
    END
  END r0_rd_out[167]
  PIN r0_rd_out[168]
    DIRECTION OUTPUT ;
    USE SIGNAL ;
    SHAPE ABUTMENT ;
    PORT
      LAYER met2 ;
      RECT 698.210 948.860 698.350 949.280 ;
    END
  END r0_rd_out[168]
  PIN r0_rd_out[169]
    DIRECTION OUTPUT ;
    USE SIGNAL ;
    SHAPE ABUTMENT ;
    PORT
      LAYER met2 ;
      RECT 702.350 948.860 702.490 949.280 ;
    END
  END r0_rd_out[169]
  PIN r0_rd_out[170]
    DIRECTION OUTPUT ;
    USE SIGNAL ;
    SHAPE ABUTMENT ;
    PORT
      LAYER met2 ;
      RECT 706.490 948.860 706.630 949.280 ;
    END
  END r0_rd_out[170]
  PIN r0_rd_out[171]
    DIRECTION OUTPUT ;
    USE SIGNAL ;
    SHAPE ABUTMENT ;
    PORT
      LAYER met2 ;
      RECT 710.630 948.860 710.770 949.280 ;
    END
  END r0_rd_out[171]
  PIN r0_rd_out[172]
    DIRECTION OUTPUT ;
    USE SIGNAL ;
    SHAPE ABUTMENT ;
    PORT
      LAYER met2 ;
      RECT 714.770 948.860 714.910 949.280 ;
    END
  END r0_rd_out[172]
  PIN r0_rd_out[173]
    DIRECTION OUTPUT ;
    USE SIGNAL ;
    SHAPE ABUTMENT ;
    PORT
      LAYER met2 ;
      RECT 718.910 948.860 719.050 949.280 ;
    END
  END r0_rd_out[173]
  PIN r0_rd_out[174]
    DIRECTION OUTPUT ;
    USE SIGNAL ;
    SHAPE ABUTMENT ;
    PORT
      LAYER met2 ;
      RECT 723.050 948.860 723.190 949.280 ;
    END
  END r0_rd_out[174]
  PIN r0_rd_out[175]
    DIRECTION OUTPUT ;
    USE SIGNAL ;
    SHAPE ABUTMENT ;
    PORT
      LAYER met2 ;
      RECT 727.190 948.860 727.330 949.280 ;
    END
  END r0_rd_out[175]
  PIN r0_rd_out[176]
    DIRECTION OUTPUT ;
    USE SIGNAL ;
    SHAPE ABUTMENT ;
    PORT
      LAYER met2 ;
      RECT 731.330 948.860 731.470 949.280 ;
    END
  END r0_rd_out[176]
  PIN r0_rd_out[177]
    DIRECTION OUTPUT ;
    USE SIGNAL ;
    SHAPE ABUTMENT ;
    PORT
      LAYER met2 ;
      RECT 735.470 948.860 735.610 949.280 ;
    END
  END r0_rd_out[177]
  PIN r0_rd_out[178]
    DIRECTION OUTPUT ;
    USE SIGNAL ;
    SHAPE ABUTMENT ;
    PORT
      LAYER met2 ;
      RECT 739.610 948.860 739.750 949.280 ;
    END
  END r0_rd_out[178]
  PIN r0_rd_out[179]
    DIRECTION OUTPUT ;
    USE SIGNAL ;
    SHAPE ABUTMENT ;
    PORT
      LAYER met2 ;
      RECT 743.750 948.860 743.890 949.280 ;
    END
  END r0_rd_out[179]
  PIN r0_rd_out[180]
    DIRECTION OUTPUT ;
    USE SIGNAL ;
    SHAPE ABUTMENT ;
    PORT
      LAYER met2 ;
      RECT 747.890 948.860 748.030 949.280 ;
    END
  END r0_rd_out[180]
  PIN r0_rd_out[181]
    DIRECTION OUTPUT ;
    USE SIGNAL ;
    SHAPE ABUTMENT ;
    PORT
      LAYER met2 ;
      RECT 752.030 948.860 752.170 949.280 ;
    END
  END r0_rd_out[181]
  PIN r0_rd_out[182]
    DIRECTION OUTPUT ;
    USE SIGNAL ;
    SHAPE ABUTMENT ;
    PORT
      LAYER met2 ;
      RECT 756.170 948.860 756.310 949.280 ;
    END
  END r0_rd_out[182]
  PIN r0_rd_out[183]
    DIRECTION OUTPUT ;
    USE SIGNAL ;
    SHAPE ABUTMENT ;
    PORT
      LAYER met2 ;
      RECT 760.310 948.860 760.450 949.280 ;
    END
  END r0_rd_out[183]
  PIN r0_rd_out[184]
    DIRECTION OUTPUT ;
    USE SIGNAL ;
    SHAPE ABUTMENT ;
    PORT
      LAYER met2 ;
      RECT 764.450 948.860 764.590 949.280 ;
    END
  END r0_rd_out[184]
  PIN r0_rd_out[185]
    DIRECTION OUTPUT ;
    USE SIGNAL ;
    SHAPE ABUTMENT ;
    PORT
      LAYER met2 ;
      RECT 768.590 948.860 768.730 949.280 ;
    END
  END r0_rd_out[185]
  PIN r0_rd_out[186]
    DIRECTION OUTPUT ;
    USE SIGNAL ;
    SHAPE ABUTMENT ;
    PORT
      LAYER met2 ;
      RECT 772.730 948.860 772.870 949.280 ;
    END
  END r0_rd_out[186]
  PIN r0_rd_out[187]
    DIRECTION OUTPUT ;
    USE SIGNAL ;
    SHAPE ABUTMENT ;
    PORT
      LAYER met2 ;
      RECT 776.870 948.860 777.010 949.280 ;
    END
  END r0_rd_out[187]
  PIN r0_rd_out[188]
    DIRECTION OUTPUT ;
    USE SIGNAL ;
    SHAPE ABUTMENT ;
    PORT
      LAYER met2 ;
      RECT 781.010 948.860 781.150 949.280 ;
    END
  END r0_rd_out[188]
  PIN r0_rd_out[189]
    DIRECTION OUTPUT ;
    USE SIGNAL ;
    SHAPE ABUTMENT ;
    PORT
      LAYER met2 ;
      RECT 785.150 948.860 785.290 949.280 ;
    END
  END r0_rd_out[189]
  PIN r0_rd_out[190]
    DIRECTION OUTPUT ;
    USE SIGNAL ;
    SHAPE ABUTMENT ;
    PORT
      LAYER met2 ;
      RECT 789.290 948.860 789.430 949.280 ;
    END
  END r0_rd_out[190]
  PIN r0_rd_out[191]
    DIRECTION OUTPUT ;
    USE SIGNAL ;
    SHAPE ABUTMENT ;
    PORT
      LAYER met2 ;
      RECT 793.430 948.860 793.570 949.280 ;
    END
  END r0_rd_out[191]
  PIN r0_rd_out[192]
    DIRECTION OUTPUT ;
    USE SIGNAL ;
    SHAPE ABUTMENT ;
    PORT
      LAYER met2 ;
      RECT 797.570 948.860 797.710 949.280 ;
    END
  END r0_rd_out[192]
  PIN r0_rd_out[193]
    DIRECTION OUTPUT ;
    USE SIGNAL ;
    SHAPE ABUTMENT ;
    PORT
      LAYER met2 ;
      RECT 801.710 948.860 801.850 949.280 ;
    END
  END r0_rd_out[193]
  PIN r0_rd_out[194]
    DIRECTION OUTPUT ;
    USE SIGNAL ;
    SHAPE ABUTMENT ;
    PORT
      LAYER met2 ;
      RECT 805.850 948.860 805.990 949.280 ;
    END
  END r0_rd_out[194]
  PIN r0_rd_out[195]
    DIRECTION OUTPUT ;
    USE SIGNAL ;
    SHAPE ABUTMENT ;
    PORT
      LAYER met2 ;
      RECT 809.990 948.860 810.130 949.280 ;
    END
  END r0_rd_out[195]
  PIN r0_rd_out[196]
    DIRECTION OUTPUT ;
    USE SIGNAL ;
    SHAPE ABUTMENT ;
    PORT
      LAYER met2 ;
      RECT 814.130 948.860 814.270 949.280 ;
    END
  END r0_rd_out[196]
  PIN r0_rd_out[197]
    DIRECTION OUTPUT ;
    USE SIGNAL ;
    SHAPE ABUTMENT ;
    PORT
      LAYER met2 ;
      RECT 818.270 948.860 818.410 949.280 ;
    END
  END r0_rd_out[197]
  PIN r0_rd_out[198]
    DIRECTION OUTPUT ;
    USE SIGNAL ;
    SHAPE ABUTMENT ;
    PORT
      LAYER met2 ;
      RECT 822.410 948.860 822.550 949.280 ;
    END
  END r0_rd_out[198]
  PIN r0_rd_out[199]
    DIRECTION OUTPUT ;
    USE SIGNAL ;
    SHAPE ABUTMENT ;
    PORT
      LAYER met2 ;
      RECT 826.550 948.860 826.690 949.280 ;
    END
  END r0_rd_out[199]
  PIN r0_rd_out[200]
    DIRECTION OUTPUT ;
    USE SIGNAL ;
    SHAPE ABUTMENT ;
    PORT
      LAYER met2 ;
      RECT 830.690 948.860 830.830 949.280 ;
    END
  END r0_rd_out[200]
  PIN r0_rd_out[201]
    DIRECTION OUTPUT ;
    USE SIGNAL ;
    SHAPE ABUTMENT ;
    PORT
      LAYER met2 ;
      RECT 834.830 948.860 834.970 949.280 ;
    END
  END r0_rd_out[201]
  PIN r0_rd_out[202]
    DIRECTION OUTPUT ;
    USE SIGNAL ;
    SHAPE ABUTMENT ;
    PORT
      LAYER met2 ;
      RECT 838.970 948.860 839.110 949.280 ;
    END
  END r0_rd_out[202]
  PIN r0_rd_out[203]
    DIRECTION OUTPUT ;
    USE SIGNAL ;
    SHAPE ABUTMENT ;
    PORT
      LAYER met2 ;
      RECT 843.110 948.860 843.250 949.280 ;
    END
  END r0_rd_out[203]
  PIN r0_rd_out[204]
    DIRECTION OUTPUT ;
    USE SIGNAL ;
    SHAPE ABUTMENT ;
    PORT
      LAYER met2 ;
      RECT 847.250 948.860 847.390 949.280 ;
    END
  END r0_rd_out[204]
  PIN r0_rd_out[205]
    DIRECTION OUTPUT ;
    USE SIGNAL ;
    SHAPE ABUTMENT ;
    PORT
      LAYER met2 ;
      RECT 851.390 948.860 851.530 949.280 ;
    END
  END r0_rd_out[205]
  PIN r0_rd_out[206]
    DIRECTION OUTPUT ;
    USE SIGNAL ;
    SHAPE ABUTMENT ;
    PORT
      LAYER met2 ;
      RECT 855.530 948.860 855.670 949.280 ;
    END
  END r0_rd_out[206]
  PIN r0_rd_out[207]
    DIRECTION OUTPUT ;
    USE SIGNAL ;
    SHAPE ABUTMENT ;
    PORT
      LAYER met2 ;
      RECT 859.670 948.860 859.810 949.280 ;
    END
  END r0_rd_out[207]
  PIN r0_rd_out[208]
    DIRECTION OUTPUT ;
    USE SIGNAL ;
    SHAPE ABUTMENT ;
    PORT
      LAYER met2 ;
      RECT 863.810 948.860 863.950 949.280 ;
    END
  END r0_rd_out[208]
  PIN r0_rd_out[209]
    DIRECTION OUTPUT ;
    USE SIGNAL ;
    SHAPE ABUTMENT ;
    PORT
      LAYER met2 ;
      RECT 867.950 948.860 868.090 949.280 ;
    END
  END r0_rd_out[209]
  PIN r0_rd_out[210]
    DIRECTION OUTPUT ;
    USE SIGNAL ;
    SHAPE ABUTMENT ;
    PORT
      LAYER met2 ;
      RECT 872.090 948.860 872.230 949.280 ;
    END
  END r0_rd_out[210]
  PIN r0_rd_out[211]
    DIRECTION OUTPUT ;
    USE SIGNAL ;
    SHAPE ABUTMENT ;
    PORT
      LAYER met2 ;
      RECT 876.230 948.860 876.370 949.280 ;
    END
  END r0_rd_out[211]
  PIN r0_rd_out[212]
    DIRECTION OUTPUT ;
    USE SIGNAL ;
    SHAPE ABUTMENT ;
    PORT
      LAYER met2 ;
      RECT 880.370 948.860 880.510 949.280 ;
    END
  END r0_rd_out[212]
  PIN r0_rd_out[213]
    DIRECTION OUTPUT ;
    USE SIGNAL ;
    SHAPE ABUTMENT ;
    PORT
      LAYER met2 ;
      RECT 884.510 948.860 884.650 949.280 ;
    END
  END r0_rd_out[213]
  PIN r0_rd_out[214]
    DIRECTION OUTPUT ;
    USE SIGNAL ;
    SHAPE ABUTMENT ;
    PORT
      LAYER met2 ;
      RECT 888.650 948.860 888.790 949.280 ;
    END
  END r0_rd_out[214]
  PIN r0_rd_out[215]
    DIRECTION OUTPUT ;
    USE SIGNAL ;
    SHAPE ABUTMENT ;
    PORT
      LAYER met2 ;
      RECT 892.790 948.860 892.930 949.280 ;
    END
  END r0_rd_out[215]
  PIN r0_rd_out[216]
    DIRECTION OUTPUT ;
    USE SIGNAL ;
    SHAPE ABUTMENT ;
    PORT
      LAYER met2 ;
      RECT 896.930 948.860 897.070 949.280 ;
    END
  END r0_rd_out[216]
  PIN r0_rd_out[217]
    DIRECTION OUTPUT ;
    USE SIGNAL ;
    SHAPE ABUTMENT ;
    PORT
      LAYER met2 ;
      RECT 901.070 948.860 901.210 949.280 ;
    END
  END r0_rd_out[217]
  PIN r0_rd_out[218]
    DIRECTION OUTPUT ;
    USE SIGNAL ;
    SHAPE ABUTMENT ;
    PORT
      LAYER met2 ;
      RECT 905.210 948.860 905.350 949.280 ;
    END
  END r0_rd_out[218]
  PIN r0_rd_out[219]
    DIRECTION OUTPUT ;
    USE SIGNAL ;
    SHAPE ABUTMENT ;
    PORT
      LAYER met2 ;
      RECT 909.350 948.860 909.490 949.280 ;
    END
  END r0_rd_out[219]
  PIN r0_rd_out[220]
    DIRECTION OUTPUT ;
    USE SIGNAL ;
    SHAPE ABUTMENT ;
    PORT
      LAYER met2 ;
      RECT 913.490 948.860 913.630 949.280 ;
    END
  END r0_rd_out[220]
  PIN r0_rd_out[221]
    DIRECTION OUTPUT ;
    USE SIGNAL ;
    SHAPE ABUTMENT ;
    PORT
      LAYER met2 ;
      RECT 917.630 948.860 917.770 949.280 ;
    END
  END r0_rd_out[221]
  PIN r0_rd_out[222]
    DIRECTION OUTPUT ;
    USE SIGNAL ;
    SHAPE ABUTMENT ;
    PORT
      LAYER met2 ;
      RECT 921.770 948.860 921.910 949.280 ;
    END
  END r0_rd_out[222]
  PIN r0_rd_out[223]
    DIRECTION OUTPUT ;
    USE SIGNAL ;
    SHAPE ABUTMENT ;
    PORT
      LAYER met2 ;
      RECT 925.910 948.860 926.050 949.280 ;
    END
  END r0_rd_out[223]
  PIN r0_rd_out[224]
    DIRECTION OUTPUT ;
    USE SIGNAL ;
    SHAPE ABUTMENT ;
    PORT
      LAYER met2 ;
      RECT 930.050 948.860 930.190 949.280 ;
    END
  END r0_rd_out[224]
  PIN r0_rd_out[225]
    DIRECTION OUTPUT ;
    USE SIGNAL ;
    SHAPE ABUTMENT ;
    PORT
      LAYER met2 ;
      RECT 934.190 948.860 934.330 949.280 ;
    END
  END r0_rd_out[225]
  PIN r0_rd_out[226]
    DIRECTION OUTPUT ;
    USE SIGNAL ;
    SHAPE ABUTMENT ;
    PORT
      LAYER met2 ;
      RECT 938.330 948.860 938.470 949.280 ;
    END
  END r0_rd_out[226]
  PIN r0_rd_out[227]
    DIRECTION OUTPUT ;
    USE SIGNAL ;
    SHAPE ABUTMENT ;
    PORT
      LAYER met2 ;
      RECT 942.470 948.860 942.610 949.280 ;
    END
  END r0_rd_out[227]
  PIN r0_rd_out[228]
    DIRECTION OUTPUT ;
    USE SIGNAL ;
    SHAPE ABUTMENT ;
    PORT
      LAYER met2 ;
      RECT 946.610 948.860 946.750 949.280 ;
    END
  END r0_rd_out[228]
  PIN r0_rd_out[229]
    DIRECTION OUTPUT ;
    USE SIGNAL ;
    SHAPE ABUTMENT ;
    PORT
      LAYER met2 ;
      RECT 950.750 948.860 950.890 949.280 ;
    END
  END r0_rd_out[229]
  PIN rw0_addr_in[0]
    DIRECTION INPUT ;
    USE SIGNAL ;
    SHAPE ABUTMENT ;
    PORT
      LAYER met3 ;
      RECT 0.000 832.170 0.900 832.470 ;
    END
  END rw0_addr_in[0]
  PIN rw0_addr_in[1]
    DIRECTION INPUT ;
    USE SIGNAL ;
    SHAPE ABUTMENT ;
    PORT
      LAYER met3 ;
      RECT 0.000 846.450 0.900 846.750 ;
    END
  END rw0_addr_in[1]
  PIN rw0_addr_in[2]
    DIRECTION INPUT ;
    USE SIGNAL ;
    SHAPE ABUTMENT ;
    PORT
      LAYER met3 ;
      RECT 0.000 860.730 0.900 861.030 ;
    END
  END rw0_addr_in[2]
  PIN rw0_addr_in[3]
    DIRECTION INPUT ;
    USE SIGNAL ;
    SHAPE ABUTMENT ;
    PORT
      LAYER met3 ;
      RECT 0.000 875.010 0.900 875.310 ;
    END
  END rw0_addr_in[3]
  PIN rw0_addr_in[4]
    DIRECTION INPUT ;
    USE SIGNAL ;
    SHAPE ABUTMENT ;
    PORT
      LAYER met3 ;
      RECT 1045.140 817.890 1046.040 818.190 ;
    END
  END rw0_addr_in[4]
  PIN rw0_addr_in[5]
    DIRECTION INPUT ;
    USE SIGNAL ;
    SHAPE ABUTMENT ;
    PORT
      LAYER met3 ;
      RECT 1045.140 832.170 1046.040 832.470 ;
    END
  END rw0_addr_in[5]
  PIN rw0_addr_in[6]
    DIRECTION INPUT ;
    USE SIGNAL ;
    SHAPE ABUTMENT ;
    PORT
      LAYER met3 ;
      RECT 1045.140 846.450 1046.040 846.750 ;
    END
  END rw0_addr_in[6]
  PIN r0_addr_in[0]
    DIRECTION INPUT ;
    USE SIGNAL ;
    SHAPE ABUTMENT ;
    PORT
      LAYER met3 ;
      RECT 0.000 889.290 0.900 889.590 ;
    END
  END r0_addr_in[0]
  PIN r0_addr_in[1]
    DIRECTION INPUT ;
    USE SIGNAL ;
    SHAPE ABUTMENT ;
    PORT
      LAYER met3 ;
      RECT 0.000 903.570 0.900 903.870 ;
    END
  END r0_addr_in[1]
  PIN r0_addr_in[2]
    DIRECTION INPUT ;
    USE SIGNAL ;
    SHAPE ABUTMENT ;
    PORT
      LAYER met3 ;
      RECT 0.000 917.850 0.900 918.150 ;
    END
  END r0_addr_in[2]
  PIN r0_addr_in[3]
    DIRECTION INPUT ;
    USE SIGNAL ;
    SHAPE ABUTMENT ;
    PORT
      LAYER met3 ;
      RECT 0.000 932.130 0.900 932.430 ;
    END
  END r0_addr_in[3]
  PIN r0_addr_in[4]
    DIRECTION INPUT ;
    USE SIGNAL ;
    SHAPE ABUTMENT ;
    PORT
      LAYER met3 ;
      RECT 1045.140 860.730 1046.040 861.030 ;
    END
  END r0_addr_in[4]
  PIN r0_addr_in[5]
    DIRECTION INPUT ;
    USE SIGNAL ;
    SHAPE ABUTMENT ;
    PORT
      LAYER met3 ;
      RECT 1045.140 875.010 1046.040 875.310 ;
    END
  END r0_addr_in[5]
  PIN r0_addr_in[6]
    DIRECTION INPUT ;
    USE SIGNAL ;
    SHAPE ABUTMENT ;
    PORT
      LAYER met3 ;
      RECT 1045.140 889.290 1046.040 889.590 ;
    END
  END r0_addr_in[6]
  PIN rw0_we_in
    DIRECTION INPUT ;
    USE SIGNAL ;
    SHAPE ABUTMENT ;
    PORT
      LAYER met2 ;
      RECT 954.890 948.860 955.030 949.280 ;
    END
  END rw0_we_in
  PIN rw0_ce_in
    DIRECTION INPUT ;
    USE SIGNAL ;
    SHAPE ABUTMENT ;
    PORT
      LAYER met2 ;
      RECT 959.030 948.860 959.170 949.280 ;
    END
  END rw0_ce_in
  PIN rw0_clk
    DIRECTION INPUT ;
    USE SIGNAL ;
    SHAPE ABUTMENT ;
    PORT
      LAYER met2 ;
      RECT 963.170 948.860 963.310 949.280 ;
    END
  END rw0_clk
  PIN r0_ce_in
    DIRECTION INPUT ;
    USE SIGNAL ;
    SHAPE ABUTMENT ;
    PORT
      LAYER met2 ;
      RECT 967.310 948.860 967.450 949.280 ;
    END
  END r0_ce_in
  PIN r0_clk
    DIRECTION INPUT ;
    USE SIGNAL ;
    SHAPE ABUTMENT ;
    PORT
      LAYER met2 ;
      RECT 971.450 948.860 971.590 949.280 ;
    END
  END r0_clk
  PIN VSS
    DIRECTION INOUT ;
    USE GROUND ;
    PORT
      LAYER met4 ;
      RECT 2.160 4.080 3.360 945.200 ;
      RECT 13.040 4.080 14.240 945.200 ;
      RECT 23.920 4.080 25.120 945.200 ;
      RECT 34.800 4.080 36.000 945.200 ;
      RECT 45.680 4.080 46.880 945.200 ;
      RECT 56.560 4.080 57.760 945.200 ;
      RECT 67.440 4.080 68.640 945.200 ;
      RECT 78.320 4.080 79.520 945.200 ;
      RECT 89.200 4.080 90.400 945.200 ;
      RECT 100.080 4.080 101.280 945.200 ;
      RECT 110.960 4.080 112.160 945.200 ;
      RECT 121.840 4.080 123.040 945.200 ;
      RECT 132.720 4.080 133.920 945.200 ;
      RECT 143.600 4.080 144.800 945.200 ;
      RECT 154.480 4.080 155.680 945.200 ;
      RECT 165.360 4.080 166.560 945.200 ;
      RECT 176.240 4.080 177.440 945.200 ;
      RECT 187.120 4.080 188.320 945.200 ;
      RECT 198.000 4.080 199.200 945.200 ;
      RECT 208.880 4.080 210.080 945.200 ;
      RECT 219.760 4.080 220.960 945.200 ;
      RECT 230.640 4.080 231.840 945.200 ;
      RECT 241.520 4.080 242.720 945.200 ;
      RECT 252.400 4.080 253.600 945.200 ;
      RECT 263.280 4.080 264.480 945.200 ;
      RECT 274.160 4.080 275.360 945.200 ;
      RECT 285.040 4.080 286.240 945.200 ;
      RECT 295.920 4.080 297.120 945.200 ;
      RECT 306.800 4.080 308.000 945.200 ;
      RECT 317.680 4.080 318.880 945.200 ;
      RECT 328.560 4.080 329.760 945.200 ;
      RECT 339.440 4.080 340.640 945.200 ;
      RECT 350.320 4.080 351.520 945.200 ;
      RECT 361.200 4.080 362.400 945.200 ;
      RECT 372.080 4.080 373.280 945.200 ;
      RECT 382.960 4.080 384.160 945.200 ;
      RECT 393.840 4.080 395.040 945.200 ;
      RECT 404.720 4.080 405.920 945.200 ;
      RECT 415.600 4.080 416.800 945.200 ;
      RECT 426.480 4.080 427.680 945.200 ;
      RECT 437.360 4.080 438.560 945.200 ;
      RECT 448.240 4.080 449.440 945.200 ;
      RECT 459.120 4.080 460.320 945.200 ;
      RECT 470.000 4.080 471.200 945.200 ;
      RECT 480.880 4.080 482.080 945.200 ;
      RECT 491.760 4.080 492.960 945.200 ;
      RECT 502.640 4.080 503.840 945.200 ;
      RECT 513.520 4.080 514.720 945.200 ;
      RECT 524.400 4.080 525.600 945.200 ;
      RECT 535.280 4.080 536.480 945.200 ;
      RECT 546.160 4.080 547.360 945.200 ;
      RECT 557.040 4.080 558.240 945.200 ;
      RECT 567.920 4.080 569.120 945.200 ;
      RECT 578.800 4.080 580.000 945.200 ;
      RECT 589.680 4.080 590.880 945.200 ;
      RECT 600.560 4.080 601.760 945.200 ;
      RECT 611.440 4.080 612.640 945.200 ;
      RECT 622.320 4.080 623.520 945.200 ;
      RECT 633.200 4.080 634.400 945.200 ;
      RECT 644.080 4.080 645.280 945.200 ;
      RECT 654.960 4.080 656.160 945.200 ;
      RECT 665.840 4.080 667.040 945.200 ;
      RECT 676.720 4.080 677.920 945.200 ;
      RECT 687.600 4.080 688.800 945.200 ;
      RECT 698.480 4.080 699.680 945.200 ;
      RECT 709.360 4.080 710.560 945.200 ;
      RECT 720.240 4.080 721.440 945.200 ;
      RECT 731.120 4.080 732.320 945.200 ;
      RECT 742.000 4.080 743.200 945.200 ;
      RECT 752.880 4.080 754.080 945.200 ;
      RECT 763.760 4.080 764.960 945.200 ;
      RECT 774.640 4.080 775.840 945.200 ;
      RECT 785.520 4.080 786.720 945.200 ;
      RECT 796.400 4.080 797.600 945.200 ;
      RECT 807.280 4.080 808.480 945.200 ;
      RECT 818.160 4.080 819.360 945.200 ;
      RECT 829.040 4.080 830.240 945.200 ;
      RECT 839.920 4.080 841.120 945.200 ;
      RECT 850.800 4.080 852.000 945.200 ;
      RECT 861.680 4.080 862.880 945.200 ;
      RECT 872.560 4.080 873.760 945.200 ;
      RECT 883.440 4.080 884.640 945.200 ;
      RECT 894.320 4.080 895.520 945.200 ;
      RECT 905.200 4.080 906.400 945.200 ;
      RECT 916.080 4.080 917.280 945.200 ;
      RECT 926.960 4.080 928.160 945.200 ;
      RECT 937.840 4.080 939.040 945.200 ;
      RECT 948.720 4.080 949.920 945.200 ;
      RECT 959.600 4.080 960.800 945.200 ;
      RECT 970.480 4.080 971.680 945.200 ;
      RECT 981.360 4.080 982.560 945.200 ;
      RECT 992.240 4.080 993.440 945.200 ;
      RECT 1003.120 4.080 1004.320 945.200 ;
      RECT 1014.000 4.080 1015.200 945.200 ;
      RECT 1024.880 4.080 1026.080 945.200 ;
      RECT 1035.760 4.080 1036.960 945.200 ;
    END
  END VSS
  PIN VDD
    DIRECTION INOUT ;
    USE POWER ;
    PORT
      LAYER met4 ;
      RECT 7.600 4.080 8.800 945.200 ;
      RECT 18.480 4.080 19.680 945.200 ;
      RECT 29.360 4.080 30.560 945.200 ;
      RECT 40.240 4.080 41.440 945.200 ;
      RECT 51.120 4.080 52.320 945.200 ;
      RECT 62.000 4.080 63.200 945.200 ;
      RECT 72.880 4.080 74.080 945.200 ;
      RECT 83.760 4.080 84.960 945.200 ;
      RECT 94.640 4.080 95.840 945.200 ;
      RECT 105.520 4.080 106.720 945.200 ;
      RECT 116.400 4.080 117.600 945.200 ;
      RECT 127.280 4.080 128.480 945.200 ;
      RECT 138.160 4.080 139.360 945.200 ;
      RECT 149.040 4.080 150.240 945.200 ;
      RECT 159.920 4.080 161.120 945.200 ;
      RECT 170.800 4.080 172.000 945.200 ;
      RECT 181.680 4.080 182.880 945.200 ;
      RECT 192.560 4.080 193.760 945.200 ;
      RECT 203.440 4.080 204.640 945.200 ;
      RECT 214.320 4.080 215.520 945.200 ;
      RECT 225.200 4.080 226.400 945.200 ;
      RECT 236.080 4.080 237.280 945.200 ;
      RECT 246.960 4.080 248.160 945.200 ;
      RECT 257.840 4.080 259.040 945.200 ;
      RECT 268.720 4.080 269.920 945.200 ;
      RECT 279.600 4.080 280.800 945.200 ;
      RECT 290.480 4.080 291.680 945.200 ;
      RECT 301.360 4.080 302.560 945.200 ;
      RECT 312.240 4.080 313.440 945.200 ;
      RECT 323.120 4.080 324.320 945.200 ;
      RECT 334.000 4.080 335.200 945.200 ;
      RECT 344.880 4.080 346.080 945.200 ;
      RECT 355.760 4.080 356.960 945.200 ;
      RECT 366.640 4.080 367.840 945.200 ;
      RECT 377.520 4.080 378.720 945.200 ;
      RECT 388.400 4.080 389.600 945.200 ;
      RECT 399.280 4.080 400.480 945.200 ;
      RECT 410.160 4.080 411.360 945.200 ;
      RECT 421.040 4.080 422.240 945.200 ;
      RECT 431.920 4.080 433.120 945.200 ;
      RECT 442.800 4.080 444.000 945.200 ;
      RECT 453.680 4.080 454.880 945.200 ;
      RECT 464.560 4.080 465.760 945.200 ;
      RECT 475.440 4.080 476.640 945.200 ;
      RECT 486.320 4.080 487.520 945.200 ;
      RECT 497.200 4.080 498.400 945.200 ;
      RECT 508.080 4.080 509.280 945.200 ;
      RECT 518.960 4.080 520.160 945.200 ;
      RECT 529.840 4.080 531.040 945.200 ;
      RECT 540.720 4.080 541.920 945.200 ;
      RECT 551.600 4.080 552.800 945.200 ;
      RECT 562.480 4.080 563.680 945.200 ;
      RECT 573.360 4.080 574.560 945.200 ;
      RECT 584.240 4.080 585.440 945.200 ;
      RECT 595.120 4.080 596.320 945.200 ;
      RECT 606.000 4.080 607.200 945.200 ;
      RECT 616.880 4.080 618.080 945.200 ;
      RECT 627.760 4.080 628.960 945.200 ;
      RECT 638.640 4.080 639.840 945.200 ;
      RECT 649.520 4.080 650.720 945.200 ;
      RECT 660.400 4.080 661.600 945.200 ;
      RECT 671.280 4.080 672.480 945.200 ;
      RECT 682.160 4.080 683.360 945.200 ;
      RECT 693.040 4.080 694.240 945.200 ;
      RECT 703.920 4.080 705.120 945.200 ;
      RECT 714.800 4.080 716.000 945.200 ;
      RECT 725.680 4.080 726.880 945.200 ;
      RECT 736.560 4.080 737.760 945.200 ;
      RECT 747.440 4.080 748.640 945.200 ;
      RECT 758.320 4.080 759.520 945.200 ;
      RECT 769.200 4.080 770.400 945.200 ;
      RECT 780.080 4.080 781.280 945.200 ;
      RECT 790.960 4.080 792.160 945.200 ;
      RECT 801.840 4.080 803.040 945.200 ;
      RECT 812.720 4.080 813.920 945.200 ;
      RECT 823.600 4.080 824.800 945.200 ;
      RECT 834.480 4.080 835.680 945.200 ;
      RECT 845.360 4.080 846.560 945.200 ;
      RECT 856.240 4.080 857.440 945.200 ;
      RECT 867.120 4.080 868.320 945.200 ;
      RECT 878.000 4.080 879.200 945.200 ;
      RECT 888.880 4.080 890.080 945.200 ;
      RECT 899.760 4.080 900.960 945.200 ;
      RECT 910.640 4.080 911.840 945.200 ;
      RECT 921.520 4.080 922.720 945.200 ;
      RECT 932.400 4.080 933.600 945.200 ;
      RECT 943.280 4.080 944.480 945.200 ;
      RECT 954.160 4.080 955.360 945.200 ;
      RECT 965.040 4.080 966.240 945.200 ;
      RECT 975.920 4.080 977.120 945.200 ;
      RECT 986.800 4.080 988.000 945.200 ;
      RECT 997.680 4.080 998.880 945.200 ;
      RECT 1008.560 4.080 1009.760 945.200 ;
      RECT 1019.440 4.080 1020.640 945.200 ;
      RECT 1030.320 4.080 1031.520 945.200 ;
      RECT 1041.200 4.080 1042.400 945.200 ;
    END
  END VDD
  OBS
    LAYER met1 ;
    RECT 0 0 1046.040 949.280 ;
    LAYER met2 ;
    RECT 0 0 1046.040 949.280 ;
    LAYER met3 ;
    RECT 0 0 1046.040 949.280 ;
    LAYER met4 ;
    RECT 0 0 1046.040 949.280 ;
  END
END fakeram_1rw1r_230w128d_sram

END LIBRARY
